VERSION 5.8 ;
BUSBITCHARS "[]" ;
DIVIDERCHAR "/" ;
UNITS
    DATABASE MICRONS 1000 ;
END UNITS

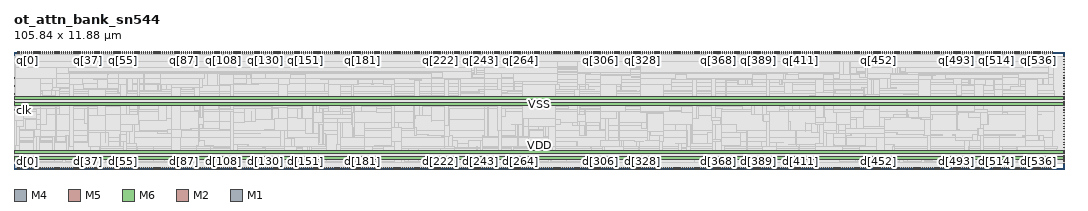
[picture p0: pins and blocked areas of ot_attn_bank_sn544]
MACRO ot_attn_bank_sn544
  FOREIGN ot_attn_bank_sn544 0 0 ;
  CLASS BLOCK ;
  SIZE 105.84 BY 11.88 ;
  PIN clk
    DIRECTION INPUT ;
    USE SIGNAL ;
    PORT
      LAYER M4 ;
        RECT  0 5.928 0.192 5.952 ;
    END
  END clk
  PIN d[0]
    DIRECTION INPUT ;
    USE SIGNAL ;
    PORT
      LAYER M5 ;
        RECT  0.384 0 0.408 0.192 ;
    END
  END d[0]
  PIN d[100]
    DIRECTION INPUT ;
    USE SIGNAL ;
    PORT
      LAYER M5 ;
        RECT  19.584 0 19.608 0.192 ;
    END
  END d[100]
  PIN d[101]
    DIRECTION INPUT ;
    USE SIGNAL ;
    PORT
      LAYER M5 ;
        RECT  19.776 0 19.8 0.192 ;
    END
  END d[101]
  PIN d[102]
    DIRECTION INPUT ;
    USE SIGNAL ;
    PORT
      LAYER M5 ;
        RECT  19.968 0 19.992 0.192 ;
    END
  END d[102]
  PIN d[103]
    DIRECTION INPUT ;
    USE SIGNAL ;
    PORT
      LAYER M5 ;
        RECT  20.16 0 20.184 0.192 ;
    END
  END d[103]
  PIN d[104]
    DIRECTION INPUT ;
    USE SIGNAL ;
    PORT
      LAYER M5 ;
        RECT  20.352 0 20.376 0.192 ;
    END
  END d[104]
  PIN d[105]
    DIRECTION INPUT ;
    USE SIGNAL ;
    PORT
      LAYER M5 ;
        RECT  20.544 0 20.568 0.192 ;
    END
  END d[105]
  PIN d[106]
    DIRECTION INPUT ;
    USE SIGNAL ;
    PORT
      LAYER M5 ;
        RECT  20.736 0 20.76 0.192 ;
    END
  END d[106]
  PIN d[107]
    DIRECTION INPUT ;
    USE SIGNAL ;
    PORT
      LAYER M5 ;
        RECT  20.928 0 20.952 0.192 ;
    END
  END d[107]
  PIN d[108]
    DIRECTION INPUT ;
    USE SIGNAL ;
    PORT
      LAYER M5 ;
        RECT  21.12 0 21.144 0.192 ;
    END
  END d[108]
  PIN d[109]
    DIRECTION INPUT ;
    USE SIGNAL ;
    PORT
      LAYER M5 ;
        RECT  21.312 0 21.336 0.192 ;
    END
  END d[109]
  PIN d[10]
    DIRECTION INPUT ;
    USE SIGNAL ;
    PORT
      LAYER M5 ;
        RECT  2.304 0 2.328 0.192 ;
    END
  END d[10]
  PIN d[110]
    DIRECTION INPUT ;
    USE SIGNAL ;
    PORT
      LAYER M5 ;
        RECT  21.504 0 21.528 0.192 ;
    END
  END d[110]
  PIN d[111]
    DIRECTION INPUT ;
    USE SIGNAL ;
    PORT
      LAYER M5 ;
        RECT  21.696 0 21.72 0.192 ;
    END
  END d[111]
  PIN d[112]
    DIRECTION INPUT ;
    USE SIGNAL ;
    PORT
      LAYER M5 ;
        RECT  21.888 0 21.912 0.192 ;
    END
  END d[112]
  PIN d[113]
    DIRECTION INPUT ;
    USE SIGNAL ;
    PORT
      LAYER M5 ;
        RECT  22.08 0 22.104 0.192 ;
    END
  END d[113]
  PIN d[114]
    DIRECTION INPUT ;
    USE SIGNAL ;
    PORT
      LAYER M5 ;
        RECT  22.272 0 22.296 0.192 ;
    END
  END d[114]
  PIN d[115]
    DIRECTION INPUT ;
    USE SIGNAL ;
    PORT
      LAYER M5 ;
        RECT  22.464 0 22.488 0.192 ;
    END
  END d[115]
  PIN d[116]
    DIRECTION INPUT ;
    USE SIGNAL ;
    PORT
      LAYER M5 ;
        RECT  22.656 0 22.68 0.192 ;
    END
  END d[116]
  PIN d[117]
    DIRECTION INPUT ;
    USE SIGNAL ;
    PORT
      LAYER M5 ;
        RECT  22.848 0 22.872 0.192 ;
    END
  END d[117]
  PIN d[118]
    DIRECTION INPUT ;
    USE SIGNAL ;
    PORT
      LAYER M5 ;
        RECT  23.04 0 23.064 0.192 ;
    END
  END d[118]
  PIN d[119]
    DIRECTION INPUT ;
    USE SIGNAL ;
    PORT
      LAYER M5 ;
        RECT  23.232 0 23.256 0.192 ;
    END
  END d[119]
  PIN d[11]
    DIRECTION INPUT ;
    USE SIGNAL ;
    PORT
      LAYER M5 ;
        RECT  2.496 0 2.52 0.192 ;
    END
  END d[11]
  PIN d[120]
    DIRECTION INPUT ;
    USE SIGNAL ;
    PORT
      LAYER M5 ;
        RECT  23.424 0 23.448 0.192 ;
    END
  END d[120]
  PIN d[121]
    DIRECTION INPUT ;
    USE SIGNAL ;
    PORT
      LAYER M5 ;
        RECT  23.616 0 23.64 0.192 ;
    END
  END d[121]
  PIN d[122]
    DIRECTION INPUT ;
    USE SIGNAL ;
    PORT
      LAYER M5 ;
        RECT  23.808 0 23.832 0.192 ;
    END
  END d[122]
  PIN d[123]
    DIRECTION INPUT ;
    USE SIGNAL ;
    PORT
      LAYER M5 ;
        RECT  24 0 24.024 0.192 ;
    END
  END d[123]
  PIN d[124]
    DIRECTION INPUT ;
    USE SIGNAL ;
    PORT
      LAYER M5 ;
        RECT  24.192 0 24.216 0.192 ;
    END
  END d[124]
  PIN d[125]
    DIRECTION INPUT ;
    USE SIGNAL ;
    PORT
      LAYER M5 ;
        RECT  24.384 0 24.408 0.192 ;
    END
  END d[125]
  PIN d[126]
    DIRECTION INPUT ;
    USE SIGNAL ;
    PORT
      LAYER M5 ;
        RECT  24.576 0 24.6 0.192 ;
    END
  END d[126]
  PIN d[127]
    DIRECTION INPUT ;
    USE SIGNAL ;
    PORT
      LAYER M5 ;
        RECT  24.768 0 24.792 0.192 ;
    END
  END d[127]
  PIN d[128]
    DIRECTION INPUT ;
    USE SIGNAL ;
    PORT
      LAYER M5 ;
        RECT  24.96 0 24.984 0.192 ;
    END
  END d[128]
  PIN d[129]
    DIRECTION INPUT ;
    USE SIGNAL ;
    PORT
      LAYER M5 ;
        RECT  25.152 0 25.176 0.192 ;
    END
  END d[129]
  PIN d[12]
    DIRECTION INPUT ;
    USE SIGNAL ;
    PORT
      LAYER M5 ;
        RECT  2.688 0 2.712 0.192 ;
    END
  END d[12]
  PIN d[130]
    DIRECTION INPUT ;
    USE SIGNAL ;
    PORT
      LAYER M5 ;
        RECT  25.344 0 25.368 0.192 ;
    END
  END d[130]
  PIN d[131]
    DIRECTION INPUT ;
    USE SIGNAL ;
    PORT
      LAYER M5 ;
        RECT  25.536 0 25.56 0.192 ;
    END
  END d[131]
  PIN d[132]
    DIRECTION INPUT ;
    USE SIGNAL ;
    PORT
      LAYER M5 ;
        RECT  25.728 0 25.752 0.192 ;
    END
  END d[132]
  PIN d[133]
    DIRECTION INPUT ;
    USE SIGNAL ;
    PORT
      LAYER M5 ;
        RECT  25.92 0 25.944 0.192 ;
    END
  END d[133]
  PIN d[134]
    DIRECTION INPUT ;
    USE SIGNAL ;
    PORT
      LAYER M5 ;
        RECT  26.112 0 26.136 0.192 ;
    END
  END d[134]
  PIN d[135]
    DIRECTION INPUT ;
    USE SIGNAL ;
    PORT
      LAYER M5 ;
        RECT  26.304 0 26.328 0.192 ;
    END
  END d[135]
  PIN d[136]
    DIRECTION INPUT ;
    USE SIGNAL ;
    PORT
      LAYER M5 ;
        RECT  26.496 0 26.52 0.192 ;
    END
  END d[136]
  PIN d[137]
    DIRECTION INPUT ;
    USE SIGNAL ;
    PORT
      LAYER M5 ;
        RECT  26.688 0 26.712 0.192 ;
    END
  END d[137]
  PIN d[138]
    DIRECTION INPUT ;
    USE SIGNAL ;
    PORT
      LAYER M5 ;
        RECT  26.88 0 26.904 0.192 ;
    END
  END d[138]
  PIN d[139]
    DIRECTION INPUT ;
    USE SIGNAL ;
    PORT
      LAYER M5 ;
        RECT  27.072 0 27.096 0.192 ;
    END
  END d[139]
  PIN d[13]
    DIRECTION INPUT ;
    USE SIGNAL ;
    PORT
      LAYER M5 ;
        RECT  2.88 0 2.904 0.192 ;
    END
  END d[13]
  PIN d[140]
    DIRECTION INPUT ;
    USE SIGNAL ;
    PORT
      LAYER M5 ;
        RECT  27.264 0 27.288 0.192 ;
    END
  END d[140]
  PIN d[141]
    DIRECTION INPUT ;
    USE SIGNAL ;
    PORT
      LAYER M5 ;
        RECT  27.456 0 27.48 0.192 ;
    END
  END d[141]
  PIN d[142]
    DIRECTION INPUT ;
    USE SIGNAL ;
    PORT
      LAYER M5 ;
        RECT  27.648 0 27.672 0.192 ;
    END
  END d[142]
  PIN d[143]
    DIRECTION INPUT ;
    USE SIGNAL ;
    PORT
      LAYER M5 ;
        RECT  27.84 0 27.864 0.192 ;
    END
  END d[143]
  PIN d[144]
    DIRECTION INPUT ;
    USE SIGNAL ;
    PORT
      LAYER M5 ;
        RECT  28.032 0 28.056 0.192 ;
    END
  END d[144]
  PIN d[145]
    DIRECTION INPUT ;
    USE SIGNAL ;
    PORT
      LAYER M5 ;
        RECT  28.224 0 28.248 0.192 ;
    END
  END d[145]
  PIN d[146]
    DIRECTION INPUT ;
    USE SIGNAL ;
    PORT
      LAYER M5 ;
        RECT  28.416 0 28.44 0.192 ;
    END
  END d[146]
  PIN d[147]
    DIRECTION INPUT ;
    USE SIGNAL ;
    PORT
      LAYER M5 ;
        RECT  28.608 0 28.632 0.192 ;
    END
  END d[147]
  PIN d[148]
    DIRECTION INPUT ;
    USE SIGNAL ;
    PORT
      LAYER M5 ;
        RECT  28.8 0 28.824 0.192 ;
    END
  END d[148]
  PIN d[149]
    DIRECTION INPUT ;
    USE SIGNAL ;
    PORT
      LAYER M5 ;
        RECT  28.992 0 29.016 0.192 ;
    END
  END d[149]
  PIN d[14]
    DIRECTION INPUT ;
    USE SIGNAL ;
    PORT
      LAYER M5 ;
        RECT  3.072 0 3.096 0.192 ;
    END
  END d[14]
  PIN d[150]
    DIRECTION INPUT ;
    USE SIGNAL ;
    PORT
      LAYER M5 ;
        RECT  29.184 0 29.208 0.192 ;
    END
  END d[150]
  PIN d[151]
    DIRECTION INPUT ;
    USE SIGNAL ;
    PORT
      LAYER M5 ;
        RECT  29.376 0 29.4 0.192 ;
    END
  END d[151]
  PIN d[152]
    DIRECTION INPUT ;
    USE SIGNAL ;
    PORT
      LAYER M5 ;
        RECT  29.568 0 29.592 0.192 ;
    END
  END d[152]
  PIN d[153]
    DIRECTION INPUT ;
    USE SIGNAL ;
    PORT
      LAYER M5 ;
        RECT  29.76 0 29.784 0.192 ;
    END
  END d[153]
  PIN d[154]
    DIRECTION INPUT ;
    USE SIGNAL ;
    PORT
      LAYER M5 ;
        RECT  29.952 0 29.976 0.192 ;
    END
  END d[154]
  PIN d[155]
    DIRECTION INPUT ;
    USE SIGNAL ;
    PORT
      LAYER M5 ;
        RECT  30.144 0 30.168 0.192 ;
    END
  END d[155]
  PIN d[156]
    DIRECTION INPUT ;
    USE SIGNAL ;
    PORT
      LAYER M5 ;
        RECT  30.336 0 30.36 0.192 ;
    END
  END d[156]
  PIN d[157]
    DIRECTION INPUT ;
    USE SIGNAL ;
    PORT
      LAYER M5 ;
        RECT  30.528 0 30.552 0.192 ;
    END
  END d[157]
  PIN d[158]
    DIRECTION INPUT ;
    USE SIGNAL ;
    PORT
      LAYER M5 ;
        RECT  30.72 0 30.744 0.192 ;
    END
  END d[158]
  PIN d[159]
    DIRECTION INPUT ;
    USE SIGNAL ;
    PORT
      LAYER M5 ;
        RECT  30.912 0 30.936 0.192 ;
    END
  END d[159]
  PIN d[15]
    DIRECTION INPUT ;
    USE SIGNAL ;
    PORT
      LAYER M5 ;
        RECT  3.264 0 3.288 0.192 ;
    END
  END d[15]
  PIN d[160]
    DIRECTION INPUT ;
    USE SIGNAL ;
    PORT
      LAYER M5 ;
        RECT  31.104 0 31.128 0.192 ;
    END
  END d[160]
  PIN d[161]
    DIRECTION INPUT ;
    USE SIGNAL ;
    PORT
      LAYER M5 ;
        RECT  31.296 0 31.32 0.192 ;
    END
  END d[161]
  PIN d[162]
    DIRECTION INPUT ;
    USE SIGNAL ;
    PORT
      LAYER M5 ;
        RECT  31.488 0 31.512 0.192 ;
    END
  END d[162]
  PIN d[163]
    DIRECTION INPUT ;
    USE SIGNAL ;
    PORT
      LAYER M5 ;
        RECT  31.68 0 31.704 0.192 ;
    END
  END d[163]
  PIN d[164]
    DIRECTION INPUT ;
    USE SIGNAL ;
    PORT
      LAYER M5 ;
        RECT  31.872 0 31.896 0.192 ;
    END
  END d[164]
  PIN d[165]
    DIRECTION INPUT ;
    USE SIGNAL ;
    PORT
      LAYER M5 ;
        RECT  32.064 0 32.088 0.192 ;
    END
  END d[165]
  PIN d[166]
    DIRECTION INPUT ;
    USE SIGNAL ;
    PORT
      LAYER M5 ;
        RECT  32.256 0 32.28 0.192 ;
    END
  END d[166]
  PIN d[167]
    DIRECTION INPUT ;
    USE SIGNAL ;
    PORT
      LAYER M5 ;
        RECT  32.448 0 32.472 0.192 ;
    END
  END d[167]
  PIN d[168]
    DIRECTION INPUT ;
    USE SIGNAL ;
    PORT
      LAYER M5 ;
        RECT  32.64 0 32.664 0.192 ;
    END
  END d[168]
  PIN d[169]
    DIRECTION INPUT ;
    USE SIGNAL ;
    PORT
      LAYER M5 ;
        RECT  32.832 0 32.856 0.192 ;
    END
  END d[169]
  PIN d[16]
    DIRECTION INPUT ;
    USE SIGNAL ;
    PORT
      LAYER M5 ;
        RECT  3.456 0 3.48 0.192 ;
    END
  END d[16]
  PIN d[170]
    DIRECTION INPUT ;
    USE SIGNAL ;
    PORT
      LAYER M5 ;
        RECT  33.024 0 33.048 0.192 ;
    END
  END d[170]
  PIN d[171]
    DIRECTION INPUT ;
    USE SIGNAL ;
    PORT
      LAYER M5 ;
        RECT  33.216 0 33.24 0.192 ;
    END
  END d[171]
  PIN d[172]
    DIRECTION INPUT ;
    USE SIGNAL ;
    PORT
      LAYER M5 ;
        RECT  33.408 0 33.432 0.192 ;
    END
  END d[172]
  PIN d[173]
    DIRECTION INPUT ;
    USE SIGNAL ;
    PORT
      LAYER M5 ;
        RECT  33.6 0 33.624 0.192 ;
    END
  END d[173]
  PIN d[174]
    DIRECTION INPUT ;
    USE SIGNAL ;
    PORT
      LAYER M5 ;
        RECT  33.792 0 33.816 0.192 ;
    END
  END d[174]
  PIN d[175]
    DIRECTION INPUT ;
    USE SIGNAL ;
    PORT
      LAYER M5 ;
        RECT  33.984 0 34.008 0.192 ;
    END
  END d[175]
  PIN d[176]
    DIRECTION INPUT ;
    USE SIGNAL ;
    PORT
      LAYER M5 ;
        RECT  34.176 0 34.2 0.192 ;
    END
  END d[176]
  PIN d[177]
    DIRECTION INPUT ;
    USE SIGNAL ;
    PORT
      LAYER M5 ;
        RECT  34.368 0 34.392 0.192 ;
    END
  END d[177]
  PIN d[178]
    DIRECTION INPUT ;
    USE SIGNAL ;
    PORT
      LAYER M5 ;
        RECT  34.56 0 34.584 0.192 ;
    END
  END d[178]
  PIN d[179]
    DIRECTION INPUT ;
    USE SIGNAL ;
    PORT
      LAYER M5 ;
        RECT  34.752 0 34.776 0.192 ;
    END
  END d[179]
  PIN d[17]
    DIRECTION INPUT ;
    USE SIGNAL ;
    PORT
      LAYER M5 ;
        RECT  3.648 0 3.672 0.192 ;
    END
  END d[17]
  PIN d[180]
    DIRECTION INPUT ;
    USE SIGNAL ;
    PORT
      LAYER M5 ;
        RECT  34.944 0 34.968 0.192 ;
    END
  END d[180]
  PIN d[181]
    DIRECTION INPUT ;
    USE SIGNAL ;
    PORT
      LAYER M5 ;
        RECT  35.136 0 35.16 0.192 ;
    END
  END d[181]
  PIN d[182]
    DIRECTION INPUT ;
    USE SIGNAL ;
    PORT
      LAYER M5 ;
        RECT  35.328 0 35.352 0.192 ;
    END
  END d[182]
  PIN d[183]
    DIRECTION INPUT ;
    USE SIGNAL ;
    PORT
      LAYER M5 ;
        RECT  35.52 0 35.544 0.192 ;
    END
  END d[183]
  PIN d[184]
    DIRECTION INPUT ;
    USE SIGNAL ;
    PORT
      LAYER M5 ;
        RECT  35.712 0 35.736 0.192 ;
    END
  END d[184]
  PIN d[185]
    DIRECTION INPUT ;
    USE SIGNAL ;
    PORT
      LAYER M5 ;
        RECT  35.904 0 35.928 0.192 ;
    END
  END d[185]
  PIN d[186]
    DIRECTION INPUT ;
    USE SIGNAL ;
    PORT
      LAYER M5 ;
        RECT  36.096 0 36.12 0.192 ;
    END
  END d[186]
  PIN d[187]
    DIRECTION INPUT ;
    USE SIGNAL ;
    PORT
      LAYER M5 ;
        RECT  36.288 0 36.312 0.192 ;
    END
  END d[187]
  PIN d[188]
    DIRECTION INPUT ;
    USE SIGNAL ;
    PORT
      LAYER M5 ;
        RECT  36.48 0 36.504 0.192 ;
    END
  END d[188]
  PIN d[189]
    DIRECTION INPUT ;
    USE SIGNAL ;
    PORT
      LAYER M5 ;
        RECT  36.672 0 36.696 0.192 ;
    END
  END d[189]
  PIN d[18]
    DIRECTION INPUT ;
    USE SIGNAL ;
    PORT
      LAYER M5 ;
        RECT  3.84 0 3.864 0.192 ;
    END
  END d[18]
  PIN d[190]
    DIRECTION INPUT ;
    USE SIGNAL ;
    PORT
      LAYER M5 ;
        RECT  36.864 0 36.888 0.192 ;
    END
  END d[190]
  PIN d[191]
    DIRECTION INPUT ;
    USE SIGNAL ;
    PORT
      LAYER M5 ;
        RECT  37.056 0 37.08 0.192 ;
    END
  END d[191]
  PIN d[192]
    DIRECTION INPUT ;
    USE SIGNAL ;
    PORT
      LAYER M5 ;
        RECT  37.248 0 37.272 0.192 ;
    END
  END d[192]
  PIN d[193]
    DIRECTION INPUT ;
    USE SIGNAL ;
    PORT
      LAYER M5 ;
        RECT  37.44 0 37.464 0.192 ;
    END
  END d[193]
  PIN d[194]
    DIRECTION INPUT ;
    USE SIGNAL ;
    PORT
      LAYER M5 ;
        RECT  37.632 0 37.656 0.192 ;
    END
  END d[194]
  PIN d[195]
    DIRECTION INPUT ;
    USE SIGNAL ;
    PORT
      LAYER M5 ;
        RECT  37.824 0 37.848 0.192 ;
    END
  END d[195]
  PIN d[196]
    DIRECTION INPUT ;
    USE SIGNAL ;
    PORT
      LAYER M5 ;
        RECT  38.016 0 38.04 0.192 ;
    END
  END d[196]
  PIN d[197]
    DIRECTION INPUT ;
    USE SIGNAL ;
    PORT
      LAYER M5 ;
        RECT  38.208 0 38.232 0.192 ;
    END
  END d[197]
  PIN d[198]
    DIRECTION INPUT ;
    USE SIGNAL ;
    PORT
      LAYER M5 ;
        RECT  38.4 0 38.424 0.192 ;
    END
  END d[198]
  PIN d[199]
    DIRECTION INPUT ;
    USE SIGNAL ;
    PORT
      LAYER M5 ;
        RECT  38.592 0 38.616 0.192 ;
    END
  END d[199]
  PIN d[19]
    DIRECTION INPUT ;
    USE SIGNAL ;
    PORT
      LAYER M5 ;
        RECT  4.032 0 4.056 0.192 ;
    END
  END d[19]
  PIN d[1]
    DIRECTION INPUT ;
    USE SIGNAL ;
    PORT
      LAYER M5 ;
        RECT  0.576 0 0.6 0.192 ;
    END
  END d[1]
  PIN d[200]
    DIRECTION INPUT ;
    USE SIGNAL ;
    PORT
      LAYER M5 ;
        RECT  38.784 0 38.808 0.192 ;
    END
  END d[200]
  PIN d[201]
    DIRECTION INPUT ;
    USE SIGNAL ;
    PORT
      LAYER M5 ;
        RECT  38.976 0 39 0.192 ;
    END
  END d[201]
  PIN d[202]
    DIRECTION INPUT ;
    USE SIGNAL ;
    PORT
      LAYER M5 ;
        RECT  39.168 0 39.192 0.192 ;
    END
  END d[202]
  PIN d[203]
    DIRECTION INPUT ;
    USE SIGNAL ;
    PORT
      LAYER M5 ;
        RECT  39.36 0 39.384 0.192 ;
    END
  END d[203]
  PIN d[204]
    DIRECTION INPUT ;
    USE SIGNAL ;
    PORT
      LAYER M5 ;
        RECT  39.552 0 39.576 0.192 ;
    END
  END d[204]
  PIN d[205]
    DIRECTION INPUT ;
    USE SIGNAL ;
    PORT
      LAYER M5 ;
        RECT  39.744 0 39.768 0.192 ;
    END
  END d[205]
  PIN d[206]
    DIRECTION INPUT ;
    USE SIGNAL ;
    PORT
      LAYER M5 ;
        RECT  39.936 0 39.96 0.192 ;
    END
  END d[206]
  PIN d[207]
    DIRECTION INPUT ;
    USE SIGNAL ;
    PORT
      LAYER M5 ;
        RECT  40.128 0 40.152 0.192 ;
    END
  END d[207]
  PIN d[208]
    DIRECTION INPUT ;
    USE SIGNAL ;
    PORT
      LAYER M5 ;
        RECT  40.32 0 40.344 0.192 ;
    END
  END d[208]
  PIN d[209]
    DIRECTION INPUT ;
    USE SIGNAL ;
    PORT
      LAYER M5 ;
        RECT  40.512 0 40.536 0.192 ;
    END
  END d[209]
  PIN d[20]
    DIRECTION INPUT ;
    USE SIGNAL ;
    PORT
      LAYER M5 ;
        RECT  4.224 0 4.248 0.192 ;
    END
  END d[20]
  PIN d[210]
    DIRECTION INPUT ;
    USE SIGNAL ;
    PORT
      LAYER M5 ;
        RECT  40.704 0 40.728 0.192 ;
    END
  END d[210]
  PIN d[211]
    DIRECTION INPUT ;
    USE SIGNAL ;
    PORT
      LAYER M5 ;
        RECT  40.896 0 40.92 0.192 ;
    END
  END d[211]
  PIN d[212]
    DIRECTION INPUT ;
    USE SIGNAL ;
    PORT
      LAYER M5 ;
        RECT  41.088 0 41.112 0.192 ;
    END
  END d[212]
  PIN d[213]
    DIRECTION INPUT ;
    USE SIGNAL ;
    PORT
      LAYER M5 ;
        RECT  41.28 0 41.304 0.192 ;
    END
  END d[213]
  PIN d[214]
    DIRECTION INPUT ;
    USE SIGNAL ;
    PORT
      LAYER M5 ;
        RECT  41.472 0 41.496 0.192 ;
    END
  END d[214]
  PIN d[215]
    DIRECTION INPUT ;
    USE SIGNAL ;
    PORT
      LAYER M5 ;
        RECT  41.664 0 41.688 0.192 ;
    END
  END d[215]
  PIN d[216]
    DIRECTION INPUT ;
    USE SIGNAL ;
    PORT
      LAYER M5 ;
        RECT  41.856 0 41.88 0.192 ;
    END
  END d[216]
  PIN d[217]
    DIRECTION INPUT ;
    USE SIGNAL ;
    PORT
      LAYER M5 ;
        RECT  42.048 0 42.072 0.192 ;
    END
  END d[217]
  PIN d[218]
    DIRECTION INPUT ;
    USE SIGNAL ;
    PORT
      LAYER M5 ;
        RECT  42.24 0 42.264 0.192 ;
    END
  END d[218]
  PIN d[219]
    DIRECTION INPUT ;
    USE SIGNAL ;
    PORT
      LAYER M5 ;
        RECT  42.432 0 42.456 0.192 ;
    END
  END d[219]
  PIN d[21]
    DIRECTION INPUT ;
    USE SIGNAL ;
    PORT
      LAYER M5 ;
        RECT  4.416 0 4.44 0.192 ;
    END
  END d[21]
  PIN d[220]
    DIRECTION INPUT ;
    USE SIGNAL ;
    PORT
      LAYER M5 ;
        RECT  42.624 0 42.648 0.192 ;
    END
  END d[220]
  PIN d[221]
    DIRECTION INPUT ;
    USE SIGNAL ;
    PORT
      LAYER M5 ;
        RECT  42.816 0 42.84 0.192 ;
    END
  END d[221]
  PIN d[222]
    DIRECTION INPUT ;
    USE SIGNAL ;
    PORT
      LAYER M5 ;
        RECT  43.008 0 43.032 0.192 ;
    END
  END d[222]
  PIN d[223]
    DIRECTION INPUT ;
    USE SIGNAL ;
    PORT
      LAYER M5 ;
        RECT  43.2 0 43.224 0.192 ;
    END
  END d[223]
  PIN d[224]
    DIRECTION INPUT ;
    USE SIGNAL ;
    PORT
      LAYER M5 ;
        RECT  43.392 0 43.416 0.192 ;
    END
  END d[224]
  PIN d[225]
    DIRECTION INPUT ;
    USE SIGNAL ;
    PORT
      LAYER M5 ;
        RECT  43.584 0 43.608 0.192 ;
    END
  END d[225]
  PIN d[226]
    DIRECTION INPUT ;
    USE SIGNAL ;
    PORT
      LAYER M5 ;
        RECT  43.776 0 43.8 0.192 ;
    END
  END d[226]
  PIN d[227]
    DIRECTION INPUT ;
    USE SIGNAL ;
    PORT
      LAYER M5 ;
        RECT  43.968 0 43.992 0.192 ;
    END
  END d[227]
  PIN d[228]
    DIRECTION INPUT ;
    USE SIGNAL ;
    PORT
      LAYER M5 ;
        RECT  44.16 0 44.184 0.192 ;
    END
  END d[228]
  PIN d[229]
    DIRECTION INPUT ;
    USE SIGNAL ;
    PORT
      LAYER M5 ;
        RECT  44.352 0 44.376 0.192 ;
    END
  END d[229]
  PIN d[22]
    DIRECTION INPUT ;
    USE SIGNAL ;
    PORT
      LAYER M5 ;
        RECT  4.608 0 4.632 0.192 ;
    END
  END d[22]
  PIN d[230]
    DIRECTION INPUT ;
    USE SIGNAL ;
    PORT
      LAYER M5 ;
        RECT  44.544 0 44.568 0.192 ;
    END
  END d[230]
  PIN d[231]
    DIRECTION INPUT ;
    USE SIGNAL ;
    PORT
      LAYER M5 ;
        RECT  44.736 0 44.76 0.192 ;
    END
  END d[231]
  PIN d[232]
    DIRECTION INPUT ;
    USE SIGNAL ;
    PORT
      LAYER M5 ;
        RECT  44.928 0 44.952 0.192 ;
    END
  END d[232]
  PIN d[233]
    DIRECTION INPUT ;
    USE SIGNAL ;
    PORT
      LAYER M5 ;
        RECT  45.12 0 45.144 0.192 ;
    END
  END d[233]
  PIN d[234]
    DIRECTION INPUT ;
    USE SIGNAL ;
    PORT
      LAYER M5 ;
        RECT  45.312 0 45.336 0.192 ;
    END
  END d[234]
  PIN d[235]
    DIRECTION INPUT ;
    USE SIGNAL ;
    PORT
      LAYER M5 ;
        RECT  45.504 0 45.528 0.192 ;
    END
  END d[235]
  PIN d[236]
    DIRECTION INPUT ;
    USE SIGNAL ;
    PORT
      LAYER M5 ;
        RECT  45.696 0 45.72 0.192 ;
    END
  END d[236]
  PIN d[237]
    DIRECTION INPUT ;
    USE SIGNAL ;
    PORT
      LAYER M5 ;
        RECT  45.888 0 45.912 0.192 ;
    END
  END d[237]
  PIN d[238]
    DIRECTION INPUT ;
    USE SIGNAL ;
    PORT
      LAYER M5 ;
        RECT  46.08 0 46.104 0.192 ;
    END
  END d[238]
  PIN d[239]
    DIRECTION INPUT ;
    USE SIGNAL ;
    PORT
      LAYER M5 ;
        RECT  46.272 0 46.296 0.192 ;
    END
  END d[239]
  PIN d[23]
    DIRECTION INPUT ;
    USE SIGNAL ;
    PORT
      LAYER M5 ;
        RECT  4.8 0 4.824 0.192 ;
    END
  END d[23]
  PIN d[240]
    DIRECTION INPUT ;
    USE SIGNAL ;
    PORT
      LAYER M5 ;
        RECT  46.464 0 46.488 0.192 ;
    END
  END d[240]
  PIN d[241]
    DIRECTION INPUT ;
    USE SIGNAL ;
    PORT
      LAYER M5 ;
        RECT  46.656 0 46.68 0.192 ;
    END
  END d[241]
  PIN d[242]
    DIRECTION INPUT ;
    USE SIGNAL ;
    PORT
      LAYER M5 ;
        RECT  46.848 0 46.872 0.192 ;
    END
  END d[242]
  PIN d[243]
    DIRECTION INPUT ;
    USE SIGNAL ;
    PORT
      LAYER M5 ;
        RECT  47.04 0 47.064 0.192 ;
    END
  END d[243]
  PIN d[244]
    DIRECTION INPUT ;
    USE SIGNAL ;
    PORT
      LAYER M5 ;
        RECT  47.232 0 47.256 0.192 ;
    END
  END d[244]
  PIN d[245]
    DIRECTION INPUT ;
    USE SIGNAL ;
    PORT
      LAYER M5 ;
        RECT  47.424 0 47.448 0.192 ;
    END
  END d[245]
  PIN d[246]
    DIRECTION INPUT ;
    USE SIGNAL ;
    PORT
      LAYER M5 ;
        RECT  47.616 0 47.64 0.192 ;
    END
  END d[246]
  PIN d[247]
    DIRECTION INPUT ;
    USE SIGNAL ;
    PORT
      LAYER M5 ;
        RECT  47.808 0 47.832 0.192 ;
    END
  END d[247]
  PIN d[248]
    DIRECTION INPUT ;
    USE SIGNAL ;
    PORT
      LAYER M5 ;
        RECT  48 0 48.024 0.192 ;
    END
  END d[248]
  PIN d[249]
    DIRECTION INPUT ;
    USE SIGNAL ;
    PORT
      LAYER M5 ;
        RECT  48.192 0 48.216 0.192 ;
    END
  END d[249]
  PIN d[24]
    DIRECTION INPUT ;
    USE SIGNAL ;
    PORT
      LAYER M5 ;
        RECT  4.992 0 5.016 0.192 ;
    END
  END d[24]
  PIN d[250]
    DIRECTION INPUT ;
    USE SIGNAL ;
    PORT
      LAYER M5 ;
        RECT  48.384 0 48.408 0.192 ;
    END
  END d[250]
  PIN d[251]
    DIRECTION INPUT ;
    USE SIGNAL ;
    PORT
      LAYER M5 ;
        RECT  48.576 0 48.6 0.192 ;
    END
  END d[251]
  PIN d[252]
    DIRECTION INPUT ;
    USE SIGNAL ;
    PORT
      LAYER M5 ;
        RECT  48.768 0 48.792 0.192 ;
    END
  END d[252]
  PIN d[253]
    DIRECTION INPUT ;
    USE SIGNAL ;
    PORT
      LAYER M5 ;
        RECT  48.96 0 48.984 0.192 ;
    END
  END d[253]
  PIN d[254]
    DIRECTION INPUT ;
    USE SIGNAL ;
    PORT
      LAYER M5 ;
        RECT  49.152 0 49.176 0.192 ;
    END
  END d[254]
  PIN d[255]
    DIRECTION INPUT ;
    USE SIGNAL ;
    PORT
      LAYER M5 ;
        RECT  49.344 0 49.368 0.192 ;
    END
  END d[255]
  PIN d[256]
    DIRECTION INPUT ;
    USE SIGNAL ;
    PORT
      LAYER M5 ;
        RECT  49.536 0 49.56 0.192 ;
    END
  END d[256]
  PIN d[257]
    DIRECTION INPUT ;
    USE SIGNAL ;
    PORT
      LAYER M5 ;
        RECT  49.728 0 49.752 0.192 ;
    END
  END d[257]
  PIN d[258]
    DIRECTION INPUT ;
    USE SIGNAL ;
    PORT
      LAYER M5 ;
        RECT  49.92 0 49.944 0.192 ;
    END
  END d[258]
  PIN d[259]
    DIRECTION INPUT ;
    USE SIGNAL ;
    PORT
      LAYER M5 ;
        RECT  50.112 0 50.136 0.192 ;
    END
  END d[259]
  PIN d[25]
    DIRECTION INPUT ;
    USE SIGNAL ;
    PORT
      LAYER M5 ;
        RECT  5.184 0 5.208 0.192 ;
    END
  END d[25]
  PIN d[260]
    DIRECTION INPUT ;
    USE SIGNAL ;
    PORT
      LAYER M5 ;
        RECT  50.304 0 50.328 0.192 ;
    END
  END d[260]
  PIN d[261]
    DIRECTION INPUT ;
    USE SIGNAL ;
    PORT
      LAYER M5 ;
        RECT  50.496 0 50.52 0.192 ;
    END
  END d[261]
  PIN d[262]
    DIRECTION INPUT ;
    USE SIGNAL ;
    PORT
      LAYER M5 ;
        RECT  50.688 0 50.712 0.192 ;
    END
  END d[262]
  PIN d[263]
    DIRECTION INPUT ;
    USE SIGNAL ;
    PORT
      LAYER M5 ;
        RECT  50.88 0 50.904 0.192 ;
    END
  END d[263]
  PIN d[264]
    DIRECTION INPUT ;
    USE SIGNAL ;
    PORT
      LAYER M5 ;
        RECT  51.072 0 51.096 0.192 ;
    END
  END d[264]
  PIN d[265]
    DIRECTION INPUT ;
    USE SIGNAL ;
    PORT
      LAYER M5 ;
        RECT  51.264 0 51.288 0.192 ;
    END
  END d[265]
  PIN d[266]
    DIRECTION INPUT ;
    USE SIGNAL ;
    PORT
      LAYER M5 ;
        RECT  51.456 0 51.48 0.192 ;
    END
  END d[266]
  PIN d[267]
    DIRECTION INPUT ;
    USE SIGNAL ;
    PORT
      LAYER M5 ;
        RECT  51.648 0 51.672 0.192 ;
    END
  END d[267]
  PIN d[268]
    DIRECTION INPUT ;
    USE SIGNAL ;
    PORT
      LAYER M5 ;
        RECT  51.84 0 51.864 0.192 ;
    END
  END d[268]
  PIN d[269]
    DIRECTION INPUT ;
    USE SIGNAL ;
    PORT
      LAYER M5 ;
        RECT  52.032 0 52.056 0.192 ;
    END
  END d[269]
  PIN d[26]
    DIRECTION INPUT ;
    USE SIGNAL ;
    PORT
      LAYER M5 ;
        RECT  5.376 0 5.4 0.192 ;
    END
  END d[26]
  PIN d[270]
    DIRECTION INPUT ;
    USE SIGNAL ;
    PORT
      LAYER M5 ;
        RECT  52.224 0 52.248 0.192 ;
    END
  END d[270]
  PIN d[271]
    DIRECTION INPUT ;
    USE SIGNAL ;
    PORT
      LAYER M5 ;
        RECT  52.416 0 52.44 0.192 ;
    END
  END d[271]
  PIN d[272]
    DIRECTION INPUT ;
    USE SIGNAL ;
    PORT
      LAYER M5 ;
        RECT  52.608 0 52.632 0.192 ;
    END
  END d[272]
  PIN d[273]
    DIRECTION INPUT ;
    USE SIGNAL ;
    PORT
      LAYER M5 ;
        RECT  52.8 0 52.824 0.192 ;
    END
  END d[273]
  PIN d[274]
    DIRECTION INPUT ;
    USE SIGNAL ;
    PORT
      LAYER M5 ;
        RECT  52.992 0 53.016 0.192 ;
    END
  END d[274]
  PIN d[275]
    DIRECTION INPUT ;
    USE SIGNAL ;
    PORT
      LAYER M5 ;
        RECT  53.184 0 53.208 0.192 ;
    END
  END d[275]
  PIN d[276]
    DIRECTION INPUT ;
    USE SIGNAL ;
    PORT
      LAYER M5 ;
        RECT  53.376 0 53.4 0.192 ;
    END
  END d[276]
  PIN d[277]
    DIRECTION INPUT ;
    USE SIGNAL ;
    PORT
      LAYER M5 ;
        RECT  53.568 0 53.592 0.192 ;
    END
  END d[277]
  PIN d[278]
    DIRECTION INPUT ;
    USE SIGNAL ;
    PORT
      LAYER M5 ;
        RECT  53.76 0 53.784 0.192 ;
    END
  END d[278]
  PIN d[279]
    DIRECTION INPUT ;
    USE SIGNAL ;
    PORT
      LAYER M5 ;
        RECT  53.952 0 53.976 0.192 ;
    END
  END d[279]
  PIN d[27]
    DIRECTION INPUT ;
    USE SIGNAL ;
    PORT
      LAYER M5 ;
        RECT  5.568 0 5.592 0.192 ;
    END
  END d[27]
  PIN d[280]
    DIRECTION INPUT ;
    USE SIGNAL ;
    PORT
      LAYER M5 ;
        RECT  54.144 0 54.168 0.192 ;
    END
  END d[280]
  PIN d[281]
    DIRECTION INPUT ;
    USE SIGNAL ;
    PORT
      LAYER M5 ;
        RECT  54.336 0 54.36 0.192 ;
    END
  END d[281]
  PIN d[282]
    DIRECTION INPUT ;
    USE SIGNAL ;
    PORT
      LAYER M5 ;
        RECT  54.528 0 54.552 0.192 ;
    END
  END d[282]
  PIN d[283]
    DIRECTION INPUT ;
    USE SIGNAL ;
    PORT
      LAYER M5 ;
        RECT  54.72 0 54.744 0.192 ;
    END
  END d[283]
  PIN d[284]
    DIRECTION INPUT ;
    USE SIGNAL ;
    PORT
      LAYER M5 ;
        RECT  54.912 0 54.936 0.192 ;
    END
  END d[284]
  PIN d[285]
    DIRECTION INPUT ;
    USE SIGNAL ;
    PORT
      LAYER M5 ;
        RECT  55.104 0 55.128 0.192 ;
    END
  END d[285]
  PIN d[286]
    DIRECTION INPUT ;
    USE SIGNAL ;
    PORT
      LAYER M5 ;
        RECT  55.296 0 55.32 0.192 ;
    END
  END d[286]
  PIN d[287]
    DIRECTION INPUT ;
    USE SIGNAL ;
    PORT
      LAYER M5 ;
        RECT  55.488 0 55.512 0.192 ;
    END
  END d[287]
  PIN d[288]
    DIRECTION INPUT ;
    USE SIGNAL ;
    PORT
      LAYER M5 ;
        RECT  55.68 0 55.704 0.192 ;
    END
  END d[288]
  PIN d[289]
    DIRECTION INPUT ;
    USE SIGNAL ;
    PORT
      LAYER M5 ;
        RECT  55.872 0 55.896 0.192 ;
    END
  END d[289]
  PIN d[28]
    DIRECTION INPUT ;
    USE SIGNAL ;
    PORT
      LAYER M5 ;
        RECT  5.76 0 5.784 0.192 ;
    END
  END d[28]
  PIN d[290]
    DIRECTION INPUT ;
    USE SIGNAL ;
    PORT
      LAYER M5 ;
        RECT  56.064 0 56.088 0.192 ;
    END
  END d[290]
  PIN d[291]
    DIRECTION INPUT ;
    USE SIGNAL ;
    PORT
      LAYER M5 ;
        RECT  56.256 0 56.28 0.192 ;
    END
  END d[291]
  PIN d[292]
    DIRECTION INPUT ;
    USE SIGNAL ;
    PORT
      LAYER M5 ;
        RECT  56.448 0 56.472 0.192 ;
    END
  END d[292]
  PIN d[293]
    DIRECTION INPUT ;
    USE SIGNAL ;
    PORT
      LAYER M5 ;
        RECT  56.64 0 56.664 0.192 ;
    END
  END d[293]
  PIN d[294]
    DIRECTION INPUT ;
    USE SIGNAL ;
    PORT
      LAYER M5 ;
        RECT  56.832 0 56.856 0.192 ;
    END
  END d[294]
  PIN d[295]
    DIRECTION INPUT ;
    USE SIGNAL ;
    PORT
      LAYER M5 ;
        RECT  57.024 0 57.048 0.192 ;
    END
  END d[295]
  PIN d[296]
    DIRECTION INPUT ;
    USE SIGNAL ;
    PORT
      LAYER M5 ;
        RECT  57.216 0 57.24 0.192 ;
    END
  END d[296]
  PIN d[297]
    DIRECTION INPUT ;
    USE SIGNAL ;
    PORT
      LAYER M5 ;
        RECT  57.408 0 57.432 0.192 ;
    END
  END d[297]
  PIN d[298]
    DIRECTION INPUT ;
    USE SIGNAL ;
    PORT
      LAYER M5 ;
        RECT  57.6 0 57.624 0.192 ;
    END
  END d[298]
  PIN d[299]
    DIRECTION INPUT ;
    USE SIGNAL ;
    PORT
      LAYER M5 ;
        RECT  57.792 0 57.816 0.192 ;
    END
  END d[299]
  PIN d[29]
    DIRECTION INPUT ;
    USE SIGNAL ;
    PORT
      LAYER M5 ;
        RECT  5.952 0 5.976 0.192 ;
    END
  END d[29]
  PIN d[2]
    DIRECTION INPUT ;
    USE SIGNAL ;
    PORT
      LAYER M5 ;
        RECT  0.768 0 0.792 0.192 ;
    END
  END d[2]
  PIN d[300]
    DIRECTION INPUT ;
    USE SIGNAL ;
    PORT
      LAYER M5 ;
        RECT  57.984 0 58.008 0.192 ;
    END
  END d[300]
  PIN d[301]
    DIRECTION INPUT ;
    USE SIGNAL ;
    PORT
      LAYER M5 ;
        RECT  58.176 0 58.2 0.192 ;
    END
  END d[301]
  PIN d[302]
    DIRECTION INPUT ;
    USE SIGNAL ;
    PORT
      LAYER M5 ;
        RECT  58.368 0 58.392 0.192 ;
    END
  END d[302]
  PIN d[303]
    DIRECTION INPUT ;
    USE SIGNAL ;
    PORT
      LAYER M5 ;
        RECT  58.56 0 58.584 0.192 ;
    END
  END d[303]
  PIN d[304]
    DIRECTION INPUT ;
    USE SIGNAL ;
    PORT
      LAYER M5 ;
        RECT  58.752 0 58.776 0.192 ;
    END
  END d[304]
  PIN d[305]
    DIRECTION INPUT ;
    USE SIGNAL ;
    PORT
      LAYER M5 ;
        RECT  58.944 0 58.968 0.192 ;
    END
  END d[305]
  PIN d[306]
    DIRECTION INPUT ;
    USE SIGNAL ;
    PORT
      LAYER M5 ;
        RECT  59.136 0 59.16 0.192 ;
    END
  END d[306]
  PIN d[307]
    DIRECTION INPUT ;
    USE SIGNAL ;
    PORT
      LAYER M5 ;
        RECT  59.328 0 59.352 0.192 ;
    END
  END d[307]
  PIN d[308]
    DIRECTION INPUT ;
    USE SIGNAL ;
    PORT
      LAYER M5 ;
        RECT  59.52 0 59.544 0.192 ;
    END
  END d[308]
  PIN d[309]
    DIRECTION INPUT ;
    USE SIGNAL ;
    PORT
      LAYER M5 ;
        RECT  59.712 0 59.736 0.192 ;
    END
  END d[309]
  PIN d[30]
    DIRECTION INPUT ;
    USE SIGNAL ;
    PORT
      LAYER M5 ;
        RECT  6.144 0 6.168 0.192 ;
    END
  END d[30]
  PIN d[310]
    DIRECTION INPUT ;
    USE SIGNAL ;
    PORT
      LAYER M5 ;
        RECT  59.904 0 59.928 0.192 ;
    END
  END d[310]
  PIN d[311]
    DIRECTION INPUT ;
    USE SIGNAL ;
    PORT
      LAYER M5 ;
        RECT  60.096 0 60.12 0.192 ;
    END
  END d[311]
  PIN d[312]
    DIRECTION INPUT ;
    USE SIGNAL ;
    PORT
      LAYER M5 ;
        RECT  60.288 0 60.312 0.192 ;
    END
  END d[312]
  PIN d[313]
    DIRECTION INPUT ;
    USE SIGNAL ;
    PORT
      LAYER M5 ;
        RECT  60.48 0 60.504 0.192 ;
    END
  END d[313]
  PIN d[314]
    DIRECTION INPUT ;
    USE SIGNAL ;
    PORT
      LAYER M5 ;
        RECT  60.672 0 60.696 0.192 ;
    END
  END d[314]
  PIN d[315]
    DIRECTION INPUT ;
    USE SIGNAL ;
    PORT
      LAYER M5 ;
        RECT  60.864 0 60.888 0.192 ;
    END
  END d[315]
  PIN d[316]
    DIRECTION INPUT ;
    USE SIGNAL ;
    PORT
      LAYER M5 ;
        RECT  61.056 0 61.08 0.192 ;
    END
  END d[316]
  PIN d[317]
    DIRECTION INPUT ;
    USE SIGNAL ;
    PORT
      LAYER M5 ;
        RECT  61.248 0 61.272 0.192 ;
    END
  END d[317]
  PIN d[318]
    DIRECTION INPUT ;
    USE SIGNAL ;
    PORT
      LAYER M5 ;
        RECT  61.44 0 61.464 0.192 ;
    END
  END d[318]
  PIN d[319]
    DIRECTION INPUT ;
    USE SIGNAL ;
    PORT
      LAYER M5 ;
        RECT  61.632 0 61.656 0.192 ;
    END
  END d[319]
  PIN d[31]
    DIRECTION INPUT ;
    USE SIGNAL ;
    PORT
      LAYER M5 ;
        RECT  6.336 0 6.36 0.192 ;
    END
  END d[31]
  PIN d[320]
    DIRECTION INPUT ;
    USE SIGNAL ;
    PORT
      LAYER M5 ;
        RECT  61.824 0 61.848 0.192 ;
    END
  END d[320]
  PIN d[321]
    DIRECTION INPUT ;
    USE SIGNAL ;
    PORT
      LAYER M5 ;
        RECT  62.016 0 62.04 0.192 ;
    END
  END d[321]
  PIN d[322]
    DIRECTION INPUT ;
    USE SIGNAL ;
    PORT
      LAYER M5 ;
        RECT  62.208 0 62.232 0.192 ;
    END
  END d[322]
  PIN d[323]
    DIRECTION INPUT ;
    USE SIGNAL ;
    PORT
      LAYER M5 ;
        RECT  62.4 0 62.424 0.192 ;
    END
  END d[323]
  PIN d[324]
    DIRECTION INPUT ;
    USE SIGNAL ;
    PORT
      LAYER M5 ;
        RECT  62.592 0 62.616 0.192 ;
    END
  END d[324]
  PIN d[325]
    DIRECTION INPUT ;
    USE SIGNAL ;
    PORT
      LAYER M5 ;
        RECT  62.784 0 62.808 0.192 ;
    END
  END d[325]
  PIN d[326]
    DIRECTION INPUT ;
    USE SIGNAL ;
    PORT
      LAYER M5 ;
        RECT  62.976 0 63 0.192 ;
    END
  END d[326]
  PIN d[327]
    DIRECTION INPUT ;
    USE SIGNAL ;
    PORT
      LAYER M5 ;
        RECT  63.168 0 63.192 0.192 ;
    END
  END d[327]
  PIN d[328]
    DIRECTION INPUT ;
    USE SIGNAL ;
    PORT
      LAYER M5 ;
        RECT  63.36 0 63.384 0.192 ;
    END
  END d[328]
  PIN d[329]
    DIRECTION INPUT ;
    USE SIGNAL ;
    PORT
      LAYER M5 ;
        RECT  63.552 0 63.576 0.192 ;
    END
  END d[329]
  PIN d[32]
    DIRECTION INPUT ;
    USE SIGNAL ;
    PORT
      LAYER M5 ;
        RECT  6.528 0 6.552 0.192 ;
    END
  END d[32]
  PIN d[330]
    DIRECTION INPUT ;
    USE SIGNAL ;
    PORT
      LAYER M5 ;
        RECT  63.744 0 63.768 0.192 ;
    END
  END d[330]
  PIN d[331]
    DIRECTION INPUT ;
    USE SIGNAL ;
    PORT
      LAYER M5 ;
        RECT  63.936 0 63.96 0.192 ;
    END
  END d[331]
  PIN d[332]
    DIRECTION INPUT ;
    USE SIGNAL ;
    PORT
      LAYER M5 ;
        RECT  64.128 0 64.152 0.192 ;
    END
  END d[332]
  PIN d[333]
    DIRECTION INPUT ;
    USE SIGNAL ;
    PORT
      LAYER M5 ;
        RECT  64.32 0 64.344 0.192 ;
    END
  END d[333]
  PIN d[334]
    DIRECTION INPUT ;
    USE SIGNAL ;
    PORT
      LAYER M5 ;
        RECT  64.512 0 64.536 0.192 ;
    END
  END d[334]
  PIN d[335]
    DIRECTION INPUT ;
    USE SIGNAL ;
    PORT
      LAYER M5 ;
        RECT  64.704 0 64.728 0.192 ;
    END
  END d[335]
  PIN d[336]
    DIRECTION INPUT ;
    USE SIGNAL ;
    PORT
      LAYER M5 ;
        RECT  64.896 0 64.92 0.192 ;
    END
  END d[336]
  PIN d[337]
    DIRECTION INPUT ;
    USE SIGNAL ;
    PORT
      LAYER M5 ;
        RECT  65.088 0 65.112 0.192 ;
    END
  END d[337]
  PIN d[338]
    DIRECTION INPUT ;
    USE SIGNAL ;
    PORT
      LAYER M5 ;
        RECT  65.28 0 65.304 0.192 ;
    END
  END d[338]
  PIN d[339]
    DIRECTION INPUT ;
    USE SIGNAL ;
    PORT
      LAYER M5 ;
        RECT  65.472 0 65.496 0.192 ;
    END
  END d[339]
  PIN d[33]
    DIRECTION INPUT ;
    USE SIGNAL ;
    PORT
      LAYER M5 ;
        RECT  6.72 0 6.744 0.192 ;
    END
  END d[33]
  PIN d[340]
    DIRECTION INPUT ;
    USE SIGNAL ;
    PORT
      LAYER M5 ;
        RECT  65.664 0 65.688 0.192 ;
    END
  END d[340]
  PIN d[341]
    DIRECTION INPUT ;
    USE SIGNAL ;
    PORT
      LAYER M5 ;
        RECT  65.856 0 65.88 0.192 ;
    END
  END d[341]
  PIN d[342]
    DIRECTION INPUT ;
    USE SIGNAL ;
    PORT
      LAYER M5 ;
        RECT  66.048 0 66.072 0.192 ;
    END
  END d[342]
  PIN d[343]
    DIRECTION INPUT ;
    USE SIGNAL ;
    PORT
      LAYER M5 ;
        RECT  66.24 0 66.264 0.192 ;
    END
  END d[343]
  PIN d[344]
    DIRECTION INPUT ;
    USE SIGNAL ;
    PORT
      LAYER M5 ;
        RECT  66.432 0 66.456 0.192 ;
    END
  END d[344]
  PIN d[345]
    DIRECTION INPUT ;
    USE SIGNAL ;
    PORT
      LAYER M5 ;
        RECT  66.624 0 66.648 0.192 ;
    END
  END d[345]
  PIN d[346]
    DIRECTION INPUT ;
    USE SIGNAL ;
    PORT
      LAYER M5 ;
        RECT  66.816 0 66.84 0.192 ;
    END
  END d[346]
  PIN d[347]
    DIRECTION INPUT ;
    USE SIGNAL ;
    PORT
      LAYER M5 ;
        RECT  67.008 0 67.032 0.192 ;
    END
  END d[347]
  PIN d[348]
    DIRECTION INPUT ;
    USE SIGNAL ;
    PORT
      LAYER M5 ;
        RECT  67.2 0 67.224 0.192 ;
    END
  END d[348]
  PIN d[349]
    DIRECTION INPUT ;
    USE SIGNAL ;
    PORT
      LAYER M5 ;
        RECT  67.392 0 67.416 0.192 ;
    END
  END d[349]
  PIN d[34]
    DIRECTION INPUT ;
    USE SIGNAL ;
    PORT
      LAYER M5 ;
        RECT  6.912 0 6.936 0.192 ;
    END
  END d[34]
  PIN d[350]
    DIRECTION INPUT ;
    USE SIGNAL ;
    PORT
      LAYER M5 ;
        RECT  67.584 0 67.608 0.192 ;
    END
  END d[350]
  PIN d[351]
    DIRECTION INPUT ;
    USE SIGNAL ;
    PORT
      LAYER M5 ;
        RECT  67.776 0 67.8 0.192 ;
    END
  END d[351]
  PIN d[352]
    DIRECTION INPUT ;
    USE SIGNAL ;
    PORT
      LAYER M5 ;
        RECT  67.968 0 67.992 0.192 ;
    END
  END d[352]
  PIN d[353]
    DIRECTION INPUT ;
    USE SIGNAL ;
    PORT
      LAYER M5 ;
        RECT  68.16 0 68.184 0.192 ;
    END
  END d[353]
  PIN d[354]
    DIRECTION INPUT ;
    USE SIGNAL ;
    PORT
      LAYER M5 ;
        RECT  68.352 0 68.376 0.192 ;
    END
  END d[354]
  PIN d[355]
    DIRECTION INPUT ;
    USE SIGNAL ;
    PORT
      LAYER M5 ;
        RECT  68.544 0 68.568 0.192 ;
    END
  END d[355]
  PIN d[356]
    DIRECTION INPUT ;
    USE SIGNAL ;
    PORT
      LAYER M5 ;
        RECT  68.736 0 68.76 0.192 ;
    END
  END d[356]
  PIN d[357]
    DIRECTION INPUT ;
    USE SIGNAL ;
    PORT
      LAYER M5 ;
        RECT  68.928 0 68.952 0.192 ;
    END
  END d[357]
  PIN d[358]
    DIRECTION INPUT ;
    USE SIGNAL ;
    PORT
      LAYER M5 ;
        RECT  69.12 0 69.144 0.192 ;
    END
  END d[358]
  PIN d[359]
    DIRECTION INPUT ;
    USE SIGNAL ;
    PORT
      LAYER M5 ;
        RECT  69.312 0 69.336 0.192 ;
    END
  END d[359]
  PIN d[35]
    DIRECTION INPUT ;
    USE SIGNAL ;
    PORT
      LAYER M5 ;
        RECT  7.104 0 7.128 0.192 ;
    END
  END d[35]
  PIN d[360]
    DIRECTION INPUT ;
    USE SIGNAL ;
    PORT
      LAYER M5 ;
        RECT  69.504 0 69.528 0.192 ;
    END
  END d[360]
  PIN d[361]
    DIRECTION INPUT ;
    USE SIGNAL ;
    PORT
      LAYER M5 ;
        RECT  69.696 0 69.72 0.192 ;
    END
  END d[361]
  PIN d[362]
    DIRECTION INPUT ;
    USE SIGNAL ;
    PORT
      LAYER M5 ;
        RECT  69.888 0 69.912 0.192 ;
    END
  END d[362]
  PIN d[363]
    DIRECTION INPUT ;
    USE SIGNAL ;
    PORT
      LAYER M5 ;
        RECT  70.08 0 70.104 0.192 ;
    END
  END d[363]
  PIN d[364]
    DIRECTION INPUT ;
    USE SIGNAL ;
    PORT
      LAYER M5 ;
        RECT  70.272 0 70.296 0.192 ;
    END
  END d[364]
  PIN d[365]
    DIRECTION INPUT ;
    USE SIGNAL ;
    PORT
      LAYER M5 ;
        RECT  70.464 0 70.488 0.192 ;
    END
  END d[365]
  PIN d[366]
    DIRECTION INPUT ;
    USE SIGNAL ;
    PORT
      LAYER M5 ;
        RECT  70.656 0 70.68 0.192 ;
    END
  END d[366]
  PIN d[367]
    DIRECTION INPUT ;
    USE SIGNAL ;
    PORT
      LAYER M5 ;
        RECT  70.848 0 70.872 0.192 ;
    END
  END d[367]
  PIN d[368]
    DIRECTION INPUT ;
    USE SIGNAL ;
    PORT
      LAYER M5 ;
        RECT  71.04 0 71.064 0.192 ;
    END
  END d[368]
  PIN d[369]
    DIRECTION INPUT ;
    USE SIGNAL ;
    PORT
      LAYER M5 ;
        RECT  71.232 0 71.256 0.192 ;
    END
  END d[369]
  PIN d[36]
    DIRECTION INPUT ;
    USE SIGNAL ;
    PORT
      LAYER M5 ;
        RECT  7.296 0 7.32 0.192 ;
    END
  END d[36]
  PIN d[370]
    DIRECTION INPUT ;
    USE SIGNAL ;
    PORT
      LAYER M5 ;
        RECT  71.424 0 71.448 0.192 ;
    END
  END d[370]
  PIN d[371]
    DIRECTION INPUT ;
    USE SIGNAL ;
    PORT
      LAYER M5 ;
        RECT  71.616 0 71.64 0.192 ;
    END
  END d[371]
  PIN d[372]
    DIRECTION INPUT ;
    USE SIGNAL ;
    PORT
      LAYER M5 ;
        RECT  71.808 0 71.832 0.192 ;
    END
  END d[372]
  PIN d[373]
    DIRECTION INPUT ;
    USE SIGNAL ;
    PORT
      LAYER M5 ;
        RECT  72 0 72.024 0.192 ;
    END
  END d[373]
  PIN d[374]
    DIRECTION INPUT ;
    USE SIGNAL ;
    PORT
      LAYER M5 ;
        RECT  72.192 0 72.216 0.192 ;
    END
  END d[374]
  PIN d[375]
    DIRECTION INPUT ;
    USE SIGNAL ;
    PORT
      LAYER M5 ;
        RECT  72.384 0 72.408 0.192 ;
    END
  END d[375]
  PIN d[376]
    DIRECTION INPUT ;
    USE SIGNAL ;
    PORT
      LAYER M5 ;
        RECT  72.576 0 72.6 0.192 ;
    END
  END d[376]
  PIN d[377]
    DIRECTION INPUT ;
    USE SIGNAL ;
    PORT
      LAYER M5 ;
        RECT  72.768 0 72.792 0.192 ;
    END
  END d[377]
  PIN d[378]
    DIRECTION INPUT ;
    USE SIGNAL ;
    PORT
      LAYER M5 ;
        RECT  72.96 0 72.984 0.192 ;
    END
  END d[378]
  PIN d[379]
    DIRECTION INPUT ;
    USE SIGNAL ;
    PORT
      LAYER M5 ;
        RECT  73.152 0 73.176 0.192 ;
    END
  END d[379]
  PIN d[37]
    DIRECTION INPUT ;
    USE SIGNAL ;
    PORT
      LAYER M5 ;
        RECT  7.488 0 7.512 0.192 ;
    END
  END d[37]
  PIN d[380]
    DIRECTION INPUT ;
    USE SIGNAL ;
    PORT
      LAYER M5 ;
        RECT  73.344 0 73.368 0.192 ;
    END
  END d[380]
  PIN d[381]
    DIRECTION INPUT ;
    USE SIGNAL ;
    PORT
      LAYER M5 ;
        RECT  73.536 0 73.56 0.192 ;
    END
  END d[381]
  PIN d[382]
    DIRECTION INPUT ;
    USE SIGNAL ;
    PORT
      LAYER M5 ;
        RECT  73.728 0 73.752 0.192 ;
    END
  END d[382]
  PIN d[383]
    DIRECTION INPUT ;
    USE SIGNAL ;
    PORT
      LAYER M5 ;
        RECT  73.92 0 73.944 0.192 ;
    END
  END d[383]
  PIN d[384]
    DIRECTION INPUT ;
    USE SIGNAL ;
    PORT
      LAYER M5 ;
        RECT  74.112 0 74.136 0.192 ;
    END
  END d[384]
  PIN d[385]
    DIRECTION INPUT ;
    USE SIGNAL ;
    PORT
      LAYER M5 ;
        RECT  74.304 0 74.328 0.192 ;
    END
  END d[385]
  PIN d[386]
    DIRECTION INPUT ;
    USE SIGNAL ;
    PORT
      LAYER M5 ;
        RECT  74.496 0 74.52 0.192 ;
    END
  END d[386]
  PIN d[387]
    DIRECTION INPUT ;
    USE SIGNAL ;
    PORT
      LAYER M5 ;
        RECT  74.688 0 74.712 0.192 ;
    END
  END d[387]
  PIN d[388]
    DIRECTION INPUT ;
    USE SIGNAL ;
    PORT
      LAYER M5 ;
        RECT  74.88 0 74.904 0.192 ;
    END
  END d[388]
  PIN d[389]
    DIRECTION INPUT ;
    USE SIGNAL ;
    PORT
      LAYER M5 ;
        RECT  75.072 0 75.096 0.192 ;
    END
  END d[389]
  PIN d[38]
    DIRECTION INPUT ;
    USE SIGNAL ;
    PORT
      LAYER M5 ;
        RECT  7.68 0 7.704 0.192 ;
    END
  END d[38]
  PIN d[390]
    DIRECTION INPUT ;
    USE SIGNAL ;
    PORT
      LAYER M5 ;
        RECT  75.264 0 75.288 0.192 ;
    END
  END d[390]
  PIN d[391]
    DIRECTION INPUT ;
    USE SIGNAL ;
    PORT
      LAYER M5 ;
        RECT  75.456 0 75.48 0.192 ;
    END
  END d[391]
  PIN d[392]
    DIRECTION INPUT ;
    USE SIGNAL ;
    PORT
      LAYER M5 ;
        RECT  75.648 0 75.672 0.192 ;
    END
  END d[392]
  PIN d[393]
    DIRECTION INPUT ;
    USE SIGNAL ;
    PORT
      LAYER M5 ;
        RECT  75.84 0 75.864 0.192 ;
    END
  END d[393]
  PIN d[394]
    DIRECTION INPUT ;
    USE SIGNAL ;
    PORT
      LAYER M5 ;
        RECT  76.032 0 76.056 0.192 ;
    END
  END d[394]
  PIN d[395]
    DIRECTION INPUT ;
    USE SIGNAL ;
    PORT
      LAYER M5 ;
        RECT  76.224 0 76.248 0.192 ;
    END
  END d[395]
  PIN d[396]
    DIRECTION INPUT ;
    USE SIGNAL ;
    PORT
      LAYER M5 ;
        RECT  76.416 0 76.44 0.192 ;
    END
  END d[396]
  PIN d[397]
    DIRECTION INPUT ;
    USE SIGNAL ;
    PORT
      LAYER M5 ;
        RECT  76.608 0 76.632 0.192 ;
    END
  END d[397]
  PIN d[398]
    DIRECTION INPUT ;
    USE SIGNAL ;
    PORT
      LAYER M5 ;
        RECT  76.8 0 76.824 0.192 ;
    END
  END d[398]
  PIN d[399]
    DIRECTION INPUT ;
    USE SIGNAL ;
    PORT
      LAYER M5 ;
        RECT  76.992 0 77.016 0.192 ;
    END
  END d[399]
  PIN d[39]
    DIRECTION INPUT ;
    USE SIGNAL ;
    PORT
      LAYER M5 ;
        RECT  7.872 0 7.896 0.192 ;
    END
  END d[39]
  PIN d[3]
    DIRECTION INPUT ;
    USE SIGNAL ;
    PORT
      LAYER M5 ;
        RECT  0.96 0 0.984 0.192 ;
    END
  END d[3]
  PIN d[400]
    DIRECTION INPUT ;
    USE SIGNAL ;
    PORT
      LAYER M5 ;
        RECT  77.184 0 77.208 0.192 ;
    END
  END d[400]
  PIN d[401]
    DIRECTION INPUT ;
    USE SIGNAL ;
    PORT
      LAYER M5 ;
        RECT  77.376 0 77.4 0.192 ;
    END
  END d[401]
  PIN d[402]
    DIRECTION INPUT ;
    USE SIGNAL ;
    PORT
      LAYER M5 ;
        RECT  77.568 0 77.592 0.192 ;
    END
  END d[402]
  PIN d[403]
    DIRECTION INPUT ;
    USE SIGNAL ;
    PORT
      LAYER M5 ;
        RECT  77.76 0 77.784 0.192 ;
    END
  END d[403]
  PIN d[404]
    DIRECTION INPUT ;
    USE SIGNAL ;
    PORT
      LAYER M5 ;
        RECT  77.952 0 77.976 0.192 ;
    END
  END d[404]
  PIN d[405]
    DIRECTION INPUT ;
    USE SIGNAL ;
    PORT
      LAYER M5 ;
        RECT  78.144 0 78.168 0.192 ;
    END
  END d[405]
  PIN d[406]
    DIRECTION INPUT ;
    USE SIGNAL ;
    PORT
      LAYER M5 ;
        RECT  78.336 0 78.36 0.192 ;
    END
  END d[406]
  PIN d[407]
    DIRECTION INPUT ;
    USE SIGNAL ;
    PORT
      LAYER M5 ;
        RECT  78.528 0 78.552 0.192 ;
    END
  END d[407]
  PIN d[408]
    DIRECTION INPUT ;
    USE SIGNAL ;
    PORT
      LAYER M5 ;
        RECT  78.72 0 78.744 0.192 ;
    END
  END d[408]
  PIN d[409]
    DIRECTION INPUT ;
    USE SIGNAL ;
    PORT
      LAYER M5 ;
        RECT  78.912 0 78.936 0.192 ;
    END
  END d[409]
  PIN d[40]
    DIRECTION INPUT ;
    USE SIGNAL ;
    PORT
      LAYER M5 ;
        RECT  8.064 0 8.088 0.192 ;
    END
  END d[40]
  PIN d[410]
    DIRECTION INPUT ;
    USE SIGNAL ;
    PORT
      LAYER M5 ;
        RECT  79.104 0 79.128 0.192 ;
    END
  END d[410]
  PIN d[411]
    DIRECTION INPUT ;
    USE SIGNAL ;
    PORT
      LAYER M5 ;
        RECT  79.296 0 79.32 0.192 ;
    END
  END d[411]
  PIN d[412]
    DIRECTION INPUT ;
    USE SIGNAL ;
    PORT
      LAYER M5 ;
        RECT  79.488 0 79.512 0.192 ;
    END
  END d[412]
  PIN d[413]
    DIRECTION INPUT ;
    USE SIGNAL ;
    PORT
      LAYER M5 ;
        RECT  79.68 0 79.704 0.192 ;
    END
  END d[413]
  PIN d[414]
    DIRECTION INPUT ;
    USE SIGNAL ;
    PORT
      LAYER M5 ;
        RECT  79.872 0 79.896 0.192 ;
    END
  END d[414]
  PIN d[415]
    DIRECTION INPUT ;
    USE SIGNAL ;
    PORT
      LAYER M5 ;
        RECT  80.064 0 80.088 0.192 ;
    END
  END d[415]
  PIN d[416]
    DIRECTION INPUT ;
    USE SIGNAL ;
    PORT
      LAYER M5 ;
        RECT  80.256 0 80.28 0.192 ;
    END
  END d[416]
  PIN d[417]
    DIRECTION INPUT ;
    USE SIGNAL ;
    PORT
      LAYER M5 ;
        RECT  80.448 0 80.472 0.192 ;
    END
  END d[417]
  PIN d[418]
    DIRECTION INPUT ;
    USE SIGNAL ;
    PORT
      LAYER M5 ;
        RECT  80.64 0 80.664 0.192 ;
    END
  END d[418]
  PIN d[419]
    DIRECTION INPUT ;
    USE SIGNAL ;
    PORT
      LAYER M5 ;
        RECT  80.832 0 80.856 0.192 ;
    END
  END d[419]
  PIN d[41]
    DIRECTION INPUT ;
    USE SIGNAL ;
    PORT
      LAYER M5 ;
        RECT  8.256 0 8.28 0.192 ;
    END
  END d[41]
  PIN d[420]
    DIRECTION INPUT ;
    USE SIGNAL ;
    PORT
      LAYER M5 ;
        RECT  81.024 0 81.048 0.192 ;
    END
  END d[420]
  PIN d[421]
    DIRECTION INPUT ;
    USE SIGNAL ;
    PORT
      LAYER M5 ;
        RECT  81.216 0 81.24 0.192 ;
    END
  END d[421]
  PIN d[422]
    DIRECTION INPUT ;
    USE SIGNAL ;
    PORT
      LAYER M5 ;
        RECT  81.408 0 81.432 0.192 ;
    END
  END d[422]
  PIN d[423]
    DIRECTION INPUT ;
    USE SIGNAL ;
    PORT
      LAYER M5 ;
        RECT  81.6 0 81.624 0.192 ;
    END
  END d[423]
  PIN d[424]
    DIRECTION INPUT ;
    USE SIGNAL ;
    PORT
      LAYER M5 ;
        RECT  81.792 0 81.816 0.192 ;
    END
  END d[424]
  PIN d[425]
    DIRECTION INPUT ;
    USE SIGNAL ;
    PORT
      LAYER M5 ;
        RECT  81.984 0 82.008 0.192 ;
    END
  END d[425]
  PIN d[426]
    DIRECTION INPUT ;
    USE SIGNAL ;
    PORT
      LAYER M5 ;
        RECT  82.176 0 82.2 0.192 ;
    END
  END d[426]
  PIN d[427]
    DIRECTION INPUT ;
    USE SIGNAL ;
    PORT
      LAYER M5 ;
        RECT  82.368 0 82.392 0.192 ;
    END
  END d[427]
  PIN d[428]
    DIRECTION INPUT ;
    USE SIGNAL ;
    PORT
      LAYER M5 ;
        RECT  82.56 0 82.584 0.192 ;
    END
  END d[428]
  PIN d[429]
    DIRECTION INPUT ;
    USE SIGNAL ;
    PORT
      LAYER M5 ;
        RECT  82.752 0 82.776 0.192 ;
    END
  END d[429]
  PIN d[42]
    DIRECTION INPUT ;
    USE SIGNAL ;
    PORT
      LAYER M5 ;
        RECT  8.448 0 8.472 0.192 ;
    END
  END d[42]
  PIN d[430]
    DIRECTION INPUT ;
    USE SIGNAL ;
    PORT
      LAYER M5 ;
        RECT  82.944 0 82.968 0.192 ;
    END
  END d[430]
  PIN d[431]
    DIRECTION INPUT ;
    USE SIGNAL ;
    PORT
      LAYER M5 ;
        RECT  83.136 0 83.16 0.192 ;
    END
  END d[431]
  PIN d[432]
    DIRECTION INPUT ;
    USE SIGNAL ;
    PORT
      LAYER M5 ;
        RECT  83.328 0 83.352 0.192 ;
    END
  END d[432]
  PIN d[433]
    DIRECTION INPUT ;
    USE SIGNAL ;
    PORT
      LAYER M5 ;
        RECT  83.52 0 83.544 0.192 ;
    END
  END d[433]
  PIN d[434]
    DIRECTION INPUT ;
    USE SIGNAL ;
    PORT
      LAYER M5 ;
        RECT  83.712 0 83.736 0.192 ;
    END
  END d[434]
  PIN d[435]
    DIRECTION INPUT ;
    USE SIGNAL ;
    PORT
      LAYER M5 ;
        RECT  83.904 0 83.928 0.192 ;
    END
  END d[435]
  PIN d[436]
    DIRECTION INPUT ;
    USE SIGNAL ;
    PORT
      LAYER M5 ;
        RECT  84.096 0 84.12 0.192 ;
    END
  END d[436]
  PIN d[437]
    DIRECTION INPUT ;
    USE SIGNAL ;
    PORT
      LAYER M5 ;
        RECT  84.288 0 84.312 0.192 ;
    END
  END d[437]
  PIN d[438]
    DIRECTION INPUT ;
    USE SIGNAL ;
    PORT
      LAYER M5 ;
        RECT  84.48 0 84.504 0.192 ;
    END
  END d[438]
  PIN d[439]
    DIRECTION INPUT ;
    USE SIGNAL ;
    PORT
      LAYER M5 ;
        RECT  84.672 0 84.696 0.192 ;
    END
  END d[439]
  PIN d[43]
    DIRECTION INPUT ;
    USE SIGNAL ;
    PORT
      LAYER M5 ;
        RECT  8.64 0 8.664 0.192 ;
    END
  END d[43]
  PIN d[440]
    DIRECTION INPUT ;
    USE SIGNAL ;
    PORT
      LAYER M5 ;
        RECT  84.864 0 84.888 0.192 ;
    END
  END d[440]
  PIN d[441]
    DIRECTION INPUT ;
    USE SIGNAL ;
    PORT
      LAYER M5 ;
        RECT  85.056 0 85.08 0.192 ;
    END
  END d[441]
  PIN d[442]
    DIRECTION INPUT ;
    USE SIGNAL ;
    PORT
      LAYER M5 ;
        RECT  85.248 0 85.272 0.192 ;
    END
  END d[442]
  PIN d[443]
    DIRECTION INPUT ;
    USE SIGNAL ;
    PORT
      LAYER M5 ;
        RECT  85.44 0 85.464 0.192 ;
    END
  END d[443]
  PIN d[444]
    DIRECTION INPUT ;
    USE SIGNAL ;
    PORT
      LAYER M5 ;
        RECT  85.632 0 85.656 0.192 ;
    END
  END d[444]
  PIN d[445]
    DIRECTION INPUT ;
    USE SIGNAL ;
    PORT
      LAYER M5 ;
        RECT  85.824 0 85.848 0.192 ;
    END
  END d[445]
  PIN d[446]
    DIRECTION INPUT ;
    USE SIGNAL ;
    PORT
      LAYER M5 ;
        RECT  86.016 0 86.04 0.192 ;
    END
  END d[446]
  PIN d[447]
    DIRECTION INPUT ;
    USE SIGNAL ;
    PORT
      LAYER M5 ;
        RECT  86.208 0 86.232 0.192 ;
    END
  END d[447]
  PIN d[448]
    DIRECTION INPUT ;
    USE SIGNAL ;
    PORT
      LAYER M5 ;
        RECT  86.4 0 86.424 0.192 ;
    END
  END d[448]
  PIN d[449]
    DIRECTION INPUT ;
    USE SIGNAL ;
    PORT
      LAYER M5 ;
        RECT  86.592 0 86.616 0.192 ;
    END
  END d[449]
  PIN d[44]
    DIRECTION INPUT ;
    USE SIGNAL ;
    PORT
      LAYER M5 ;
        RECT  8.832 0 8.856 0.192 ;
    END
  END d[44]
  PIN d[450]
    DIRECTION INPUT ;
    USE SIGNAL ;
    PORT
      LAYER M5 ;
        RECT  86.784 0 86.808 0.192 ;
    END
  END d[450]
  PIN d[451]
    DIRECTION INPUT ;
    USE SIGNAL ;
    PORT
      LAYER M5 ;
        RECT  86.976 0 87 0.192 ;
    END
  END d[451]
  PIN d[452]
    DIRECTION INPUT ;
    USE SIGNAL ;
    PORT
      LAYER M5 ;
        RECT  87.168 0 87.192 0.192 ;
    END
  END d[452]
  PIN d[453]
    DIRECTION INPUT ;
    USE SIGNAL ;
    PORT
      LAYER M5 ;
        RECT  87.36 0 87.384 0.192 ;
    END
  END d[453]
  PIN d[454]
    DIRECTION INPUT ;
    USE SIGNAL ;
    PORT
      LAYER M5 ;
        RECT  87.552 0 87.576 0.192 ;
    END
  END d[454]
  PIN d[455]
    DIRECTION INPUT ;
    USE SIGNAL ;
    PORT
      LAYER M5 ;
        RECT  87.744 0 87.768 0.192 ;
    END
  END d[455]
  PIN d[456]
    DIRECTION INPUT ;
    USE SIGNAL ;
    PORT
      LAYER M5 ;
        RECT  87.936 0 87.96 0.192 ;
    END
  END d[456]
  PIN d[457]
    DIRECTION INPUT ;
    USE SIGNAL ;
    PORT
      LAYER M5 ;
        RECT  88.128 0 88.152 0.192 ;
    END
  END d[457]
  PIN d[458]
    DIRECTION INPUT ;
    USE SIGNAL ;
    PORT
      LAYER M5 ;
        RECT  88.32 0 88.344 0.192 ;
    END
  END d[458]
  PIN d[459]
    DIRECTION INPUT ;
    USE SIGNAL ;
    PORT
      LAYER M5 ;
        RECT  88.512 0 88.536 0.192 ;
    END
  END d[459]
  PIN d[45]
    DIRECTION INPUT ;
    USE SIGNAL ;
    PORT
      LAYER M5 ;
        RECT  9.024 0 9.048 0.192 ;
    END
  END d[45]
  PIN d[460]
    DIRECTION INPUT ;
    USE SIGNAL ;
    PORT
      LAYER M5 ;
        RECT  88.704 0 88.728 0.192 ;
    END
  END d[460]
  PIN d[461]
    DIRECTION INPUT ;
    USE SIGNAL ;
    PORT
      LAYER M5 ;
        RECT  88.896 0 88.92 0.192 ;
    END
  END d[461]
  PIN d[462]
    DIRECTION INPUT ;
    USE SIGNAL ;
    PORT
      LAYER M5 ;
        RECT  89.088 0 89.112 0.192 ;
    END
  END d[462]
  PIN d[463]
    DIRECTION INPUT ;
    USE SIGNAL ;
    PORT
      LAYER M5 ;
        RECT  89.28 0 89.304 0.192 ;
    END
  END d[463]
  PIN d[464]
    DIRECTION INPUT ;
    USE SIGNAL ;
    PORT
      LAYER M5 ;
        RECT  89.472 0 89.496 0.192 ;
    END
  END d[464]
  PIN d[465]
    DIRECTION INPUT ;
    USE SIGNAL ;
    PORT
      LAYER M5 ;
        RECT  89.664 0 89.688 0.192 ;
    END
  END d[465]
  PIN d[466]
    DIRECTION INPUT ;
    USE SIGNAL ;
    PORT
      LAYER M5 ;
        RECT  89.856 0 89.88 0.192 ;
    END
  END d[466]
  PIN d[467]
    DIRECTION INPUT ;
    USE SIGNAL ;
    PORT
      LAYER M5 ;
        RECT  90.048 0 90.072 0.192 ;
    END
  END d[467]
  PIN d[468]
    DIRECTION INPUT ;
    USE SIGNAL ;
    PORT
      LAYER M5 ;
        RECT  90.24 0 90.264 0.192 ;
    END
  END d[468]
  PIN d[469]
    DIRECTION INPUT ;
    USE SIGNAL ;
    PORT
      LAYER M5 ;
        RECT  90.432 0 90.456 0.192 ;
    END
  END d[469]
  PIN d[46]
    DIRECTION INPUT ;
    USE SIGNAL ;
    PORT
      LAYER M5 ;
        RECT  9.216 0 9.24 0.192 ;
    END
  END d[46]
  PIN d[470]
    DIRECTION INPUT ;
    USE SIGNAL ;
    PORT
      LAYER M5 ;
        RECT  90.624 0 90.648 0.192 ;
    END
  END d[470]
  PIN d[471]
    DIRECTION INPUT ;
    USE SIGNAL ;
    PORT
      LAYER M5 ;
        RECT  90.816 0 90.84 0.192 ;
    END
  END d[471]
  PIN d[472]
    DIRECTION INPUT ;
    USE SIGNAL ;
    PORT
      LAYER M5 ;
        RECT  91.008 0 91.032 0.192 ;
    END
  END d[472]
  PIN d[473]
    DIRECTION INPUT ;
    USE SIGNAL ;
    PORT
      LAYER M5 ;
        RECT  91.2 0 91.224 0.192 ;
    END
  END d[473]
  PIN d[474]
    DIRECTION INPUT ;
    USE SIGNAL ;
    PORT
      LAYER M5 ;
        RECT  91.392 0 91.416 0.192 ;
    END
  END d[474]
  PIN d[475]
    DIRECTION INPUT ;
    USE SIGNAL ;
    PORT
      LAYER M5 ;
        RECT  91.584 0 91.608 0.192 ;
    END
  END d[475]
  PIN d[476]
    DIRECTION INPUT ;
    USE SIGNAL ;
    PORT
      LAYER M5 ;
        RECT  91.776 0 91.8 0.192 ;
    END
  END d[476]
  PIN d[477]
    DIRECTION INPUT ;
    USE SIGNAL ;
    PORT
      LAYER M5 ;
        RECT  91.968 0 91.992 0.192 ;
    END
  END d[477]
  PIN d[478]
    DIRECTION INPUT ;
    USE SIGNAL ;
    PORT
      LAYER M5 ;
        RECT  92.16 0 92.184 0.192 ;
    END
  END d[478]
  PIN d[479]
    DIRECTION INPUT ;
    USE SIGNAL ;
    PORT
      LAYER M5 ;
        RECT  92.352 0 92.376 0.192 ;
    END
  END d[479]
  PIN d[47]
    DIRECTION INPUT ;
    USE SIGNAL ;
    PORT
      LAYER M5 ;
        RECT  9.408 0 9.432 0.192 ;
    END
  END d[47]
  PIN d[480]
    DIRECTION INPUT ;
    USE SIGNAL ;
    PORT
      LAYER M5 ;
        RECT  92.544 0 92.568 0.192 ;
    END
  END d[480]
  PIN d[481]
    DIRECTION INPUT ;
    USE SIGNAL ;
    PORT
      LAYER M5 ;
        RECT  92.736 0 92.76 0.192 ;
    END
  END d[481]
  PIN d[482]
    DIRECTION INPUT ;
    USE SIGNAL ;
    PORT
      LAYER M5 ;
        RECT  92.928 0 92.952 0.192 ;
    END
  END d[482]
  PIN d[483]
    DIRECTION INPUT ;
    USE SIGNAL ;
    PORT
      LAYER M5 ;
        RECT  93.12 0 93.144 0.192 ;
    END
  END d[483]
  PIN d[484]
    DIRECTION INPUT ;
    USE SIGNAL ;
    PORT
      LAYER M5 ;
        RECT  93.312 0 93.336 0.192 ;
    END
  END d[484]
  PIN d[485]
    DIRECTION INPUT ;
    USE SIGNAL ;
    PORT
      LAYER M5 ;
        RECT  93.504 0 93.528 0.192 ;
    END
  END d[485]
  PIN d[486]
    DIRECTION INPUT ;
    USE SIGNAL ;
    PORT
      LAYER M5 ;
        RECT  93.696 0 93.72 0.192 ;
    END
  END d[486]
  PIN d[487]
    DIRECTION INPUT ;
    USE SIGNAL ;
    PORT
      LAYER M5 ;
        RECT  93.888 0 93.912 0.192 ;
    END
  END d[487]
  PIN d[488]
    DIRECTION INPUT ;
    USE SIGNAL ;
    PORT
      LAYER M5 ;
        RECT  94.08 0 94.104 0.192 ;
    END
  END d[488]
  PIN d[489]
    DIRECTION INPUT ;
    USE SIGNAL ;
    PORT
      LAYER M5 ;
        RECT  94.272 0 94.296 0.192 ;
    END
  END d[489]
  PIN d[48]
    DIRECTION INPUT ;
    USE SIGNAL ;
    PORT
      LAYER M5 ;
        RECT  9.6 0 9.624 0.192 ;
    END
  END d[48]
  PIN d[490]
    DIRECTION INPUT ;
    USE SIGNAL ;
    PORT
      LAYER M5 ;
        RECT  94.464 0 94.488 0.192 ;
    END
  END d[490]
  PIN d[491]
    DIRECTION INPUT ;
    USE SIGNAL ;
    PORT
      LAYER M5 ;
        RECT  94.656 0 94.68 0.192 ;
    END
  END d[491]
  PIN d[492]
    DIRECTION INPUT ;
    USE SIGNAL ;
    PORT
      LAYER M5 ;
        RECT  94.848 0 94.872 0.192 ;
    END
  END d[492]
  PIN d[493]
    DIRECTION INPUT ;
    USE SIGNAL ;
    PORT
      LAYER M5 ;
        RECT  95.04 0 95.064 0.192 ;
    END
  END d[493]
  PIN d[494]
    DIRECTION INPUT ;
    USE SIGNAL ;
    PORT
      LAYER M5 ;
        RECT  95.232 0 95.256 0.192 ;
    END
  END d[494]
  PIN d[495]
    DIRECTION INPUT ;
    USE SIGNAL ;
    PORT
      LAYER M5 ;
        RECT  95.424 0 95.448 0.192 ;
    END
  END d[495]
  PIN d[496]
    DIRECTION INPUT ;
    USE SIGNAL ;
    PORT
      LAYER M5 ;
        RECT  95.616 0 95.64 0.192 ;
    END
  END d[496]
  PIN d[497]
    DIRECTION INPUT ;
    USE SIGNAL ;
    PORT
      LAYER M5 ;
        RECT  95.808 0 95.832 0.192 ;
    END
  END d[497]
  PIN d[498]
    DIRECTION INPUT ;
    USE SIGNAL ;
    PORT
      LAYER M5 ;
        RECT  96 0 96.024 0.192 ;
    END
  END d[498]
  PIN d[499]
    DIRECTION INPUT ;
    USE SIGNAL ;
    PORT
      LAYER M5 ;
        RECT  96.192 0 96.216 0.192 ;
    END
  END d[499]
  PIN d[49]
    DIRECTION INPUT ;
    USE SIGNAL ;
    PORT
      LAYER M5 ;
        RECT  9.792 0 9.816 0.192 ;
    END
  END d[49]
  PIN d[4]
    DIRECTION INPUT ;
    USE SIGNAL ;
    PORT
      LAYER M5 ;
        RECT  1.152 0 1.176 0.192 ;
    END
  END d[4]
  PIN d[500]
    DIRECTION INPUT ;
    USE SIGNAL ;
    PORT
      LAYER M5 ;
        RECT  96.384 0 96.408 0.192 ;
    END
  END d[500]
  PIN d[501]
    DIRECTION INPUT ;
    USE SIGNAL ;
    PORT
      LAYER M5 ;
        RECT  96.576 0 96.6 0.192 ;
    END
  END d[501]
  PIN d[502]
    DIRECTION INPUT ;
    USE SIGNAL ;
    PORT
      LAYER M5 ;
        RECT  96.768 0 96.792 0.192 ;
    END
  END d[502]
  PIN d[503]
    DIRECTION INPUT ;
    USE SIGNAL ;
    PORT
      LAYER M5 ;
        RECT  96.96 0 96.984 0.192 ;
    END
  END d[503]
  PIN d[504]
    DIRECTION INPUT ;
    USE SIGNAL ;
    PORT
      LAYER M5 ;
        RECT  97.152 0 97.176 0.192 ;
    END
  END d[504]
  PIN d[505]
    DIRECTION INPUT ;
    USE SIGNAL ;
    PORT
      LAYER M5 ;
        RECT  97.344 0 97.368 0.192 ;
    END
  END d[505]
  PIN d[506]
    DIRECTION INPUT ;
    USE SIGNAL ;
    PORT
      LAYER M5 ;
        RECT  97.536 0 97.56 0.192 ;
    END
  END d[506]
  PIN d[507]
    DIRECTION INPUT ;
    USE SIGNAL ;
    PORT
      LAYER M5 ;
        RECT  97.728 0 97.752 0.192 ;
    END
  END d[507]
  PIN d[508]
    DIRECTION INPUT ;
    USE SIGNAL ;
    PORT
      LAYER M5 ;
        RECT  97.92 0 97.944 0.192 ;
    END
  END d[508]
  PIN d[509]
    DIRECTION INPUT ;
    USE SIGNAL ;
    PORT
      LAYER M5 ;
        RECT  98.112 0 98.136 0.192 ;
    END
  END d[509]
  PIN d[50]
    DIRECTION INPUT ;
    USE SIGNAL ;
    PORT
      LAYER M5 ;
        RECT  9.984 0 10.008 0.192 ;
    END
  END d[50]
  PIN d[510]
    DIRECTION INPUT ;
    USE SIGNAL ;
    PORT
      LAYER M5 ;
        RECT  98.304 0 98.328 0.192 ;
    END
  END d[510]
  PIN d[511]
    DIRECTION INPUT ;
    USE SIGNAL ;
    PORT
      LAYER M5 ;
        RECT  98.496 0 98.52 0.192 ;
    END
  END d[511]
  PIN d[512]
    DIRECTION INPUT ;
    USE SIGNAL ;
    PORT
      LAYER M5 ;
        RECT  98.688 0 98.712 0.192 ;
    END
  END d[512]
  PIN d[513]
    DIRECTION INPUT ;
    USE SIGNAL ;
    PORT
      LAYER M5 ;
        RECT  98.88 0 98.904 0.192 ;
    END
  END d[513]
  PIN d[514]
    DIRECTION INPUT ;
    USE SIGNAL ;
    PORT
      LAYER M5 ;
        RECT  99.072 0 99.096 0.192 ;
    END
  END d[514]
  PIN d[515]
    DIRECTION INPUT ;
    USE SIGNAL ;
    PORT
      LAYER M5 ;
        RECT  99.264 0 99.288 0.192 ;
    END
  END d[515]
  PIN d[516]
    DIRECTION INPUT ;
    USE SIGNAL ;
    PORT
      LAYER M5 ;
        RECT  99.456 0 99.48 0.192 ;
    END
  END d[516]
  PIN d[517]
    DIRECTION INPUT ;
    USE SIGNAL ;
    PORT
      LAYER M5 ;
        RECT  99.648 0 99.672 0.192 ;
    END
  END d[517]
  PIN d[518]
    DIRECTION INPUT ;
    USE SIGNAL ;
    PORT
      LAYER M5 ;
        RECT  99.84 0 99.864 0.192 ;
    END
  END d[518]
  PIN d[519]
    DIRECTION INPUT ;
    USE SIGNAL ;
    PORT
      LAYER M5 ;
        RECT  100.032 0 100.056 0.192 ;
    END
  END d[519]
  PIN d[51]
    DIRECTION INPUT ;
    USE SIGNAL ;
    PORT
      LAYER M5 ;
        RECT  10.176 0 10.2 0.192 ;
    END
  END d[51]
  PIN d[520]
    DIRECTION INPUT ;
    USE SIGNAL ;
    PORT
      LAYER M5 ;
        RECT  100.224 0 100.248 0.192 ;
    END
  END d[520]
  PIN d[521]
    DIRECTION INPUT ;
    USE SIGNAL ;
    PORT
      LAYER M5 ;
        RECT  100.416 0 100.44 0.192 ;
    END
  END d[521]
  PIN d[522]
    DIRECTION INPUT ;
    USE SIGNAL ;
    PORT
      LAYER M5 ;
        RECT  100.608 0 100.632 0.192 ;
    END
  END d[522]
  PIN d[523]
    DIRECTION INPUT ;
    USE SIGNAL ;
    PORT
      LAYER M5 ;
        RECT  100.8 0 100.824 0.192 ;
    END
  END d[523]
  PIN d[524]
    DIRECTION INPUT ;
    USE SIGNAL ;
    PORT
      LAYER M5 ;
        RECT  100.992 0 101.016 0.192 ;
    END
  END d[524]
  PIN d[525]
    DIRECTION INPUT ;
    USE SIGNAL ;
    PORT
      LAYER M5 ;
        RECT  101.184 0 101.208 0.192 ;
    END
  END d[525]
  PIN d[526]
    DIRECTION INPUT ;
    USE SIGNAL ;
    PORT
      LAYER M5 ;
        RECT  101.376 0 101.4 0.192 ;
    END
  END d[526]
  PIN d[527]
    DIRECTION INPUT ;
    USE SIGNAL ;
    PORT
      LAYER M5 ;
        RECT  101.568 0 101.592 0.192 ;
    END
  END d[527]
  PIN d[528]
    DIRECTION INPUT ;
    USE SIGNAL ;
    PORT
      LAYER M5 ;
        RECT  101.76 0 101.784 0.192 ;
    END
  END d[528]
  PIN d[529]
    DIRECTION INPUT ;
    USE SIGNAL ;
    PORT
      LAYER M5 ;
        RECT  101.952 0 101.976 0.192 ;
    END
  END d[529]
  PIN d[52]
    DIRECTION INPUT ;
    USE SIGNAL ;
    PORT
      LAYER M5 ;
        RECT  10.368 0 10.392 0.192 ;
    END
  END d[52]
  PIN d[530]
    DIRECTION INPUT ;
    USE SIGNAL ;
    PORT
      LAYER M5 ;
        RECT  102.144 0 102.168 0.192 ;
    END
  END d[530]
  PIN d[531]
    DIRECTION INPUT ;
    USE SIGNAL ;
    PORT
      LAYER M5 ;
        RECT  102.336 0 102.36 0.192 ;
    END
  END d[531]
  PIN d[532]
    DIRECTION INPUT ;
    USE SIGNAL ;
    PORT
      LAYER M5 ;
        RECT  102.528 0 102.552 0.192 ;
    END
  END d[532]
  PIN d[533]
    DIRECTION INPUT ;
    USE SIGNAL ;
    PORT
      LAYER M5 ;
        RECT  102.72 0 102.744 0.192 ;
    END
  END d[533]
  PIN d[534]
    DIRECTION INPUT ;
    USE SIGNAL ;
    PORT
      LAYER M5 ;
        RECT  102.912 0 102.936 0.192 ;
    END
  END d[534]
  PIN d[535]
    DIRECTION INPUT ;
    USE SIGNAL ;
    PORT
      LAYER M5 ;
        RECT  103.104 0 103.128 0.192 ;
    END
  END d[535]
  PIN d[536]
    DIRECTION INPUT ;
    USE SIGNAL ;
    PORT
      LAYER M5 ;
        RECT  103.296 0 103.32 0.192 ;
    END
  END d[536]
  PIN d[537]
    DIRECTION INPUT ;
    USE SIGNAL ;
    PORT
      LAYER M5 ;
        RECT  103.488 0 103.512 0.192 ;
    END
  END d[537]
  PIN d[538]
    DIRECTION INPUT ;
    USE SIGNAL ;
    PORT
      LAYER M5 ;
        RECT  103.68 0 103.704 0.192 ;
    END
  END d[538]
  PIN d[539]
    DIRECTION INPUT ;
    USE SIGNAL ;
    PORT
      LAYER M5 ;
        RECT  103.872 0 103.896 0.192 ;
    END
  END d[539]
  PIN d[53]
    DIRECTION INPUT ;
    USE SIGNAL ;
    PORT
      LAYER M5 ;
        RECT  10.56 0 10.584 0.192 ;
    END
  END d[53]
  PIN d[540]
    DIRECTION INPUT ;
    USE SIGNAL ;
    PORT
      LAYER M5 ;
        RECT  104.064 0 104.088 0.192 ;
    END
  END d[540]
  PIN d[541]
    DIRECTION INPUT ;
    USE SIGNAL ;
    PORT
      LAYER M5 ;
        RECT  104.256 0 104.28 0.192 ;
    END
  END d[541]
  PIN d[542]
    DIRECTION INPUT ;
    USE SIGNAL ;
    PORT
      LAYER M5 ;
        RECT  104.448 0 104.472 0.192 ;
    END
  END d[542]
  PIN d[543]
    DIRECTION INPUT ;
    USE SIGNAL ;
    PORT
      LAYER M5 ;
        RECT  104.64 0 104.664 0.192 ;
    END
  END d[543]
  PIN d[54]
    DIRECTION INPUT ;
    USE SIGNAL ;
    PORT
      LAYER M5 ;
        RECT  10.752 0 10.776 0.192 ;
    END
  END d[54]
  PIN d[55]
    DIRECTION INPUT ;
    USE SIGNAL ;
    PORT
      LAYER M5 ;
        RECT  10.944 0 10.968 0.192 ;
    END
  END d[55]
  PIN d[56]
    DIRECTION INPUT ;
    USE SIGNAL ;
    PORT
      LAYER M5 ;
        RECT  11.136 0 11.16 0.192 ;
    END
  END d[56]
  PIN d[57]
    DIRECTION INPUT ;
    USE SIGNAL ;
    PORT
      LAYER M5 ;
        RECT  11.328 0 11.352 0.192 ;
    END
  END d[57]
  PIN d[58]
    DIRECTION INPUT ;
    USE SIGNAL ;
    PORT
      LAYER M5 ;
        RECT  11.52 0 11.544 0.192 ;
    END
  END d[58]
  PIN d[59]
    DIRECTION INPUT ;
    USE SIGNAL ;
    PORT
      LAYER M5 ;
        RECT  11.712 0 11.736 0.192 ;
    END
  END d[59]
  PIN d[5]
    DIRECTION INPUT ;
    USE SIGNAL ;
    PORT
      LAYER M5 ;
        RECT  1.344 0 1.368 0.192 ;
    END
  END d[5]
  PIN d[60]
    DIRECTION INPUT ;
    USE SIGNAL ;
    PORT
      LAYER M5 ;
        RECT  11.904 0 11.928 0.192 ;
    END
  END d[60]
  PIN d[61]
    DIRECTION INPUT ;
    USE SIGNAL ;
    PORT
      LAYER M5 ;
        RECT  12.096 0 12.12 0.192 ;
    END
  END d[61]
  PIN d[62]
    DIRECTION INPUT ;
    USE SIGNAL ;
    PORT
      LAYER M5 ;
        RECT  12.288 0 12.312 0.192 ;
    END
  END d[62]
  PIN d[63]
    DIRECTION INPUT ;
    USE SIGNAL ;
    PORT
      LAYER M5 ;
        RECT  12.48 0 12.504 0.192 ;
    END
  END d[63]
  PIN d[64]
    DIRECTION INPUT ;
    USE SIGNAL ;
    PORT
      LAYER M5 ;
        RECT  12.672 0 12.696 0.192 ;
    END
  END d[64]
  PIN d[65]
    DIRECTION INPUT ;
    USE SIGNAL ;
    PORT
      LAYER M5 ;
        RECT  12.864 0 12.888 0.192 ;
    END
  END d[65]
  PIN d[66]
    DIRECTION INPUT ;
    USE SIGNAL ;
    PORT
      LAYER M5 ;
        RECT  13.056 0 13.08 0.192 ;
    END
  END d[66]
  PIN d[67]
    DIRECTION INPUT ;
    USE SIGNAL ;
    PORT
      LAYER M5 ;
        RECT  13.248 0 13.272 0.192 ;
    END
  END d[67]
  PIN d[68]
    DIRECTION INPUT ;
    USE SIGNAL ;
    PORT
      LAYER M5 ;
        RECT  13.44 0 13.464 0.192 ;
    END
  END d[68]
  PIN d[69]
    DIRECTION INPUT ;
    USE SIGNAL ;
    PORT
      LAYER M5 ;
        RECT  13.632 0 13.656 0.192 ;
    END
  END d[69]
  PIN d[6]
    DIRECTION INPUT ;
    USE SIGNAL ;
    PORT
      LAYER M5 ;
        RECT  1.536 0 1.56 0.192 ;
    END
  END d[6]
  PIN d[70]
    DIRECTION INPUT ;
    USE SIGNAL ;
    PORT
      LAYER M5 ;
        RECT  13.824 0 13.848 0.192 ;
    END
  END d[70]
  PIN d[71]
    DIRECTION INPUT ;
    USE SIGNAL ;
    PORT
      LAYER M5 ;
        RECT  14.016 0 14.04 0.192 ;
    END
  END d[71]
  PIN d[72]
    DIRECTION INPUT ;
    USE SIGNAL ;
    PORT
      LAYER M5 ;
        RECT  14.208 0 14.232 0.192 ;
    END
  END d[72]
  PIN d[73]
    DIRECTION INPUT ;
    USE SIGNAL ;
    PORT
      LAYER M5 ;
        RECT  14.4 0 14.424 0.192 ;
    END
  END d[73]
  PIN d[74]
    DIRECTION INPUT ;
    USE SIGNAL ;
    PORT
      LAYER M5 ;
        RECT  14.592 0 14.616 0.192 ;
    END
  END d[74]
  PIN d[75]
    DIRECTION INPUT ;
    USE SIGNAL ;
    PORT
      LAYER M5 ;
        RECT  14.784 0 14.808 0.192 ;
    END
  END d[75]
  PIN d[76]
    DIRECTION INPUT ;
    USE SIGNAL ;
    PORT
      LAYER M5 ;
        RECT  14.976 0 15 0.192 ;
    END
  END d[76]
  PIN d[77]
    DIRECTION INPUT ;
    USE SIGNAL ;
    PORT
      LAYER M5 ;
        RECT  15.168 0 15.192 0.192 ;
    END
  END d[77]
  PIN d[78]
    DIRECTION INPUT ;
    USE SIGNAL ;
    PORT
      LAYER M5 ;
        RECT  15.36 0 15.384 0.192 ;
    END
  END d[78]
  PIN d[79]
    DIRECTION INPUT ;
    USE SIGNAL ;
    PORT
      LAYER M5 ;
        RECT  15.552 0 15.576 0.192 ;
    END
  END d[79]
  PIN d[7]
    DIRECTION INPUT ;
    USE SIGNAL ;
    PORT
      LAYER M5 ;
        RECT  1.728 0 1.752 0.192 ;
    END
  END d[7]
  PIN d[80]
    DIRECTION INPUT ;
    USE SIGNAL ;
    PORT
      LAYER M5 ;
        RECT  15.744 0 15.768 0.192 ;
    END
  END d[80]
  PIN d[81]
    DIRECTION INPUT ;
    USE SIGNAL ;
    PORT
      LAYER M5 ;
        RECT  15.936 0 15.96 0.192 ;
    END
  END d[81]
  PIN d[82]
    DIRECTION INPUT ;
    USE SIGNAL ;
    PORT
      LAYER M5 ;
        RECT  16.128 0 16.152 0.192 ;
    END
  END d[82]
  PIN d[83]
    DIRECTION INPUT ;
    USE SIGNAL ;
    PORT
      LAYER M5 ;
        RECT  16.32 0 16.344 0.192 ;
    END
  END d[83]
  PIN d[84]
    DIRECTION INPUT ;
    USE SIGNAL ;
    PORT
      LAYER M5 ;
        RECT  16.512 0 16.536 0.192 ;
    END
  END d[84]
  PIN d[85]
    DIRECTION INPUT ;
    USE SIGNAL ;
    PORT
      LAYER M5 ;
        RECT  16.704 0 16.728 0.192 ;
    END
  END d[85]
  PIN d[86]
    DIRECTION INPUT ;
    USE SIGNAL ;
    PORT
      LAYER M5 ;
        RECT  16.896 0 16.92 0.192 ;
    END
  END d[86]
  PIN d[87]
    DIRECTION INPUT ;
    USE SIGNAL ;
    PORT
      LAYER M5 ;
        RECT  17.088 0 17.112 0.192 ;
    END
  END d[87]
  PIN d[88]
    DIRECTION INPUT ;
    USE SIGNAL ;
    PORT
      LAYER M5 ;
        RECT  17.28 0 17.304 0.192 ;
    END
  END d[88]
  PIN d[89]
    DIRECTION INPUT ;
    USE SIGNAL ;
    PORT
      LAYER M5 ;
        RECT  17.472 0 17.496 0.192 ;
    END
  END d[89]
  PIN d[8]
    DIRECTION INPUT ;
    USE SIGNAL ;
    PORT
      LAYER M5 ;
        RECT  1.92 0 1.944 0.192 ;
    END
  END d[8]
  PIN d[90]
    DIRECTION INPUT ;
    USE SIGNAL ;
    PORT
      LAYER M5 ;
        RECT  17.664 0 17.688 0.192 ;
    END
  END d[90]
  PIN d[91]
    DIRECTION INPUT ;
    USE SIGNAL ;
    PORT
      LAYER M5 ;
        RECT  17.856 0 17.88 0.192 ;
    END
  END d[91]
  PIN d[92]
    DIRECTION INPUT ;
    USE SIGNAL ;
    PORT
      LAYER M5 ;
        RECT  18.048 0 18.072 0.192 ;
    END
  END d[92]
  PIN d[93]
    DIRECTION INPUT ;
    USE SIGNAL ;
    PORT
      LAYER M5 ;
        RECT  18.24 0 18.264 0.192 ;
    END
  END d[93]
  PIN d[94]
    DIRECTION INPUT ;
    USE SIGNAL ;
    PORT
      LAYER M5 ;
        RECT  18.432 0 18.456 0.192 ;
    END
  END d[94]
  PIN d[95]
    DIRECTION INPUT ;
    USE SIGNAL ;
    PORT
      LAYER M5 ;
        RECT  18.624 0 18.648 0.192 ;
    END
  END d[95]
  PIN d[96]
    DIRECTION INPUT ;
    USE SIGNAL ;
    PORT
      LAYER M5 ;
        RECT  18.816 0 18.84 0.192 ;
    END
  END d[96]
  PIN d[97]
    DIRECTION INPUT ;
    USE SIGNAL ;
    PORT
      LAYER M5 ;
        RECT  19.008 0 19.032 0.192 ;
    END
  END d[97]
  PIN d[98]
    DIRECTION INPUT ;
    USE SIGNAL ;
    PORT
      LAYER M5 ;
        RECT  19.2 0 19.224 0.192 ;
    END
  END d[98]
  PIN d[99]
    DIRECTION INPUT ;
    USE SIGNAL ;
    PORT
      LAYER M5 ;
        RECT  19.392 0 19.416 0.192 ;
    END
  END d[99]
  PIN d[9]
    DIRECTION INPUT ;
    USE SIGNAL ;
    PORT
      LAYER M5 ;
        RECT  2.112 0 2.136 0.192 ;
    END
  END d[9]
  PIN q[0]
    DIRECTION OUTPUT ;
    USE SIGNAL ;
    PORT
      LAYER M5 ;
        RECT  0.384 11.688 0.408 11.88 ;
    END
  END q[0]
  PIN q[100]
    DIRECTION OUTPUT ;
    USE SIGNAL ;
    PORT
      LAYER M5 ;
        RECT  19.584 11.688 19.608 11.88 ;
    END
  END q[100]
  PIN q[101]
    DIRECTION OUTPUT ;
    USE SIGNAL ;
    PORT
      LAYER M5 ;
        RECT  19.776 11.688 19.8 11.88 ;
    END
  END q[101]
  PIN q[102]
    DIRECTION OUTPUT ;
    USE SIGNAL ;
    PORT
      LAYER M5 ;
        RECT  19.968 11.688 19.992 11.88 ;
    END
  END q[102]
  PIN q[103]
    DIRECTION OUTPUT ;
    USE SIGNAL ;
    PORT
      LAYER M5 ;
        RECT  20.16 11.688 20.184 11.88 ;
    END
  END q[103]
  PIN q[104]
    DIRECTION OUTPUT ;
    USE SIGNAL ;
    PORT
      LAYER M5 ;
        RECT  20.352 11.688 20.376 11.88 ;
    END
  END q[104]
  PIN q[105]
    DIRECTION OUTPUT ;
    USE SIGNAL ;
    PORT
      LAYER M5 ;
        RECT  20.544 11.688 20.568 11.88 ;
    END
  END q[105]
  PIN q[106]
    DIRECTION OUTPUT ;
    USE SIGNAL ;
    PORT
      LAYER M5 ;
        RECT  20.736 11.688 20.76 11.88 ;
    END
  END q[106]
  PIN q[107]
    DIRECTION OUTPUT ;
    USE SIGNAL ;
    PORT
      LAYER M5 ;
        RECT  20.928 11.688 20.952 11.88 ;
    END
  END q[107]
  PIN q[108]
    DIRECTION OUTPUT ;
    USE SIGNAL ;
    PORT
      LAYER M5 ;
        RECT  21.12 11.688 21.144 11.88 ;
    END
  END q[108]
  PIN q[109]
    DIRECTION OUTPUT ;
    USE SIGNAL ;
    PORT
      LAYER M5 ;
        RECT  21.312 11.688 21.336 11.88 ;
    END
  END q[109]
  PIN q[10]
    DIRECTION OUTPUT ;
    USE SIGNAL ;
    PORT
      LAYER M5 ;
        RECT  2.304 11.688 2.328 11.88 ;
    END
  END q[10]
  PIN q[110]
    DIRECTION OUTPUT ;
    USE SIGNAL ;
    PORT
      LAYER M5 ;
        RECT  21.504 11.688 21.528 11.88 ;
    END
  END q[110]
  PIN q[111]
    DIRECTION OUTPUT ;
    USE SIGNAL ;
    PORT
      LAYER M5 ;
        RECT  21.696 11.688 21.72 11.88 ;
    END
  END q[111]
  PIN q[112]
    DIRECTION OUTPUT ;
    USE SIGNAL ;
    PORT
      LAYER M5 ;
        RECT  21.888 11.688 21.912 11.88 ;
    END
  END q[112]
  PIN q[113]
    DIRECTION OUTPUT ;
    USE SIGNAL ;
    PORT
      LAYER M5 ;
        RECT  22.08 11.688 22.104 11.88 ;
    END
  END q[113]
  PIN q[114]
    DIRECTION OUTPUT ;
    USE SIGNAL ;
    PORT
      LAYER M5 ;
        RECT  22.272 11.688 22.296 11.88 ;
    END
  END q[114]
  PIN q[115]
    DIRECTION OUTPUT ;
    USE SIGNAL ;
    PORT
      LAYER M5 ;
        RECT  22.464 11.688 22.488 11.88 ;
    END
  END q[115]
  PIN q[116]
    DIRECTION OUTPUT ;
    USE SIGNAL ;
    PORT
      LAYER M5 ;
        RECT  22.656 11.688 22.68 11.88 ;
    END
  END q[116]
  PIN q[117]
    DIRECTION OUTPUT ;
    USE SIGNAL ;
    PORT
      LAYER M5 ;
        RECT  22.848 11.688 22.872 11.88 ;
    END
  END q[117]
  PIN q[118]
    DIRECTION OUTPUT ;
    USE SIGNAL ;
    PORT
      LAYER M5 ;
        RECT  23.04 11.688 23.064 11.88 ;
    END
  END q[118]
  PIN q[119]
    DIRECTION OUTPUT ;
    USE SIGNAL ;
    PORT
      LAYER M5 ;
        RECT  23.232 11.688 23.256 11.88 ;
    END
  END q[119]
  PIN q[11]
    DIRECTION OUTPUT ;
    USE SIGNAL ;
    PORT
      LAYER M5 ;
        RECT  2.496 11.688 2.52 11.88 ;
    END
  END q[11]
  PIN q[120]
    DIRECTION OUTPUT ;
    USE SIGNAL ;
    PORT
      LAYER M5 ;
        RECT  23.424 11.688 23.448 11.88 ;
    END
  END q[120]
  PIN q[121]
    DIRECTION OUTPUT ;
    USE SIGNAL ;
    PORT
      LAYER M5 ;
        RECT  23.616 11.688 23.64 11.88 ;
    END
  END q[121]
  PIN q[122]
    DIRECTION OUTPUT ;
    USE SIGNAL ;
    PORT
      LAYER M5 ;
        RECT  23.808 11.688 23.832 11.88 ;
    END
  END q[122]
  PIN q[123]
    DIRECTION OUTPUT ;
    USE SIGNAL ;
    PORT
      LAYER M5 ;
        RECT  24 11.688 24.024 11.88 ;
    END
  END q[123]
  PIN q[124]
    DIRECTION OUTPUT ;
    USE SIGNAL ;
    PORT
      LAYER M5 ;
        RECT  24.192 11.688 24.216 11.88 ;
    END
  END q[124]
  PIN q[125]
    DIRECTION OUTPUT ;
    USE SIGNAL ;
    PORT
      LAYER M5 ;
        RECT  24.384 11.688 24.408 11.88 ;
    END
  END q[125]
  PIN q[126]
    DIRECTION OUTPUT ;
    USE SIGNAL ;
    PORT
      LAYER M5 ;
        RECT  24.576 11.688 24.6 11.88 ;
    END
  END q[126]
  PIN q[127]
    DIRECTION OUTPUT ;
    USE SIGNAL ;
    PORT
      LAYER M5 ;
        RECT  24.768 11.688 24.792 11.88 ;
    END
  END q[127]
  PIN q[128]
    DIRECTION OUTPUT ;
    USE SIGNAL ;
    PORT
      LAYER M5 ;
        RECT  24.96 11.688 24.984 11.88 ;
    END
  END q[128]
  PIN q[129]
    DIRECTION OUTPUT ;
    USE SIGNAL ;
    PORT
      LAYER M5 ;
        RECT  25.152 11.688 25.176 11.88 ;
    END
  END q[129]
  PIN q[12]
    DIRECTION OUTPUT ;
    USE SIGNAL ;
    PORT
      LAYER M5 ;
        RECT  2.688 11.688 2.712 11.88 ;
    END
  END q[12]
  PIN q[130]
    DIRECTION OUTPUT ;
    USE SIGNAL ;
    PORT
      LAYER M5 ;
        RECT  25.344 11.688 25.368 11.88 ;
    END
  END q[130]
  PIN q[131]
    DIRECTION OUTPUT ;
    USE SIGNAL ;
    PORT
      LAYER M5 ;
        RECT  25.536 11.688 25.56 11.88 ;
    END
  END q[131]
  PIN q[132]
    DIRECTION OUTPUT ;
    USE SIGNAL ;
    PORT
      LAYER M5 ;
        RECT  25.728 11.688 25.752 11.88 ;
    END
  END q[132]
  PIN q[133]
    DIRECTION OUTPUT ;
    USE SIGNAL ;
    PORT
      LAYER M5 ;
        RECT  25.92 11.688 25.944 11.88 ;
    END
  END q[133]
  PIN q[134]
    DIRECTION OUTPUT ;
    USE SIGNAL ;
    PORT
      LAYER M5 ;
        RECT  26.112 11.688 26.136 11.88 ;
    END
  END q[134]
  PIN q[135]
    DIRECTION OUTPUT ;
    USE SIGNAL ;
    PORT
      LAYER M5 ;
        RECT  26.304 11.688 26.328 11.88 ;
    END
  END q[135]
  PIN q[136]
    DIRECTION OUTPUT ;
    USE SIGNAL ;
    PORT
      LAYER M5 ;
        RECT  26.496 11.688 26.52 11.88 ;
    END
  END q[136]
  PIN q[137]
    DIRECTION OUTPUT ;
    USE SIGNAL ;
    PORT
      LAYER M5 ;
        RECT  26.688 11.688 26.712 11.88 ;
    END
  END q[137]
  PIN q[138]
    DIRECTION OUTPUT ;
    USE SIGNAL ;
    PORT
      LAYER M5 ;
        RECT  26.88 11.688 26.904 11.88 ;
    END
  END q[138]
  PIN q[139]
    DIRECTION OUTPUT ;
    USE SIGNAL ;
    PORT
      LAYER M5 ;
        RECT  27.072 11.688 27.096 11.88 ;
    END
  END q[139]
  PIN q[13]
    DIRECTION OUTPUT ;
    USE SIGNAL ;
    PORT
      LAYER M5 ;
        RECT  2.88 11.688 2.904 11.88 ;
    END
  END q[13]
  PIN q[140]
    DIRECTION OUTPUT ;
    USE SIGNAL ;
    PORT
      LAYER M5 ;
        RECT  27.264 11.688 27.288 11.88 ;
    END
  END q[140]
  PIN q[141]
    DIRECTION OUTPUT ;
    USE SIGNAL ;
    PORT
      LAYER M5 ;
        RECT  27.456 11.688 27.48 11.88 ;
    END
  END q[141]
  PIN q[142]
    DIRECTION OUTPUT ;
    USE SIGNAL ;
    PORT
      LAYER M5 ;
        RECT  27.648 11.688 27.672 11.88 ;
    END
  END q[142]
  PIN q[143]
    DIRECTION OUTPUT ;
    USE SIGNAL ;
    PORT
      LAYER M5 ;
        RECT  27.84 11.688 27.864 11.88 ;
    END
  END q[143]
  PIN q[144]
    DIRECTION OUTPUT ;
    USE SIGNAL ;
    PORT
      LAYER M5 ;
        RECT  28.032 11.688 28.056 11.88 ;
    END
  END q[144]
  PIN q[145]
    DIRECTION OUTPUT ;
    USE SIGNAL ;
    PORT
      LAYER M5 ;
        RECT  28.224 11.688 28.248 11.88 ;
    END
  END q[145]
  PIN q[146]
    DIRECTION OUTPUT ;
    USE SIGNAL ;
    PORT
      LAYER M5 ;
        RECT  28.416 11.688 28.44 11.88 ;
    END
  END q[146]
  PIN q[147]
    DIRECTION OUTPUT ;
    USE SIGNAL ;
    PORT
      LAYER M5 ;
        RECT  28.608 11.688 28.632 11.88 ;
    END
  END q[147]
  PIN q[148]
    DIRECTION OUTPUT ;
    USE SIGNAL ;
    PORT
      LAYER M5 ;
        RECT  28.8 11.688 28.824 11.88 ;
    END
  END q[148]
  PIN q[149]
    DIRECTION OUTPUT ;
    USE SIGNAL ;
    PORT
      LAYER M5 ;
        RECT  28.992 11.688 29.016 11.88 ;
    END
  END q[149]
  PIN q[14]
    DIRECTION OUTPUT ;
    USE SIGNAL ;
    PORT
      LAYER M5 ;
        RECT  3.072 11.688 3.096 11.88 ;
    END
  END q[14]
  PIN q[150]
    DIRECTION OUTPUT ;
    USE SIGNAL ;
    PORT
      LAYER M5 ;
        RECT  29.184 11.688 29.208 11.88 ;
    END
  END q[150]
  PIN q[151]
    DIRECTION OUTPUT ;
    USE SIGNAL ;
    PORT
      LAYER M5 ;
        RECT  29.376 11.688 29.4 11.88 ;
    END
  END q[151]
  PIN q[152]
    DIRECTION OUTPUT ;
    USE SIGNAL ;
    PORT
      LAYER M5 ;
        RECT  29.568 11.688 29.592 11.88 ;
    END
  END q[152]
  PIN q[153]
    DIRECTION OUTPUT ;
    USE SIGNAL ;
    PORT
      LAYER M5 ;
        RECT  29.76 11.688 29.784 11.88 ;
    END
  END q[153]
  PIN q[154]
    DIRECTION OUTPUT ;
    USE SIGNAL ;
    PORT
      LAYER M5 ;
        RECT  29.952 11.688 29.976 11.88 ;
    END
  END q[154]
  PIN q[155]
    DIRECTION OUTPUT ;
    USE SIGNAL ;
    PORT
      LAYER M5 ;
        RECT  30.144 11.688 30.168 11.88 ;
    END
  END q[155]
  PIN q[156]
    DIRECTION OUTPUT ;
    USE SIGNAL ;
    PORT
      LAYER M5 ;
        RECT  30.336 11.688 30.36 11.88 ;
    END
  END q[156]
  PIN q[157]
    DIRECTION OUTPUT ;
    USE SIGNAL ;
    PORT
      LAYER M5 ;
        RECT  30.528 11.688 30.552 11.88 ;
    END
  END q[157]
  PIN q[158]
    DIRECTION OUTPUT ;
    USE SIGNAL ;
    PORT
      LAYER M5 ;
        RECT  30.72 11.688 30.744 11.88 ;
    END
  END q[158]
  PIN q[159]
    DIRECTION OUTPUT ;
    USE SIGNAL ;
    PORT
      LAYER M5 ;
        RECT  30.912 11.688 30.936 11.88 ;
    END
  END q[159]
  PIN q[15]
    DIRECTION OUTPUT ;
    USE SIGNAL ;
    PORT
      LAYER M5 ;
        RECT  3.264 11.688 3.288 11.88 ;
    END
  END q[15]
  PIN q[160]
    DIRECTION OUTPUT ;
    USE SIGNAL ;
    PORT
      LAYER M5 ;
        RECT  31.104 11.688 31.128 11.88 ;
    END
  END q[160]
  PIN q[161]
    DIRECTION OUTPUT ;
    USE SIGNAL ;
    PORT
      LAYER M5 ;
        RECT  31.296 11.688 31.32 11.88 ;
    END
  END q[161]
  PIN q[162]
    DIRECTION OUTPUT ;
    USE SIGNAL ;
    PORT
      LAYER M5 ;
        RECT  31.488 11.688 31.512 11.88 ;
    END
  END q[162]
  PIN q[163]
    DIRECTION OUTPUT ;
    USE SIGNAL ;
    PORT
      LAYER M5 ;
        RECT  31.68 11.688 31.704 11.88 ;
    END
  END q[163]
  PIN q[164]
    DIRECTION OUTPUT ;
    USE SIGNAL ;
    PORT
      LAYER M5 ;
        RECT  31.872 11.688 31.896 11.88 ;
    END
  END q[164]
  PIN q[165]
    DIRECTION OUTPUT ;
    USE SIGNAL ;
    PORT
      LAYER M5 ;
        RECT  32.064 11.688 32.088 11.88 ;
    END
  END q[165]
  PIN q[166]
    DIRECTION OUTPUT ;
    USE SIGNAL ;
    PORT
      LAYER M5 ;
        RECT  32.256 11.688 32.28 11.88 ;
    END
  END q[166]
  PIN q[167]
    DIRECTION OUTPUT ;
    USE SIGNAL ;
    PORT
      LAYER M5 ;
        RECT  32.448 11.688 32.472 11.88 ;
    END
  END q[167]
  PIN q[168]
    DIRECTION OUTPUT ;
    USE SIGNAL ;
    PORT
      LAYER M5 ;
        RECT  32.64 11.688 32.664 11.88 ;
    END
  END q[168]
  PIN q[169]
    DIRECTION OUTPUT ;
    USE SIGNAL ;
    PORT
      LAYER M5 ;
        RECT  32.832 11.688 32.856 11.88 ;
    END
  END q[169]
  PIN q[16]
    DIRECTION OUTPUT ;
    USE SIGNAL ;
    PORT
      LAYER M5 ;
        RECT  3.456 11.688 3.48 11.88 ;
    END
  END q[16]
  PIN q[170]
    DIRECTION OUTPUT ;
    USE SIGNAL ;
    PORT
      LAYER M5 ;
        RECT  33.024 11.688 33.048 11.88 ;
    END
  END q[170]
  PIN q[171]
    DIRECTION OUTPUT ;
    USE SIGNAL ;
    PORT
      LAYER M5 ;
        RECT  33.216 11.688 33.24 11.88 ;
    END
  END q[171]
  PIN q[172]
    DIRECTION OUTPUT ;
    USE SIGNAL ;
    PORT
      LAYER M5 ;
        RECT  33.408 11.688 33.432 11.88 ;
    END
  END q[172]
  PIN q[173]
    DIRECTION OUTPUT ;
    USE SIGNAL ;
    PORT
      LAYER M5 ;
        RECT  33.6 11.688 33.624 11.88 ;
    END
  END q[173]
  PIN q[174]
    DIRECTION OUTPUT ;
    USE SIGNAL ;
    PORT
      LAYER M5 ;
        RECT  33.792 11.688 33.816 11.88 ;
    END
  END q[174]
  PIN q[175]
    DIRECTION OUTPUT ;
    USE SIGNAL ;
    PORT
      LAYER M5 ;
        RECT  33.984 11.688 34.008 11.88 ;
    END
  END q[175]
  PIN q[176]
    DIRECTION OUTPUT ;
    USE SIGNAL ;
    PORT
      LAYER M5 ;
        RECT  34.176 11.688 34.2 11.88 ;
    END
  END q[176]
  PIN q[177]
    DIRECTION OUTPUT ;
    USE SIGNAL ;
    PORT
      LAYER M5 ;
        RECT  34.368 11.688 34.392 11.88 ;
    END
  END q[177]
  PIN q[178]
    DIRECTION OUTPUT ;
    USE SIGNAL ;
    PORT
      LAYER M5 ;
        RECT  34.56 11.688 34.584 11.88 ;
    END
  END q[178]
  PIN q[179]
    DIRECTION OUTPUT ;
    USE SIGNAL ;
    PORT
      LAYER M5 ;
        RECT  34.752 11.688 34.776 11.88 ;
    END
  END q[179]
  PIN q[17]
    DIRECTION OUTPUT ;
    USE SIGNAL ;
    PORT
      LAYER M5 ;
        RECT  3.648 11.688 3.672 11.88 ;
    END
  END q[17]
  PIN q[180]
    DIRECTION OUTPUT ;
    USE SIGNAL ;
    PORT
      LAYER M5 ;
        RECT  34.944 11.688 34.968 11.88 ;
    END
  END q[180]
  PIN q[181]
    DIRECTION OUTPUT ;
    USE SIGNAL ;
    PORT
      LAYER M5 ;
        RECT  35.136 11.688 35.16 11.88 ;
    END
  END q[181]
  PIN q[182]
    DIRECTION OUTPUT ;
    USE SIGNAL ;
    PORT
      LAYER M5 ;
        RECT  35.328 11.688 35.352 11.88 ;
    END
  END q[182]
  PIN q[183]
    DIRECTION OUTPUT ;
    USE SIGNAL ;
    PORT
      LAYER M5 ;
        RECT  35.52 11.688 35.544 11.88 ;
    END
  END q[183]
  PIN q[184]
    DIRECTION OUTPUT ;
    USE SIGNAL ;
    PORT
      LAYER M5 ;
        RECT  35.712 11.688 35.736 11.88 ;
    END
  END q[184]
  PIN q[185]
    DIRECTION OUTPUT ;
    USE SIGNAL ;
    PORT
      LAYER M5 ;
        RECT  35.904 11.688 35.928 11.88 ;
    END
  END q[185]
  PIN q[186]
    DIRECTION OUTPUT ;
    USE SIGNAL ;
    PORT
      LAYER M5 ;
        RECT  36.096 11.688 36.12 11.88 ;
    END
  END q[186]
  PIN q[187]
    DIRECTION OUTPUT ;
    USE SIGNAL ;
    PORT
      LAYER M5 ;
        RECT  36.288 11.688 36.312 11.88 ;
    END
  END q[187]
  PIN q[188]
    DIRECTION OUTPUT ;
    USE SIGNAL ;
    PORT
      LAYER M5 ;
        RECT  36.48 11.688 36.504 11.88 ;
    END
  END q[188]
  PIN q[189]
    DIRECTION OUTPUT ;
    USE SIGNAL ;
    PORT
      LAYER M5 ;
        RECT  36.672 11.688 36.696 11.88 ;
    END
  END q[189]
  PIN q[18]
    DIRECTION OUTPUT ;
    USE SIGNAL ;
    PORT
      LAYER M5 ;
        RECT  3.84 11.688 3.864 11.88 ;
    END
  END q[18]
  PIN q[190]
    DIRECTION OUTPUT ;
    USE SIGNAL ;
    PORT
      LAYER M5 ;
        RECT  36.864 11.688 36.888 11.88 ;
    END
  END q[190]
  PIN q[191]
    DIRECTION OUTPUT ;
    USE SIGNAL ;
    PORT
      LAYER M5 ;
        RECT  37.056 11.688 37.08 11.88 ;
    END
  END q[191]
  PIN q[192]
    DIRECTION OUTPUT ;
    USE SIGNAL ;
    PORT
      LAYER M5 ;
        RECT  37.248 11.688 37.272 11.88 ;
    END
  END q[192]
  PIN q[193]
    DIRECTION OUTPUT ;
    USE SIGNAL ;
    PORT
      LAYER M5 ;
        RECT  37.44 11.688 37.464 11.88 ;
    END
  END q[193]
  PIN q[194]
    DIRECTION OUTPUT ;
    USE SIGNAL ;
    PORT
      LAYER M5 ;
        RECT  37.632 11.688 37.656 11.88 ;
    END
  END q[194]
  PIN q[195]
    DIRECTION OUTPUT ;
    USE SIGNAL ;
    PORT
      LAYER M5 ;
        RECT  37.824 11.688 37.848 11.88 ;
    END
  END q[195]
  PIN q[196]
    DIRECTION OUTPUT ;
    USE SIGNAL ;
    PORT
      LAYER M5 ;
        RECT  38.016 11.688 38.04 11.88 ;
    END
  END q[196]
  PIN q[197]
    DIRECTION OUTPUT ;
    USE SIGNAL ;
    PORT
      LAYER M5 ;
        RECT  38.208 11.688 38.232 11.88 ;
    END
  END q[197]
  PIN q[198]
    DIRECTION OUTPUT ;
    USE SIGNAL ;
    PORT
      LAYER M5 ;
        RECT  38.4 11.688 38.424 11.88 ;
    END
  END q[198]
  PIN q[199]
    DIRECTION OUTPUT ;
    USE SIGNAL ;
    PORT
      LAYER M5 ;
        RECT  38.592 11.688 38.616 11.88 ;
    END
  END q[199]
  PIN q[19]
    DIRECTION OUTPUT ;
    USE SIGNAL ;
    PORT
      LAYER M5 ;
        RECT  4.032 11.688 4.056 11.88 ;
    END
  END q[19]
  PIN q[1]
    DIRECTION OUTPUT ;
    USE SIGNAL ;
    PORT
      LAYER M5 ;
        RECT  0.576 11.688 0.6 11.88 ;
    END
  END q[1]
  PIN q[200]
    DIRECTION OUTPUT ;
    USE SIGNAL ;
    PORT
      LAYER M5 ;
        RECT  38.784 11.688 38.808 11.88 ;
    END
  END q[200]
  PIN q[201]
    DIRECTION OUTPUT ;
    USE SIGNAL ;
    PORT
      LAYER M5 ;
        RECT  38.976 11.688 39 11.88 ;
    END
  END q[201]
  PIN q[202]
    DIRECTION OUTPUT ;
    USE SIGNAL ;
    PORT
      LAYER M5 ;
        RECT  39.168 11.688 39.192 11.88 ;
    END
  END q[202]
  PIN q[203]
    DIRECTION OUTPUT ;
    USE SIGNAL ;
    PORT
      LAYER M5 ;
        RECT  39.36 11.688 39.384 11.88 ;
    END
  END q[203]
  PIN q[204]
    DIRECTION OUTPUT ;
    USE SIGNAL ;
    PORT
      LAYER M5 ;
        RECT  39.552 11.688 39.576 11.88 ;
    END
  END q[204]
  PIN q[205]
    DIRECTION OUTPUT ;
    USE SIGNAL ;
    PORT
      LAYER M5 ;
        RECT  39.744 11.688 39.768 11.88 ;
    END
  END q[205]
  PIN q[206]
    DIRECTION OUTPUT ;
    USE SIGNAL ;
    PORT
      LAYER M5 ;
        RECT  39.936 11.688 39.96 11.88 ;
    END
  END q[206]
  PIN q[207]
    DIRECTION OUTPUT ;
    USE SIGNAL ;
    PORT
      LAYER M5 ;
        RECT  40.128 11.688 40.152 11.88 ;
    END
  END q[207]
  PIN q[208]
    DIRECTION OUTPUT ;
    USE SIGNAL ;
    PORT
      LAYER M5 ;
        RECT  40.32 11.688 40.344 11.88 ;
    END
  END q[208]
  PIN q[209]
    DIRECTION OUTPUT ;
    USE SIGNAL ;
    PORT
      LAYER M5 ;
        RECT  40.512 11.688 40.536 11.88 ;
    END
  END q[209]
  PIN q[20]
    DIRECTION OUTPUT ;
    USE SIGNAL ;
    PORT
      LAYER M5 ;
        RECT  4.224 11.688 4.248 11.88 ;
    END
  END q[20]
  PIN q[210]
    DIRECTION OUTPUT ;
    USE SIGNAL ;
    PORT
      LAYER M5 ;
        RECT  40.704 11.688 40.728 11.88 ;
    END
  END q[210]
  PIN q[211]
    DIRECTION OUTPUT ;
    USE SIGNAL ;
    PORT
      LAYER M5 ;
        RECT  40.896 11.688 40.92 11.88 ;
    END
  END q[211]
  PIN q[212]
    DIRECTION OUTPUT ;
    USE SIGNAL ;
    PORT
      LAYER M5 ;
        RECT  41.088 11.688 41.112 11.88 ;
    END
  END q[212]
  PIN q[213]
    DIRECTION OUTPUT ;
    USE SIGNAL ;
    PORT
      LAYER M5 ;
        RECT  41.28 11.688 41.304 11.88 ;
    END
  END q[213]
  PIN q[214]
    DIRECTION OUTPUT ;
    USE SIGNAL ;
    PORT
      LAYER M5 ;
        RECT  41.472 11.688 41.496 11.88 ;
    END
  END q[214]
  PIN q[215]
    DIRECTION OUTPUT ;
    USE SIGNAL ;
    PORT
      LAYER M5 ;
        RECT  41.664 11.688 41.688 11.88 ;
    END
  END q[215]
  PIN q[216]
    DIRECTION OUTPUT ;
    USE SIGNAL ;
    PORT
      LAYER M5 ;
        RECT  41.856 11.688 41.88 11.88 ;
    END
  END q[216]
  PIN q[217]
    DIRECTION OUTPUT ;
    USE SIGNAL ;
    PORT
      LAYER M5 ;
        RECT  42.048 11.688 42.072 11.88 ;
    END
  END q[217]
  PIN q[218]
    DIRECTION OUTPUT ;
    USE SIGNAL ;
    PORT
      LAYER M5 ;
        RECT  42.24 11.688 42.264 11.88 ;
    END
  END q[218]
  PIN q[219]
    DIRECTION OUTPUT ;
    USE SIGNAL ;
    PORT
      LAYER M5 ;
        RECT  42.432 11.688 42.456 11.88 ;
    END
  END q[219]
  PIN q[21]
    DIRECTION OUTPUT ;
    USE SIGNAL ;
    PORT
      LAYER M5 ;
        RECT  4.416 11.688 4.44 11.88 ;
    END
  END q[21]
  PIN q[220]
    DIRECTION OUTPUT ;
    USE SIGNAL ;
    PORT
      LAYER M5 ;
        RECT  42.624 11.688 42.648 11.88 ;
    END
  END q[220]
  PIN q[221]
    DIRECTION OUTPUT ;
    USE SIGNAL ;
    PORT
      LAYER M5 ;
        RECT  42.816 11.688 42.84 11.88 ;
    END
  END q[221]
  PIN q[222]
    DIRECTION OUTPUT ;
    USE SIGNAL ;
    PORT
      LAYER M5 ;
        RECT  43.008 11.688 43.032 11.88 ;
    END
  END q[222]
  PIN q[223]
    DIRECTION OUTPUT ;
    USE SIGNAL ;
    PORT
      LAYER M5 ;
        RECT  43.2 11.688 43.224 11.88 ;
    END
  END q[223]
  PIN q[224]
    DIRECTION OUTPUT ;
    USE SIGNAL ;
    PORT
      LAYER M5 ;
        RECT  43.392 11.688 43.416 11.88 ;
    END
  END q[224]
  PIN q[225]
    DIRECTION OUTPUT ;
    USE SIGNAL ;
    PORT
      LAYER M5 ;
        RECT  43.584 11.688 43.608 11.88 ;
    END
  END q[225]
  PIN q[226]
    DIRECTION OUTPUT ;
    USE SIGNAL ;
    PORT
      LAYER M5 ;
        RECT  43.776 11.688 43.8 11.88 ;
    END
  END q[226]
  PIN q[227]
    DIRECTION OUTPUT ;
    USE SIGNAL ;
    PORT
      LAYER M5 ;
        RECT  43.968 11.688 43.992 11.88 ;
    END
  END q[227]
  PIN q[228]
    DIRECTION OUTPUT ;
    USE SIGNAL ;
    PORT
      LAYER M5 ;
        RECT  44.16 11.688 44.184 11.88 ;
    END
  END q[228]
  PIN q[229]
    DIRECTION OUTPUT ;
    USE SIGNAL ;
    PORT
      LAYER M5 ;
        RECT  44.352 11.688 44.376 11.88 ;
    END
  END q[229]
  PIN q[22]
    DIRECTION OUTPUT ;
    USE SIGNAL ;
    PORT
      LAYER M5 ;
        RECT  4.608 11.688 4.632 11.88 ;
    END
  END q[22]
  PIN q[230]
    DIRECTION OUTPUT ;
    USE SIGNAL ;
    PORT
      LAYER M5 ;
        RECT  44.544 11.688 44.568 11.88 ;
    END
  END q[230]
  PIN q[231]
    DIRECTION OUTPUT ;
    USE SIGNAL ;
    PORT
      LAYER M5 ;
        RECT  44.736 11.688 44.76 11.88 ;
    END
  END q[231]
  PIN q[232]
    DIRECTION OUTPUT ;
    USE SIGNAL ;
    PORT
      LAYER M5 ;
        RECT  44.928 11.688 44.952 11.88 ;
    END
  END q[232]
  PIN q[233]
    DIRECTION OUTPUT ;
    USE SIGNAL ;
    PORT
      LAYER M5 ;
        RECT  45.12 11.688 45.144 11.88 ;
    END
  END q[233]
  PIN q[234]
    DIRECTION OUTPUT ;
    USE SIGNAL ;
    PORT
      LAYER M5 ;
        RECT  45.312 11.688 45.336 11.88 ;
    END
  END q[234]
  PIN q[235]
    DIRECTION OUTPUT ;
    USE SIGNAL ;
    PORT
      LAYER M5 ;
        RECT  45.504 11.688 45.528 11.88 ;
    END
  END q[235]
  PIN q[236]
    DIRECTION OUTPUT ;
    USE SIGNAL ;
    PORT
      LAYER M5 ;
        RECT  45.696 11.688 45.72 11.88 ;
    END
  END q[236]
  PIN q[237]
    DIRECTION OUTPUT ;
    USE SIGNAL ;
    PORT
      LAYER M5 ;
        RECT  45.888 11.688 45.912 11.88 ;
    END
  END q[237]
  PIN q[238]
    DIRECTION OUTPUT ;
    USE SIGNAL ;
    PORT
      LAYER M5 ;
        RECT  46.08 11.688 46.104 11.88 ;
    END
  END q[238]
  PIN q[239]
    DIRECTION OUTPUT ;
    USE SIGNAL ;
    PORT
      LAYER M5 ;
        RECT  46.272 11.688 46.296 11.88 ;
    END
  END q[239]
  PIN q[23]
    DIRECTION OUTPUT ;
    USE SIGNAL ;
    PORT
      LAYER M5 ;
        RECT  4.8 11.688 4.824 11.88 ;
    END
  END q[23]
  PIN q[240]
    DIRECTION OUTPUT ;
    USE SIGNAL ;
    PORT
      LAYER M5 ;
        RECT  46.464 11.688 46.488 11.88 ;
    END
  END q[240]
  PIN q[241]
    DIRECTION OUTPUT ;
    USE SIGNAL ;
    PORT
      LAYER M5 ;
        RECT  46.656 11.688 46.68 11.88 ;
    END
  END q[241]
  PIN q[242]
    DIRECTION OUTPUT ;
    USE SIGNAL ;
    PORT
      LAYER M5 ;
        RECT  46.848 11.688 46.872 11.88 ;
    END
  END q[242]
  PIN q[243]
    DIRECTION OUTPUT ;
    USE SIGNAL ;
    PORT
      LAYER M5 ;
        RECT  47.04 11.688 47.064 11.88 ;
    END
  END q[243]
  PIN q[244]
    DIRECTION OUTPUT ;
    USE SIGNAL ;
    PORT
      LAYER M5 ;
        RECT  47.232 11.688 47.256 11.88 ;
    END
  END q[244]
  PIN q[245]
    DIRECTION OUTPUT ;
    USE SIGNAL ;
    PORT
      LAYER M5 ;
        RECT  47.424 11.688 47.448 11.88 ;
    END
  END q[245]
  PIN q[246]
    DIRECTION OUTPUT ;
    USE SIGNAL ;
    PORT
      LAYER M5 ;
        RECT  47.616 11.688 47.64 11.88 ;
    END
  END q[246]
  PIN q[247]
    DIRECTION OUTPUT ;
    USE SIGNAL ;
    PORT
      LAYER M5 ;
        RECT  47.808 11.688 47.832 11.88 ;
    END
  END q[247]
  PIN q[248]
    DIRECTION OUTPUT ;
    USE SIGNAL ;
    PORT
      LAYER M5 ;
        RECT  48 11.688 48.024 11.88 ;
    END
  END q[248]
  PIN q[249]
    DIRECTION OUTPUT ;
    USE SIGNAL ;
    PORT
      LAYER M5 ;
        RECT  48.192 11.688 48.216 11.88 ;
    END
  END q[249]
  PIN q[24]
    DIRECTION OUTPUT ;
    USE SIGNAL ;
    PORT
      LAYER M5 ;
        RECT  4.992 11.688 5.016 11.88 ;
    END
  END q[24]
  PIN q[250]
    DIRECTION OUTPUT ;
    USE SIGNAL ;
    PORT
      LAYER M5 ;
        RECT  48.384 11.688 48.408 11.88 ;
    END
  END q[250]
  PIN q[251]
    DIRECTION OUTPUT ;
    USE SIGNAL ;
    PORT
      LAYER M5 ;
        RECT  48.576 11.688 48.6 11.88 ;
    END
  END q[251]
  PIN q[252]
    DIRECTION OUTPUT ;
    USE SIGNAL ;
    PORT
      LAYER M5 ;
        RECT  48.768 11.688 48.792 11.88 ;
    END
  END q[252]
  PIN q[253]
    DIRECTION OUTPUT ;
    USE SIGNAL ;
    PORT
      LAYER M5 ;
        RECT  48.96 11.688 48.984 11.88 ;
    END
  END q[253]
  PIN q[254]
    DIRECTION OUTPUT ;
    USE SIGNAL ;
    PORT
      LAYER M5 ;
        RECT  49.152 11.688 49.176 11.88 ;
    END
  END q[254]
  PIN q[255]
    DIRECTION OUTPUT ;
    USE SIGNAL ;
    PORT
      LAYER M5 ;
        RECT  49.344 11.688 49.368 11.88 ;
    END
  END q[255]
  PIN q[256]
    DIRECTION OUTPUT ;
    USE SIGNAL ;
    PORT
      LAYER M5 ;
        RECT  49.536 11.688 49.56 11.88 ;
    END
  END q[256]
  PIN q[257]
    DIRECTION OUTPUT ;
    USE SIGNAL ;
    PORT
      LAYER M5 ;
        RECT  49.728 11.688 49.752 11.88 ;
    END
  END q[257]
  PIN q[258]
    DIRECTION OUTPUT ;
    USE SIGNAL ;
    PORT
      LAYER M5 ;
        RECT  49.92 11.688 49.944 11.88 ;
    END
  END q[258]
  PIN q[259]
    DIRECTION OUTPUT ;
    USE SIGNAL ;
    PORT
      LAYER M5 ;
        RECT  50.112 11.688 50.136 11.88 ;
    END
  END q[259]
  PIN q[25]
    DIRECTION OUTPUT ;
    USE SIGNAL ;
    PORT
      LAYER M5 ;
        RECT  5.184 11.688 5.208 11.88 ;
    END
  END q[25]
  PIN q[260]
    DIRECTION OUTPUT ;
    USE SIGNAL ;
    PORT
      LAYER M5 ;
        RECT  50.304 11.688 50.328 11.88 ;
    END
  END q[260]
  PIN q[261]
    DIRECTION OUTPUT ;
    USE SIGNAL ;
    PORT
      LAYER M5 ;
        RECT  50.496 11.688 50.52 11.88 ;
    END
  END q[261]
  PIN q[262]
    DIRECTION OUTPUT ;
    USE SIGNAL ;
    PORT
      LAYER M5 ;
        RECT  50.688 11.688 50.712 11.88 ;
    END
  END q[262]
  PIN q[263]
    DIRECTION OUTPUT ;
    USE SIGNAL ;
    PORT
      LAYER M5 ;
        RECT  50.88 11.688 50.904 11.88 ;
    END
  END q[263]
  PIN q[264]
    DIRECTION OUTPUT ;
    USE SIGNAL ;
    PORT
      LAYER M5 ;
        RECT  51.072 11.688 51.096 11.88 ;
    END
  END q[264]
  PIN q[265]
    DIRECTION OUTPUT ;
    USE SIGNAL ;
    PORT
      LAYER M5 ;
        RECT  51.264 11.688 51.288 11.88 ;
    END
  END q[265]
  PIN q[266]
    DIRECTION OUTPUT ;
    USE SIGNAL ;
    PORT
      LAYER M5 ;
        RECT  51.456 11.688 51.48 11.88 ;
    END
  END q[266]
  PIN q[267]
    DIRECTION OUTPUT ;
    USE SIGNAL ;
    PORT
      LAYER M5 ;
        RECT  51.648 11.688 51.672 11.88 ;
    END
  END q[267]
  PIN q[268]
    DIRECTION OUTPUT ;
    USE SIGNAL ;
    PORT
      LAYER M5 ;
        RECT  51.84 11.688 51.864 11.88 ;
    END
  END q[268]
  PIN q[269]
    DIRECTION OUTPUT ;
    USE SIGNAL ;
    PORT
      LAYER M5 ;
        RECT  52.032 11.688 52.056 11.88 ;
    END
  END q[269]
  PIN q[26]
    DIRECTION OUTPUT ;
    USE SIGNAL ;
    PORT
      LAYER M5 ;
        RECT  5.376 11.688 5.4 11.88 ;
    END
  END q[26]
  PIN q[270]
    DIRECTION OUTPUT ;
    USE SIGNAL ;
    PORT
      LAYER M5 ;
        RECT  52.224 11.688 52.248 11.88 ;
    END
  END q[270]
  PIN q[271]
    DIRECTION OUTPUT ;
    USE SIGNAL ;
    PORT
      LAYER M5 ;
        RECT  52.416 11.688 52.44 11.88 ;
    END
  END q[271]
  PIN q[272]
    DIRECTION OUTPUT ;
    USE SIGNAL ;
    PORT
      LAYER M5 ;
        RECT  52.608 11.688 52.632 11.88 ;
    END
  END q[272]
  PIN q[273]
    DIRECTION OUTPUT ;
    USE SIGNAL ;
    PORT
      LAYER M5 ;
        RECT  52.8 11.688 52.824 11.88 ;
    END
  END q[273]
  PIN q[274]
    DIRECTION OUTPUT ;
    USE SIGNAL ;
    PORT
      LAYER M5 ;
        RECT  52.992 11.688 53.016 11.88 ;
    END
  END q[274]
  PIN q[275]
    DIRECTION OUTPUT ;
    USE SIGNAL ;
    PORT
      LAYER M5 ;
        RECT  53.184 11.688 53.208 11.88 ;
    END
  END q[275]
  PIN q[276]
    DIRECTION OUTPUT ;
    USE SIGNAL ;
    PORT
      LAYER M5 ;
        RECT  53.376 11.688 53.4 11.88 ;
    END
  END q[276]
  PIN q[277]
    DIRECTION OUTPUT ;
    USE SIGNAL ;
    PORT
      LAYER M5 ;
        RECT  53.568 11.688 53.592 11.88 ;
    END
  END q[277]
  PIN q[278]
    DIRECTION OUTPUT ;
    USE SIGNAL ;
    PORT
      LAYER M5 ;
        RECT  53.76 11.688 53.784 11.88 ;
    END
  END q[278]
  PIN q[279]
    DIRECTION OUTPUT ;
    USE SIGNAL ;
    PORT
      LAYER M5 ;
        RECT  53.952 11.688 53.976 11.88 ;
    END
  END q[279]
  PIN q[27]
    DIRECTION OUTPUT ;
    USE SIGNAL ;
    PORT
      LAYER M5 ;
        RECT  5.568 11.688 5.592 11.88 ;
    END
  END q[27]
  PIN q[280]
    DIRECTION OUTPUT ;
    USE SIGNAL ;
    PORT
      LAYER M5 ;
        RECT  54.144 11.688 54.168 11.88 ;
    END
  END q[280]
  PIN q[281]
    DIRECTION OUTPUT ;
    USE SIGNAL ;
    PORT
      LAYER M5 ;
        RECT  54.336 11.688 54.36 11.88 ;
    END
  END q[281]
  PIN q[282]
    DIRECTION OUTPUT ;
    USE SIGNAL ;
    PORT
      LAYER M5 ;
        RECT  54.528 11.688 54.552 11.88 ;
    END
  END q[282]
  PIN q[283]
    DIRECTION OUTPUT ;
    USE SIGNAL ;
    PORT
      LAYER M5 ;
        RECT  54.72 11.688 54.744 11.88 ;
    END
  END q[283]
  PIN q[284]
    DIRECTION OUTPUT ;
    USE SIGNAL ;
    PORT
      LAYER M5 ;
        RECT  54.912 11.688 54.936 11.88 ;
    END
  END q[284]
  PIN q[285]
    DIRECTION OUTPUT ;
    USE SIGNAL ;
    PORT
      LAYER M5 ;
        RECT  55.104 11.688 55.128 11.88 ;
    END
  END q[285]
  PIN q[286]
    DIRECTION OUTPUT ;
    USE SIGNAL ;
    PORT
      LAYER M5 ;
        RECT  55.296 11.688 55.32 11.88 ;
    END
  END q[286]
  PIN q[287]
    DIRECTION OUTPUT ;
    USE SIGNAL ;
    PORT
      LAYER M5 ;
        RECT  55.488 11.688 55.512 11.88 ;
    END
  END q[287]
  PIN q[288]
    DIRECTION OUTPUT ;
    USE SIGNAL ;
    PORT
      LAYER M5 ;
        RECT  55.68 11.688 55.704 11.88 ;
    END
  END q[288]
  PIN q[289]
    DIRECTION OUTPUT ;
    USE SIGNAL ;
    PORT
      LAYER M5 ;
        RECT  55.872 11.688 55.896 11.88 ;
    END
  END q[289]
  PIN q[28]
    DIRECTION OUTPUT ;
    USE SIGNAL ;
    PORT
      LAYER M5 ;
        RECT  5.76 11.688 5.784 11.88 ;
    END
  END q[28]
  PIN q[290]
    DIRECTION OUTPUT ;
    USE SIGNAL ;
    PORT
      LAYER M5 ;
        RECT  56.064 11.688 56.088 11.88 ;
    END
  END q[290]
  PIN q[291]
    DIRECTION OUTPUT ;
    USE SIGNAL ;
    PORT
      LAYER M5 ;
        RECT  56.256 11.688 56.28 11.88 ;
    END
  END q[291]
  PIN q[292]
    DIRECTION OUTPUT ;
    USE SIGNAL ;
    PORT
      LAYER M5 ;
        RECT  56.448 11.688 56.472 11.88 ;
    END
  END q[292]
  PIN q[293]
    DIRECTION OUTPUT ;
    USE SIGNAL ;
    PORT
      LAYER M5 ;
        RECT  56.64 11.688 56.664 11.88 ;
    END
  END q[293]
  PIN q[294]
    DIRECTION OUTPUT ;
    USE SIGNAL ;
    PORT
      LAYER M5 ;
        RECT  56.832 11.688 56.856 11.88 ;
    END
  END q[294]
  PIN q[295]
    DIRECTION OUTPUT ;
    USE SIGNAL ;
    PORT
      LAYER M5 ;
        RECT  57.024 11.688 57.048 11.88 ;
    END
  END q[295]
  PIN q[296]
    DIRECTION OUTPUT ;
    USE SIGNAL ;
    PORT
      LAYER M5 ;
        RECT  57.216 11.688 57.24 11.88 ;
    END
  END q[296]
  PIN q[297]
    DIRECTION OUTPUT ;
    USE SIGNAL ;
    PORT
      LAYER M5 ;
        RECT  57.408 11.688 57.432 11.88 ;
    END
  END q[297]
  PIN q[298]
    DIRECTION OUTPUT ;
    USE SIGNAL ;
    PORT
      LAYER M5 ;
        RECT  57.6 11.688 57.624 11.88 ;
    END
  END q[298]
  PIN q[299]
    DIRECTION OUTPUT ;
    USE SIGNAL ;
    PORT
      LAYER M5 ;
        RECT  57.792 11.688 57.816 11.88 ;
    END
  END q[299]
  PIN q[29]
    DIRECTION OUTPUT ;
    USE SIGNAL ;
    PORT
      LAYER M5 ;
        RECT  5.952 11.688 5.976 11.88 ;
    END
  END q[29]
  PIN q[2]
    DIRECTION OUTPUT ;
    USE SIGNAL ;
    PORT
      LAYER M5 ;
        RECT  0.768 11.688 0.792 11.88 ;
    END
  END q[2]
  PIN q[300]
    DIRECTION OUTPUT ;
    USE SIGNAL ;
    PORT
      LAYER M5 ;
        RECT  57.984 11.688 58.008 11.88 ;
    END
  END q[300]
  PIN q[301]
    DIRECTION OUTPUT ;
    USE SIGNAL ;
    PORT
      LAYER M5 ;
        RECT  58.176 11.688 58.2 11.88 ;
    END
  END q[301]
  PIN q[302]
    DIRECTION OUTPUT ;
    USE SIGNAL ;
    PORT
      LAYER M5 ;
        RECT  58.368 11.688 58.392 11.88 ;
    END
  END q[302]
  PIN q[303]
    DIRECTION OUTPUT ;
    USE SIGNAL ;
    PORT
      LAYER M5 ;
        RECT  58.56 11.688 58.584 11.88 ;
    END
  END q[303]
  PIN q[304]
    DIRECTION OUTPUT ;
    USE SIGNAL ;
    PORT
      LAYER M5 ;
        RECT  58.752 11.688 58.776 11.88 ;
    END
  END q[304]
  PIN q[305]
    DIRECTION OUTPUT ;
    USE SIGNAL ;
    PORT
      LAYER M5 ;
        RECT  58.944 11.688 58.968 11.88 ;
    END
  END q[305]
  PIN q[306]
    DIRECTION OUTPUT ;
    USE SIGNAL ;
    PORT
      LAYER M5 ;
        RECT  59.136 11.688 59.16 11.88 ;
    END
  END q[306]
  PIN q[307]
    DIRECTION OUTPUT ;
    USE SIGNAL ;
    PORT
      LAYER M5 ;
        RECT  59.328 11.688 59.352 11.88 ;
    END
  END q[307]
  PIN q[308]
    DIRECTION OUTPUT ;
    USE SIGNAL ;
    PORT
      LAYER M5 ;
        RECT  59.52 11.688 59.544 11.88 ;
    END
  END q[308]
  PIN q[309]
    DIRECTION OUTPUT ;
    USE SIGNAL ;
    PORT
      LAYER M5 ;
        RECT  59.712 11.688 59.736 11.88 ;
    END
  END q[309]
  PIN q[30]
    DIRECTION OUTPUT ;
    USE SIGNAL ;
    PORT
      LAYER M5 ;
        RECT  6.144 11.688 6.168 11.88 ;
    END
  END q[30]
  PIN q[310]
    DIRECTION OUTPUT ;
    USE SIGNAL ;
    PORT
      LAYER M5 ;
        RECT  59.904 11.688 59.928 11.88 ;
    END
  END q[310]
  PIN q[311]
    DIRECTION OUTPUT ;
    USE SIGNAL ;
    PORT
      LAYER M5 ;
        RECT  60.096 11.688 60.12 11.88 ;
    END
  END q[311]
  PIN q[312]
    DIRECTION OUTPUT ;
    USE SIGNAL ;
    PORT
      LAYER M5 ;
        RECT  60.288 11.688 60.312 11.88 ;
    END
  END q[312]
  PIN q[313]
    DIRECTION OUTPUT ;
    USE SIGNAL ;
    PORT
      LAYER M5 ;
        RECT  60.48 11.688 60.504 11.88 ;
    END
  END q[313]
  PIN q[314]
    DIRECTION OUTPUT ;
    USE SIGNAL ;
    PORT
      LAYER M5 ;
        RECT  60.672 11.688 60.696 11.88 ;
    END
  END q[314]
  PIN q[315]
    DIRECTION OUTPUT ;
    USE SIGNAL ;
    PORT
      LAYER M5 ;
        RECT  60.864 11.688 60.888 11.88 ;
    END
  END q[315]
  PIN q[316]
    DIRECTION OUTPUT ;
    USE SIGNAL ;
    PORT
      LAYER M5 ;
        RECT  61.056 11.688 61.08 11.88 ;
    END
  END q[316]
  PIN q[317]
    DIRECTION OUTPUT ;
    USE SIGNAL ;
    PORT
      LAYER M5 ;
        RECT  61.248 11.688 61.272 11.88 ;
    END
  END q[317]
  PIN q[318]
    DIRECTION OUTPUT ;
    USE SIGNAL ;
    PORT
      LAYER M5 ;
        RECT  61.44 11.688 61.464 11.88 ;
    END
  END q[318]
  PIN q[319]
    DIRECTION OUTPUT ;
    USE SIGNAL ;
    PORT
      LAYER M5 ;
        RECT  61.632 11.688 61.656 11.88 ;
    END
  END q[319]
  PIN q[31]
    DIRECTION OUTPUT ;
    USE SIGNAL ;
    PORT
      LAYER M5 ;
        RECT  6.336 11.688 6.36 11.88 ;
    END
  END q[31]
  PIN q[320]
    DIRECTION OUTPUT ;
    USE SIGNAL ;
    PORT
      LAYER M5 ;
        RECT  61.824 11.688 61.848 11.88 ;
    END
  END q[320]
  PIN q[321]
    DIRECTION OUTPUT ;
    USE SIGNAL ;
    PORT
      LAYER M5 ;
        RECT  62.016 11.688 62.04 11.88 ;
    END
  END q[321]
  PIN q[322]
    DIRECTION OUTPUT ;
    USE SIGNAL ;
    PORT
      LAYER M5 ;
        RECT  62.208 11.688 62.232 11.88 ;
    END
  END q[322]
  PIN q[323]
    DIRECTION OUTPUT ;
    USE SIGNAL ;
    PORT
      LAYER M5 ;
        RECT  62.4 11.688 62.424 11.88 ;
    END
  END q[323]
  PIN q[324]
    DIRECTION OUTPUT ;
    USE SIGNAL ;
    PORT
      LAYER M5 ;
        RECT  62.592 11.688 62.616 11.88 ;
    END
  END q[324]
  PIN q[325]
    DIRECTION OUTPUT ;
    USE SIGNAL ;
    PORT
      LAYER M5 ;
        RECT  62.784 11.688 62.808 11.88 ;
    END
  END q[325]
  PIN q[326]
    DIRECTION OUTPUT ;
    USE SIGNAL ;
    PORT
      LAYER M5 ;
        RECT  62.976 11.688 63 11.88 ;
    END
  END q[326]
  PIN q[327]
    DIRECTION OUTPUT ;
    USE SIGNAL ;
    PORT
      LAYER M5 ;
        RECT  63.168 11.688 63.192 11.88 ;
    END
  END q[327]
  PIN q[328]
    DIRECTION OUTPUT ;
    USE SIGNAL ;
    PORT
      LAYER M5 ;
        RECT  63.36 11.688 63.384 11.88 ;
    END
  END q[328]
  PIN q[329]
    DIRECTION OUTPUT ;
    USE SIGNAL ;
    PORT
      LAYER M5 ;
        RECT  63.552 11.688 63.576 11.88 ;
    END
  END q[329]
  PIN q[32]
    DIRECTION OUTPUT ;
    USE SIGNAL ;
    PORT
      LAYER M5 ;
        RECT  6.528 11.688 6.552 11.88 ;
    END
  END q[32]
  PIN q[330]
    DIRECTION OUTPUT ;
    USE SIGNAL ;
    PORT
      LAYER M5 ;
        RECT  63.744 11.688 63.768 11.88 ;
    END
  END q[330]
  PIN q[331]
    DIRECTION OUTPUT ;
    USE SIGNAL ;
    PORT
      LAYER M5 ;
        RECT  63.936 11.688 63.96 11.88 ;
    END
  END q[331]
  PIN q[332]
    DIRECTION OUTPUT ;
    USE SIGNAL ;
    PORT
      LAYER M5 ;
        RECT  64.128 11.688 64.152 11.88 ;
    END
  END q[332]
  PIN q[333]
    DIRECTION OUTPUT ;
    USE SIGNAL ;
    PORT
      LAYER M5 ;
        RECT  64.32 11.688 64.344 11.88 ;
    END
  END q[333]
  PIN q[334]
    DIRECTION OUTPUT ;
    USE SIGNAL ;
    PORT
      LAYER M5 ;
        RECT  64.512 11.688 64.536 11.88 ;
    END
  END q[334]
  PIN q[335]
    DIRECTION OUTPUT ;
    USE SIGNAL ;
    PORT
      LAYER M5 ;
        RECT  64.704 11.688 64.728 11.88 ;
    END
  END q[335]
  PIN q[336]
    DIRECTION OUTPUT ;
    USE SIGNAL ;
    PORT
      LAYER M5 ;
        RECT  64.896 11.688 64.92 11.88 ;
    END
  END q[336]
  PIN q[337]
    DIRECTION OUTPUT ;
    USE SIGNAL ;
    PORT
      LAYER M5 ;
        RECT  65.088 11.688 65.112 11.88 ;
    END
  END q[337]
  PIN q[338]
    DIRECTION OUTPUT ;
    USE SIGNAL ;
    PORT
      LAYER M5 ;
        RECT  65.28 11.688 65.304 11.88 ;
    END
  END q[338]
  PIN q[339]
    DIRECTION OUTPUT ;
    USE SIGNAL ;
    PORT
      LAYER M5 ;
        RECT  65.472 11.688 65.496 11.88 ;
    END
  END q[339]
  PIN q[33]
    DIRECTION OUTPUT ;
    USE SIGNAL ;
    PORT
      LAYER M5 ;
        RECT  6.72 11.688 6.744 11.88 ;
    END
  END q[33]
  PIN q[340]
    DIRECTION OUTPUT ;
    USE SIGNAL ;
    PORT
      LAYER M5 ;
        RECT  65.664 11.688 65.688 11.88 ;
    END
  END q[340]
  PIN q[341]
    DIRECTION OUTPUT ;
    USE SIGNAL ;
    PORT
      LAYER M5 ;
        RECT  65.856 11.688 65.88 11.88 ;
    END
  END q[341]
  PIN q[342]
    DIRECTION OUTPUT ;
    USE SIGNAL ;
    PORT
      LAYER M5 ;
        RECT  66.048 11.688 66.072 11.88 ;
    END
  END q[342]
  PIN q[343]
    DIRECTION OUTPUT ;
    USE SIGNAL ;
    PORT
      LAYER M5 ;
        RECT  66.24 11.688 66.264 11.88 ;
    END
  END q[343]
  PIN q[344]
    DIRECTION OUTPUT ;
    USE SIGNAL ;
    PORT
      LAYER M5 ;
        RECT  66.432 11.688 66.456 11.88 ;
    END
  END q[344]
  PIN q[345]
    DIRECTION OUTPUT ;
    USE SIGNAL ;
    PORT
      LAYER M5 ;
        RECT  66.624 11.688 66.648 11.88 ;
    END
  END q[345]
  PIN q[346]
    DIRECTION OUTPUT ;
    USE SIGNAL ;
    PORT
      LAYER M5 ;
        RECT  66.816 11.688 66.84 11.88 ;
    END
  END q[346]
  PIN q[347]
    DIRECTION OUTPUT ;
    USE SIGNAL ;
    PORT
      LAYER M5 ;
        RECT  67.008 11.688 67.032 11.88 ;
    END
  END q[347]
  PIN q[348]
    DIRECTION OUTPUT ;
    USE SIGNAL ;
    PORT
      LAYER M5 ;
        RECT  67.2 11.688 67.224 11.88 ;
    END
  END q[348]
  PIN q[349]
    DIRECTION OUTPUT ;
    USE SIGNAL ;
    PORT
      LAYER M5 ;
        RECT  67.392 11.688 67.416 11.88 ;
    END
  END q[349]
  PIN q[34]
    DIRECTION OUTPUT ;
    USE SIGNAL ;
    PORT
      LAYER M5 ;
        RECT  6.912 11.688 6.936 11.88 ;
    END
  END q[34]
  PIN q[350]
    DIRECTION OUTPUT ;
    USE SIGNAL ;
    PORT
      LAYER M5 ;
        RECT  67.584 11.688 67.608 11.88 ;
    END
  END q[350]
  PIN q[351]
    DIRECTION OUTPUT ;
    USE SIGNAL ;
    PORT
      LAYER M5 ;
        RECT  67.776 11.688 67.8 11.88 ;
    END
  END q[351]
  PIN q[352]
    DIRECTION OUTPUT ;
    USE SIGNAL ;
    PORT
      LAYER M5 ;
        RECT  67.968 11.688 67.992 11.88 ;
    END
  END q[352]
  PIN q[353]
    DIRECTION OUTPUT ;
    USE SIGNAL ;
    PORT
      LAYER M5 ;
        RECT  68.16 11.688 68.184 11.88 ;
    END
  END q[353]
  PIN q[354]
    DIRECTION OUTPUT ;
    USE SIGNAL ;
    PORT
      LAYER M5 ;
        RECT  68.352 11.688 68.376 11.88 ;
    END
  END q[354]
  PIN q[355]
    DIRECTION OUTPUT ;
    USE SIGNAL ;
    PORT
      LAYER M5 ;
        RECT  68.544 11.688 68.568 11.88 ;
    END
  END q[355]
  PIN q[356]
    DIRECTION OUTPUT ;
    USE SIGNAL ;
    PORT
      LAYER M5 ;
        RECT  68.736 11.688 68.76 11.88 ;
    END
  END q[356]
  PIN q[357]
    DIRECTION OUTPUT ;
    USE SIGNAL ;
    PORT
      LAYER M5 ;
        RECT  68.928 11.688 68.952 11.88 ;
    END
  END q[357]
  PIN q[358]
    DIRECTION OUTPUT ;
    USE SIGNAL ;
    PORT
      LAYER M5 ;
        RECT  69.12 11.688 69.144 11.88 ;
    END
  END q[358]
  PIN q[359]
    DIRECTION OUTPUT ;
    USE SIGNAL ;
    PORT
      LAYER M5 ;
        RECT  69.312 11.688 69.336 11.88 ;
    END
  END q[359]
  PIN q[35]
    DIRECTION OUTPUT ;
    USE SIGNAL ;
    PORT
      LAYER M5 ;
        RECT  7.104 11.688 7.128 11.88 ;
    END
  END q[35]
  PIN q[360]
    DIRECTION OUTPUT ;
    USE SIGNAL ;
    PORT
      LAYER M5 ;
        RECT  69.504 11.688 69.528 11.88 ;
    END
  END q[360]
  PIN q[361]
    DIRECTION OUTPUT ;
    USE SIGNAL ;
    PORT
      LAYER M5 ;
        RECT  69.696 11.688 69.72 11.88 ;
    END
  END q[361]
  PIN q[362]
    DIRECTION OUTPUT ;
    USE SIGNAL ;
    PORT
      LAYER M5 ;
        RECT  69.888 11.688 69.912 11.88 ;
    END
  END q[362]
  PIN q[363]
    DIRECTION OUTPUT ;
    USE SIGNAL ;
    PORT
      LAYER M5 ;
        RECT  70.08 11.688 70.104 11.88 ;
    END
  END q[363]
  PIN q[364]
    DIRECTION OUTPUT ;
    USE SIGNAL ;
    PORT
      LAYER M5 ;
        RECT  70.272 11.688 70.296 11.88 ;
    END
  END q[364]
  PIN q[365]
    DIRECTION OUTPUT ;
    USE SIGNAL ;
    PORT
      LAYER M5 ;
        RECT  70.464 11.688 70.488 11.88 ;
    END
  END q[365]
  PIN q[366]
    DIRECTION OUTPUT ;
    USE SIGNAL ;
    PORT
      LAYER M5 ;
        RECT  70.656 11.688 70.68 11.88 ;
    END
  END q[366]
  PIN q[367]
    DIRECTION OUTPUT ;
    USE SIGNAL ;
    PORT
      LAYER M5 ;
        RECT  70.848 11.688 70.872 11.88 ;
    END
  END q[367]
  PIN q[368]
    DIRECTION OUTPUT ;
    USE SIGNAL ;
    PORT
      LAYER M5 ;
        RECT  71.04 11.688 71.064 11.88 ;
    END
  END q[368]
  PIN q[369]
    DIRECTION OUTPUT ;
    USE SIGNAL ;
    PORT
      LAYER M5 ;
        RECT  71.232 11.688 71.256 11.88 ;
    END
  END q[369]
  PIN q[36]
    DIRECTION OUTPUT ;
    USE SIGNAL ;
    PORT
      LAYER M5 ;
        RECT  7.296 11.688 7.32 11.88 ;
    END
  END q[36]
  PIN q[370]
    DIRECTION OUTPUT ;
    USE SIGNAL ;
    PORT
      LAYER M5 ;
        RECT  71.424 11.688 71.448 11.88 ;
    END
  END q[370]
  PIN q[371]
    DIRECTION OUTPUT ;
    USE SIGNAL ;
    PORT
      LAYER M5 ;
        RECT  71.616 11.688 71.64 11.88 ;
    END
  END q[371]
  PIN q[372]
    DIRECTION OUTPUT ;
    USE SIGNAL ;
    PORT
      LAYER M5 ;
        RECT  71.808 11.688 71.832 11.88 ;
    END
  END q[372]
  PIN q[373]
    DIRECTION OUTPUT ;
    USE SIGNAL ;
    PORT
      LAYER M5 ;
        RECT  72 11.688 72.024 11.88 ;
    END
  END q[373]
  PIN q[374]
    DIRECTION OUTPUT ;
    USE SIGNAL ;
    PORT
      LAYER M5 ;
        RECT  72.192 11.688 72.216 11.88 ;
    END
  END q[374]
  PIN q[375]
    DIRECTION OUTPUT ;
    USE SIGNAL ;
    PORT
      LAYER M5 ;
        RECT  72.384 11.688 72.408 11.88 ;
    END
  END q[375]
  PIN q[376]
    DIRECTION OUTPUT ;
    USE SIGNAL ;
    PORT
      LAYER M5 ;
        RECT  72.576 11.688 72.6 11.88 ;
    END
  END q[376]
  PIN q[377]
    DIRECTION OUTPUT ;
    USE SIGNAL ;
    PORT
      LAYER M5 ;
        RECT  72.768 11.688 72.792 11.88 ;
    END
  END q[377]
  PIN q[378]
    DIRECTION OUTPUT ;
    USE SIGNAL ;
    PORT
      LAYER M5 ;
        RECT  72.96 11.688 72.984 11.88 ;
    END
  END q[378]
  PIN q[379]
    DIRECTION OUTPUT ;
    USE SIGNAL ;
    PORT
      LAYER M5 ;
        RECT  73.152 11.688 73.176 11.88 ;
    END
  END q[379]
  PIN q[37]
    DIRECTION OUTPUT ;
    USE SIGNAL ;
    PORT
      LAYER M5 ;
        RECT  7.488 11.688 7.512 11.88 ;
    END
  END q[37]
  PIN q[380]
    DIRECTION OUTPUT ;
    USE SIGNAL ;
    PORT
      LAYER M5 ;
        RECT  73.344 11.688 73.368 11.88 ;
    END
  END q[380]
  PIN q[381]
    DIRECTION OUTPUT ;
    USE SIGNAL ;
    PORT
      LAYER M5 ;
        RECT  73.536 11.688 73.56 11.88 ;
    END
  END q[381]
  PIN q[382]
    DIRECTION OUTPUT ;
    USE SIGNAL ;
    PORT
      LAYER M5 ;
        RECT  73.728 11.688 73.752 11.88 ;
    END
  END q[382]
  PIN q[383]
    DIRECTION OUTPUT ;
    USE SIGNAL ;
    PORT
      LAYER M5 ;
        RECT  73.92 11.688 73.944 11.88 ;
    END
  END q[383]
  PIN q[384]
    DIRECTION OUTPUT ;
    USE SIGNAL ;
    PORT
      LAYER M5 ;
        RECT  74.112 11.688 74.136 11.88 ;
    END
  END q[384]
  PIN q[385]
    DIRECTION OUTPUT ;
    USE SIGNAL ;
    PORT
      LAYER M5 ;
        RECT  74.304 11.688 74.328 11.88 ;
    END
  END q[385]
  PIN q[386]
    DIRECTION OUTPUT ;
    USE SIGNAL ;
    PORT
      LAYER M5 ;
        RECT  74.496 11.688 74.52 11.88 ;
    END
  END q[386]
  PIN q[387]
    DIRECTION OUTPUT ;
    USE SIGNAL ;
    PORT
      LAYER M5 ;
        RECT  74.688 11.688 74.712 11.88 ;
    END
  END q[387]
  PIN q[388]
    DIRECTION OUTPUT ;
    USE SIGNAL ;
    PORT
      LAYER M5 ;
        RECT  74.88 11.688 74.904 11.88 ;
    END
  END q[388]
  PIN q[389]
    DIRECTION OUTPUT ;
    USE SIGNAL ;
    PORT
      LAYER M5 ;
        RECT  75.072 11.688 75.096 11.88 ;
    END
  END q[389]
  PIN q[38]
    DIRECTION OUTPUT ;
    USE SIGNAL ;
    PORT
      LAYER M5 ;
        RECT  7.68 11.688 7.704 11.88 ;
    END
  END q[38]
  PIN q[390]
    DIRECTION OUTPUT ;
    USE SIGNAL ;
    PORT
      LAYER M5 ;
        RECT  75.264 11.688 75.288 11.88 ;
    END
  END q[390]
  PIN q[391]
    DIRECTION OUTPUT ;
    USE SIGNAL ;
    PORT
      LAYER M5 ;
        RECT  75.456 11.688 75.48 11.88 ;
    END
  END q[391]
  PIN q[392]
    DIRECTION OUTPUT ;
    USE SIGNAL ;
    PORT
      LAYER M5 ;
        RECT  75.648 11.688 75.672 11.88 ;
    END
  END q[392]
  PIN q[393]
    DIRECTION OUTPUT ;
    USE SIGNAL ;
    PORT
      LAYER M5 ;
        RECT  75.84 11.688 75.864 11.88 ;
    END
  END q[393]
  PIN q[394]
    DIRECTION OUTPUT ;
    USE SIGNAL ;
    PORT
      LAYER M5 ;
        RECT  76.032 11.688 76.056 11.88 ;
    END
  END q[394]
  PIN q[395]
    DIRECTION OUTPUT ;
    USE SIGNAL ;
    PORT
      LAYER M5 ;
        RECT  76.224 11.688 76.248 11.88 ;
    END
  END q[395]
  PIN q[396]
    DIRECTION OUTPUT ;
    USE SIGNAL ;
    PORT
      LAYER M5 ;
        RECT  76.416 11.688 76.44 11.88 ;
    END
  END q[396]
  PIN q[397]
    DIRECTION OUTPUT ;
    USE SIGNAL ;
    PORT
      LAYER M5 ;
        RECT  76.608 11.688 76.632 11.88 ;
    END
  END q[397]
  PIN q[398]
    DIRECTION OUTPUT ;
    USE SIGNAL ;
    PORT
      LAYER M5 ;
        RECT  76.8 11.688 76.824 11.88 ;
    END
  END q[398]
  PIN q[399]
    DIRECTION OUTPUT ;
    USE SIGNAL ;
    PORT
      LAYER M5 ;
        RECT  76.992 11.688 77.016 11.88 ;
    END
  END q[399]
  PIN q[39]
    DIRECTION OUTPUT ;
    USE SIGNAL ;
    PORT
      LAYER M5 ;
        RECT  7.872 11.688 7.896 11.88 ;
    END
  END q[39]
  PIN q[3]
    DIRECTION OUTPUT ;
    USE SIGNAL ;
    PORT
      LAYER M5 ;
        RECT  0.96 11.688 0.984 11.88 ;
    END
  END q[3]
  PIN q[400]
    DIRECTION OUTPUT ;
    USE SIGNAL ;
    PORT
      LAYER M5 ;
        RECT  77.184 11.688 77.208 11.88 ;
    END
  END q[400]
  PIN q[401]
    DIRECTION OUTPUT ;
    USE SIGNAL ;
    PORT
      LAYER M5 ;
        RECT  77.376 11.688 77.4 11.88 ;
    END
  END q[401]
  PIN q[402]
    DIRECTION OUTPUT ;
    USE SIGNAL ;
    PORT
      LAYER M5 ;
        RECT  77.568 11.688 77.592 11.88 ;
    END
  END q[402]
  PIN q[403]
    DIRECTION OUTPUT ;
    USE SIGNAL ;
    PORT
      LAYER M5 ;
        RECT  77.76 11.688 77.784 11.88 ;
    END
  END q[403]
  PIN q[404]
    DIRECTION OUTPUT ;
    USE SIGNAL ;
    PORT
      LAYER M5 ;
        RECT  77.952 11.688 77.976 11.88 ;
    END
  END q[404]
  PIN q[405]
    DIRECTION OUTPUT ;
    USE SIGNAL ;
    PORT
      LAYER M5 ;
        RECT  78.144 11.688 78.168 11.88 ;
    END
  END q[405]
  PIN q[406]
    DIRECTION OUTPUT ;
    USE SIGNAL ;
    PORT
      LAYER M5 ;
        RECT  78.336 11.688 78.36 11.88 ;
    END
  END q[406]
  PIN q[407]
    DIRECTION OUTPUT ;
    USE SIGNAL ;
    PORT
      LAYER M5 ;
        RECT  78.528 11.688 78.552 11.88 ;
    END
  END q[407]
  PIN q[408]
    DIRECTION OUTPUT ;
    USE SIGNAL ;
    PORT
      LAYER M5 ;
        RECT  78.72 11.688 78.744 11.88 ;
    END
  END q[408]
  PIN q[409]
    DIRECTION OUTPUT ;
    USE SIGNAL ;
    PORT
      LAYER M5 ;
        RECT  78.912 11.688 78.936 11.88 ;
    END
  END q[409]
  PIN q[40]
    DIRECTION OUTPUT ;
    USE SIGNAL ;
    PORT
      LAYER M5 ;
        RECT  8.064 11.688 8.088 11.88 ;
    END
  END q[40]
  PIN q[410]
    DIRECTION OUTPUT ;
    USE SIGNAL ;
    PORT
      LAYER M5 ;
        RECT  79.104 11.688 79.128 11.88 ;
    END
  END q[410]
  PIN q[411]
    DIRECTION OUTPUT ;
    USE SIGNAL ;
    PORT
      LAYER M5 ;
        RECT  79.296 11.688 79.32 11.88 ;
    END
  END q[411]
  PIN q[412]
    DIRECTION OUTPUT ;
    USE SIGNAL ;
    PORT
      LAYER M5 ;
        RECT  79.488 11.688 79.512 11.88 ;
    END
  END q[412]
  PIN q[413]
    DIRECTION OUTPUT ;
    USE SIGNAL ;
    PORT
      LAYER M5 ;
        RECT  79.68 11.688 79.704 11.88 ;
    END
  END q[413]
  PIN q[414]
    DIRECTION OUTPUT ;
    USE SIGNAL ;
    PORT
      LAYER M5 ;
        RECT  79.872 11.688 79.896 11.88 ;
    END
  END q[414]
  PIN q[415]
    DIRECTION OUTPUT ;
    USE SIGNAL ;
    PORT
      LAYER M5 ;
        RECT  80.064 11.688 80.088 11.88 ;
    END
  END q[415]
  PIN q[416]
    DIRECTION OUTPUT ;
    USE SIGNAL ;
    PORT
      LAYER M5 ;
        RECT  80.256 11.688 80.28 11.88 ;
    END
  END q[416]
  PIN q[417]
    DIRECTION OUTPUT ;
    USE SIGNAL ;
    PORT
      LAYER M5 ;
        RECT  80.448 11.688 80.472 11.88 ;
    END
  END q[417]
  PIN q[418]
    DIRECTION OUTPUT ;
    USE SIGNAL ;
    PORT
      LAYER M5 ;
        RECT  80.64 11.688 80.664 11.88 ;
    END
  END q[418]
  PIN q[419]
    DIRECTION OUTPUT ;
    USE SIGNAL ;
    PORT
      LAYER M5 ;
        RECT  80.832 11.688 80.856 11.88 ;
    END
  END q[419]
  PIN q[41]
    DIRECTION OUTPUT ;
    USE SIGNAL ;
    PORT
      LAYER M5 ;
        RECT  8.256 11.688 8.28 11.88 ;
    END
  END q[41]
  PIN q[420]
    DIRECTION OUTPUT ;
    USE SIGNAL ;
    PORT
      LAYER M5 ;
        RECT  81.024 11.688 81.048 11.88 ;
    END
  END q[420]
  PIN q[421]
    DIRECTION OUTPUT ;
    USE SIGNAL ;
    PORT
      LAYER M5 ;
        RECT  81.216 11.688 81.24 11.88 ;
    END
  END q[421]
  PIN q[422]
    DIRECTION OUTPUT ;
    USE SIGNAL ;
    PORT
      LAYER M5 ;
        RECT  81.408 11.688 81.432 11.88 ;
    END
  END q[422]
  PIN q[423]
    DIRECTION OUTPUT ;
    USE SIGNAL ;
    PORT
      LAYER M5 ;
        RECT  81.6 11.688 81.624 11.88 ;
    END
  END q[423]
  PIN q[424]
    DIRECTION OUTPUT ;
    USE SIGNAL ;
    PORT
      LAYER M5 ;
        RECT  81.792 11.688 81.816 11.88 ;
    END
  END q[424]
  PIN q[425]
    DIRECTION OUTPUT ;
    USE SIGNAL ;
    PORT
      LAYER M5 ;
        RECT  81.984 11.688 82.008 11.88 ;
    END
  END q[425]
  PIN q[426]
    DIRECTION OUTPUT ;
    USE SIGNAL ;
    PORT
      LAYER M5 ;
        RECT  82.176 11.688 82.2 11.88 ;
    END
  END q[426]
  PIN q[427]
    DIRECTION OUTPUT ;
    USE SIGNAL ;
    PORT
      LAYER M5 ;
        RECT  82.368 11.688 82.392 11.88 ;
    END
  END q[427]
  PIN q[428]
    DIRECTION OUTPUT ;
    USE SIGNAL ;
    PORT
      LAYER M5 ;
        RECT  82.56 11.688 82.584 11.88 ;
    END
  END q[428]
  PIN q[429]
    DIRECTION OUTPUT ;
    USE SIGNAL ;
    PORT
      LAYER M5 ;
        RECT  82.752 11.688 82.776 11.88 ;
    END
  END q[429]
  PIN q[42]
    DIRECTION OUTPUT ;
    USE SIGNAL ;
    PORT
      LAYER M5 ;
        RECT  8.448 11.688 8.472 11.88 ;
    END
  END q[42]
  PIN q[430]
    DIRECTION OUTPUT ;
    USE SIGNAL ;
    PORT
      LAYER M5 ;
        RECT  82.944 11.688 82.968 11.88 ;
    END
  END q[430]
  PIN q[431]
    DIRECTION OUTPUT ;
    USE SIGNAL ;
    PORT
      LAYER M5 ;
        RECT  83.136 11.688 83.16 11.88 ;
    END
  END q[431]
  PIN q[432]
    DIRECTION OUTPUT ;
    USE SIGNAL ;
    PORT
      LAYER M5 ;
        RECT  83.328 11.688 83.352 11.88 ;
    END
  END q[432]
  PIN q[433]
    DIRECTION OUTPUT ;
    USE SIGNAL ;
    PORT
      LAYER M5 ;
        RECT  83.52 11.688 83.544 11.88 ;
    END
  END q[433]
  PIN q[434]
    DIRECTION OUTPUT ;
    USE SIGNAL ;
    PORT
      LAYER M5 ;
        RECT  83.712 11.688 83.736 11.88 ;
    END
  END q[434]
  PIN q[435]
    DIRECTION OUTPUT ;
    USE SIGNAL ;
    PORT
      LAYER M5 ;
        RECT  83.904 11.688 83.928 11.88 ;
    END
  END q[435]
  PIN q[436]
    DIRECTION OUTPUT ;
    USE SIGNAL ;
    PORT
      LAYER M5 ;
        RECT  84.096 11.688 84.12 11.88 ;
    END
  END q[436]
  PIN q[437]
    DIRECTION OUTPUT ;
    USE SIGNAL ;
    PORT
      LAYER M5 ;
        RECT  84.288 11.688 84.312 11.88 ;
    END
  END q[437]
  PIN q[438]
    DIRECTION OUTPUT ;
    USE SIGNAL ;
    PORT
      LAYER M5 ;
        RECT  84.48 11.688 84.504 11.88 ;
    END
  END q[438]
  PIN q[439]
    DIRECTION OUTPUT ;
    USE SIGNAL ;
    PORT
      LAYER M5 ;
        RECT  84.672 11.688 84.696 11.88 ;
    END
  END q[439]
  PIN q[43]
    DIRECTION OUTPUT ;
    USE SIGNAL ;
    PORT
      LAYER M5 ;
        RECT  8.64 11.688 8.664 11.88 ;
    END
  END q[43]
  PIN q[440]
    DIRECTION OUTPUT ;
    USE SIGNAL ;
    PORT
      LAYER M5 ;
        RECT  84.864 11.688 84.888 11.88 ;
    END
  END q[440]
  PIN q[441]
    DIRECTION OUTPUT ;
    USE SIGNAL ;
    PORT
      LAYER M5 ;
        RECT  85.056 11.688 85.08 11.88 ;
    END
  END q[441]
  PIN q[442]
    DIRECTION OUTPUT ;
    USE SIGNAL ;
    PORT
      LAYER M5 ;
        RECT  85.248 11.688 85.272 11.88 ;
    END
  END q[442]
  PIN q[443]
    DIRECTION OUTPUT ;
    USE SIGNAL ;
    PORT
      LAYER M5 ;
        RECT  85.44 11.688 85.464 11.88 ;
    END
  END q[443]
  PIN q[444]
    DIRECTION OUTPUT ;
    USE SIGNAL ;
    PORT
      LAYER M5 ;
        RECT  85.632 11.688 85.656 11.88 ;
    END
  END q[444]
  PIN q[445]
    DIRECTION OUTPUT ;
    USE SIGNAL ;
    PORT
      LAYER M5 ;
        RECT  85.824 11.688 85.848 11.88 ;
    END
  END q[445]
  PIN q[446]
    DIRECTION OUTPUT ;
    USE SIGNAL ;
    PORT
      LAYER M5 ;
        RECT  86.016 11.688 86.04 11.88 ;
    END
  END q[446]
  PIN q[447]
    DIRECTION OUTPUT ;
    USE SIGNAL ;
    PORT
      LAYER M5 ;
        RECT  86.208 11.688 86.232 11.88 ;
    END
  END q[447]
  PIN q[448]
    DIRECTION OUTPUT ;
    USE SIGNAL ;
    PORT
      LAYER M5 ;
        RECT  86.4 11.688 86.424 11.88 ;
    END
  END q[448]
  PIN q[449]
    DIRECTION OUTPUT ;
    USE SIGNAL ;
    PORT
      LAYER M5 ;
        RECT  86.592 11.688 86.616 11.88 ;
    END
  END q[449]
  PIN q[44]
    DIRECTION OUTPUT ;
    USE SIGNAL ;
    PORT
      LAYER M5 ;
        RECT  8.832 11.688 8.856 11.88 ;
    END
  END q[44]
  PIN q[450]
    DIRECTION OUTPUT ;
    USE SIGNAL ;
    PORT
      LAYER M5 ;
        RECT  86.784 11.688 86.808 11.88 ;
    END
  END q[450]
  PIN q[451]
    DIRECTION OUTPUT ;
    USE SIGNAL ;
    PORT
      LAYER M5 ;
        RECT  86.976 11.688 87 11.88 ;
    END
  END q[451]
  PIN q[452]
    DIRECTION OUTPUT ;
    USE SIGNAL ;
    PORT
      LAYER M5 ;
        RECT  87.168 11.688 87.192 11.88 ;
    END
  END q[452]
  PIN q[453]
    DIRECTION OUTPUT ;
    USE SIGNAL ;
    PORT
      LAYER M5 ;
        RECT  87.36 11.688 87.384 11.88 ;
    END
  END q[453]
  PIN q[454]
    DIRECTION OUTPUT ;
    USE SIGNAL ;
    PORT
      LAYER M5 ;
        RECT  87.552 11.688 87.576 11.88 ;
    END
  END q[454]
  PIN q[455]
    DIRECTION OUTPUT ;
    USE SIGNAL ;
    PORT
      LAYER M5 ;
        RECT  87.744 11.688 87.768 11.88 ;
    END
  END q[455]
  PIN q[456]
    DIRECTION OUTPUT ;
    USE SIGNAL ;
    PORT
      LAYER M5 ;
        RECT  87.936 11.688 87.96 11.88 ;
    END
  END q[456]
  PIN q[457]
    DIRECTION OUTPUT ;
    USE SIGNAL ;
    PORT
      LAYER M5 ;
        RECT  88.128 11.688 88.152 11.88 ;
    END
  END q[457]
  PIN q[458]
    DIRECTION OUTPUT ;
    USE SIGNAL ;
    PORT
      LAYER M5 ;
        RECT  88.32 11.688 88.344 11.88 ;
    END
  END q[458]
  PIN q[459]
    DIRECTION OUTPUT ;
    USE SIGNAL ;
    PORT
      LAYER M5 ;
        RECT  88.512 11.688 88.536 11.88 ;
    END
  END q[459]
  PIN q[45]
    DIRECTION OUTPUT ;
    USE SIGNAL ;
    PORT
      LAYER M5 ;
        RECT  9.024 11.688 9.048 11.88 ;
    END
  END q[45]
  PIN q[460]
    DIRECTION OUTPUT ;
    USE SIGNAL ;
    PORT
      LAYER M5 ;
        RECT  88.704 11.688 88.728 11.88 ;
    END
  END q[460]
  PIN q[461]
    DIRECTION OUTPUT ;
    USE SIGNAL ;
    PORT
      LAYER M5 ;
        RECT  88.896 11.688 88.92 11.88 ;
    END
  END q[461]
  PIN q[462]
    DIRECTION OUTPUT ;
    USE SIGNAL ;
    PORT
      LAYER M5 ;
        RECT  89.088 11.688 89.112 11.88 ;
    END
  END q[462]
  PIN q[463]
    DIRECTION OUTPUT ;
    USE SIGNAL ;
    PORT
      LAYER M5 ;
        RECT  89.28 11.688 89.304 11.88 ;
    END
  END q[463]
  PIN q[464]
    DIRECTION OUTPUT ;
    USE SIGNAL ;
    PORT
      LAYER M5 ;
        RECT  89.472 11.688 89.496 11.88 ;
    END
  END q[464]
  PIN q[465]
    DIRECTION OUTPUT ;
    USE SIGNAL ;
    PORT
      LAYER M5 ;
        RECT  89.664 11.688 89.688 11.88 ;
    END
  END q[465]
  PIN q[466]
    DIRECTION OUTPUT ;
    USE SIGNAL ;
    PORT
      LAYER M5 ;
        RECT  89.856 11.688 89.88 11.88 ;
    END
  END q[466]
  PIN q[467]
    DIRECTION OUTPUT ;
    USE SIGNAL ;
    PORT
      LAYER M5 ;
        RECT  90.048 11.688 90.072 11.88 ;
    END
  END q[467]
  PIN q[468]
    DIRECTION OUTPUT ;
    USE SIGNAL ;
    PORT
      LAYER M5 ;
        RECT  90.24 11.688 90.264 11.88 ;
    END
  END q[468]
  PIN q[469]
    DIRECTION OUTPUT ;
    USE SIGNAL ;
    PORT
      LAYER M5 ;
        RECT  90.432 11.688 90.456 11.88 ;
    END
  END q[469]
  PIN q[46]
    DIRECTION OUTPUT ;
    USE SIGNAL ;
    PORT
      LAYER M5 ;
        RECT  9.216 11.688 9.24 11.88 ;
    END
  END q[46]
  PIN q[470]
    DIRECTION OUTPUT ;
    USE SIGNAL ;
    PORT
      LAYER M5 ;
        RECT  90.624 11.688 90.648 11.88 ;
    END
  END q[470]
  PIN q[471]
    DIRECTION OUTPUT ;
    USE SIGNAL ;
    PORT
      LAYER M5 ;
        RECT  90.816 11.688 90.84 11.88 ;
    END
  END q[471]
  PIN q[472]
    DIRECTION OUTPUT ;
    USE SIGNAL ;
    PORT
      LAYER M5 ;
        RECT  91.008 11.688 91.032 11.88 ;
    END
  END q[472]
  PIN q[473]
    DIRECTION OUTPUT ;
    USE SIGNAL ;
    PORT
      LAYER M5 ;
        RECT  91.2 11.688 91.224 11.88 ;
    END
  END q[473]
  PIN q[474]
    DIRECTION OUTPUT ;
    USE SIGNAL ;
    PORT
      LAYER M5 ;
        RECT  91.392 11.688 91.416 11.88 ;
    END
  END q[474]
  PIN q[475]
    DIRECTION OUTPUT ;
    USE SIGNAL ;
    PORT
      LAYER M5 ;
        RECT  91.584 11.688 91.608 11.88 ;
    END
  END q[475]
  PIN q[476]
    DIRECTION OUTPUT ;
    USE SIGNAL ;
    PORT
      LAYER M5 ;
        RECT  91.776 11.688 91.8 11.88 ;
    END
  END q[476]
  PIN q[477]
    DIRECTION OUTPUT ;
    USE SIGNAL ;
    PORT
      LAYER M5 ;
        RECT  91.968 11.688 91.992 11.88 ;
    END
  END q[477]
  PIN q[478]
    DIRECTION OUTPUT ;
    USE SIGNAL ;
    PORT
      LAYER M5 ;
        RECT  92.16 11.688 92.184 11.88 ;
    END
  END q[478]
  PIN q[479]
    DIRECTION OUTPUT ;
    USE SIGNAL ;
    PORT
      LAYER M5 ;
        RECT  92.352 11.688 92.376 11.88 ;
    END
  END q[479]
  PIN q[47]
    DIRECTION OUTPUT ;
    USE SIGNAL ;
    PORT
      LAYER M5 ;
        RECT  9.408 11.688 9.432 11.88 ;
    END
  END q[47]
  PIN q[480]
    DIRECTION OUTPUT ;
    USE SIGNAL ;
    PORT
      LAYER M5 ;
        RECT  92.544 11.688 92.568 11.88 ;
    END
  END q[480]
  PIN q[481]
    DIRECTION OUTPUT ;
    USE SIGNAL ;
    PORT
      LAYER M5 ;
        RECT  92.736 11.688 92.76 11.88 ;
    END
  END q[481]
  PIN q[482]
    DIRECTION OUTPUT ;
    USE SIGNAL ;
    PORT
      LAYER M5 ;
        RECT  92.928 11.688 92.952 11.88 ;
    END
  END q[482]
  PIN q[483]
    DIRECTION OUTPUT ;
    USE SIGNAL ;
    PORT
      LAYER M5 ;
        RECT  93.12 11.688 93.144 11.88 ;
    END
  END q[483]
  PIN q[484]
    DIRECTION OUTPUT ;
    USE SIGNAL ;
    PORT
      LAYER M5 ;
        RECT  93.312 11.688 93.336 11.88 ;
    END
  END q[484]
  PIN q[485]
    DIRECTION OUTPUT ;
    USE SIGNAL ;
    PORT
      LAYER M5 ;
        RECT  93.504 11.688 93.528 11.88 ;
    END
  END q[485]
  PIN q[486]
    DIRECTION OUTPUT ;
    USE SIGNAL ;
    PORT
      LAYER M5 ;
        RECT  93.696 11.688 93.72 11.88 ;
    END
  END q[486]
  PIN q[487]
    DIRECTION OUTPUT ;
    USE SIGNAL ;
    PORT
      LAYER M5 ;
        RECT  93.888 11.688 93.912 11.88 ;
    END
  END q[487]
  PIN q[488]
    DIRECTION OUTPUT ;
    USE SIGNAL ;
    PORT
      LAYER M5 ;
        RECT  94.08 11.688 94.104 11.88 ;
    END
  END q[488]
  PIN q[489]
    DIRECTION OUTPUT ;
    USE SIGNAL ;
    PORT
      LAYER M5 ;
        RECT  94.272 11.688 94.296 11.88 ;
    END
  END q[489]
  PIN q[48]
    DIRECTION OUTPUT ;
    USE SIGNAL ;
    PORT
      LAYER M5 ;
        RECT  9.6 11.688 9.624 11.88 ;
    END
  END q[48]
  PIN q[490]
    DIRECTION OUTPUT ;
    USE SIGNAL ;
    PORT
      LAYER M5 ;
        RECT  94.464 11.688 94.488 11.88 ;
    END
  END q[490]
  PIN q[491]
    DIRECTION OUTPUT ;
    USE SIGNAL ;
    PORT
      LAYER M5 ;
        RECT  94.656 11.688 94.68 11.88 ;
    END
  END q[491]
  PIN q[492]
    DIRECTION OUTPUT ;
    USE SIGNAL ;
    PORT
      LAYER M5 ;
        RECT  94.848 11.688 94.872 11.88 ;
    END
  END q[492]
  PIN q[493]
    DIRECTION OUTPUT ;
    USE SIGNAL ;
    PORT
      LAYER M5 ;
        RECT  95.04 11.688 95.064 11.88 ;
    END
  END q[493]
  PIN q[494]
    DIRECTION OUTPUT ;
    USE SIGNAL ;
    PORT
      LAYER M5 ;
        RECT  95.232 11.688 95.256 11.88 ;
    END
  END q[494]
  PIN q[495]
    DIRECTION OUTPUT ;
    USE SIGNAL ;
    PORT
      LAYER M5 ;
        RECT  95.424 11.688 95.448 11.88 ;
    END
  END q[495]
  PIN q[496]
    DIRECTION OUTPUT ;
    USE SIGNAL ;
    PORT
      LAYER M5 ;
        RECT  95.616 11.688 95.64 11.88 ;
    END
  END q[496]
  PIN q[497]
    DIRECTION OUTPUT ;
    USE SIGNAL ;
    PORT
      LAYER M5 ;
        RECT  95.808 11.688 95.832 11.88 ;
    END
  END q[497]
  PIN q[498]
    DIRECTION OUTPUT ;
    USE SIGNAL ;
    PORT
      LAYER M5 ;
        RECT  96 11.688 96.024 11.88 ;
    END
  END q[498]
  PIN q[499]
    DIRECTION OUTPUT ;
    USE SIGNAL ;
    PORT
      LAYER M5 ;
        RECT  96.192 11.688 96.216 11.88 ;
    END
  END q[499]
  PIN q[49]
    DIRECTION OUTPUT ;
    USE SIGNAL ;
    PORT
      LAYER M5 ;
        RECT  9.792 11.688 9.816 11.88 ;
    END
  END q[49]
  PIN q[4]
    DIRECTION OUTPUT ;
    USE SIGNAL ;
    PORT
      LAYER M5 ;
        RECT  1.152 11.688 1.176 11.88 ;
    END
  END q[4]
  PIN q[500]
    DIRECTION OUTPUT ;
    USE SIGNAL ;
    PORT
      LAYER M5 ;
        RECT  96.384 11.688 96.408 11.88 ;
    END
  END q[500]
  PIN q[501]
    DIRECTION OUTPUT ;
    USE SIGNAL ;
    PORT
      LAYER M5 ;
        RECT  96.576 11.688 96.6 11.88 ;
    END
  END q[501]
  PIN q[502]
    DIRECTION OUTPUT ;
    USE SIGNAL ;
    PORT
      LAYER M5 ;
        RECT  96.768 11.688 96.792 11.88 ;
    END
  END q[502]
  PIN q[503]
    DIRECTION OUTPUT ;
    USE SIGNAL ;
    PORT
      LAYER M5 ;
        RECT  96.96 11.688 96.984 11.88 ;
    END
  END q[503]
  PIN q[504]
    DIRECTION OUTPUT ;
    USE SIGNAL ;
    PORT
      LAYER M5 ;
        RECT  97.152 11.688 97.176 11.88 ;
    END
  END q[504]
  PIN q[505]
    DIRECTION OUTPUT ;
    USE SIGNAL ;
    PORT
      LAYER M5 ;
        RECT  97.344 11.688 97.368 11.88 ;
    END
  END q[505]
  PIN q[506]
    DIRECTION OUTPUT ;
    USE SIGNAL ;
    PORT
      LAYER M5 ;
        RECT  97.536 11.688 97.56 11.88 ;
    END
  END q[506]
  PIN q[507]
    DIRECTION OUTPUT ;
    USE SIGNAL ;
    PORT
      LAYER M5 ;
        RECT  97.728 11.688 97.752 11.88 ;
    END
  END q[507]
  PIN q[508]
    DIRECTION OUTPUT ;
    USE SIGNAL ;
    PORT
      LAYER M5 ;
        RECT  97.92 11.688 97.944 11.88 ;
    END
  END q[508]
  PIN q[509]
    DIRECTION OUTPUT ;
    USE SIGNAL ;
    PORT
      LAYER M5 ;
        RECT  98.112 11.688 98.136 11.88 ;
    END
  END q[509]
  PIN q[50]
    DIRECTION OUTPUT ;
    USE SIGNAL ;
    PORT
      LAYER M5 ;
        RECT  9.984 11.688 10.008 11.88 ;
    END
  END q[50]
  PIN q[510]
    DIRECTION OUTPUT ;
    USE SIGNAL ;
    PORT
      LAYER M5 ;
        RECT  98.304 11.688 98.328 11.88 ;
    END
  END q[510]
  PIN q[511]
    DIRECTION OUTPUT ;
    USE SIGNAL ;
    PORT
      LAYER M5 ;
        RECT  98.496 11.688 98.52 11.88 ;
    END
  END q[511]
  PIN q[512]
    DIRECTION OUTPUT ;
    USE SIGNAL ;
    PORT
      LAYER M5 ;
        RECT  98.688 11.688 98.712 11.88 ;
    END
  END q[512]
  PIN q[513]
    DIRECTION OUTPUT ;
    USE SIGNAL ;
    PORT
      LAYER M5 ;
        RECT  98.88 11.688 98.904 11.88 ;
    END
  END q[513]
  PIN q[514]
    DIRECTION OUTPUT ;
    USE SIGNAL ;
    PORT
      LAYER M5 ;
        RECT  99.072 11.688 99.096 11.88 ;
    END
  END q[514]
  PIN q[515]
    DIRECTION OUTPUT ;
    USE SIGNAL ;
    PORT
      LAYER M5 ;
        RECT  99.264 11.688 99.288 11.88 ;
    END
  END q[515]
  PIN q[516]
    DIRECTION OUTPUT ;
    USE SIGNAL ;
    PORT
      LAYER M5 ;
        RECT  99.456 11.688 99.48 11.88 ;
    END
  END q[516]
  PIN q[517]
    DIRECTION OUTPUT ;
    USE SIGNAL ;
    PORT
      LAYER M5 ;
        RECT  99.648 11.688 99.672 11.88 ;
    END
  END q[517]
  PIN q[518]
    DIRECTION OUTPUT ;
    USE SIGNAL ;
    PORT
      LAYER M5 ;
        RECT  99.84 11.688 99.864 11.88 ;
    END
  END q[518]
  PIN q[519]
    DIRECTION OUTPUT ;
    USE SIGNAL ;
    PORT
      LAYER M5 ;
        RECT  100.032 11.688 100.056 11.88 ;
    END
  END q[519]
  PIN q[51]
    DIRECTION OUTPUT ;
    USE SIGNAL ;
    PORT
      LAYER M5 ;
        RECT  10.176 11.688 10.2 11.88 ;
    END
  END q[51]
  PIN q[520]
    DIRECTION OUTPUT ;
    USE SIGNAL ;
    PORT
      LAYER M5 ;
        RECT  100.224 11.688 100.248 11.88 ;
    END
  END q[520]
  PIN q[521]
    DIRECTION OUTPUT ;
    USE SIGNAL ;
    PORT
      LAYER M5 ;
        RECT  100.416 11.688 100.44 11.88 ;
    END
  END q[521]
  PIN q[522]
    DIRECTION OUTPUT ;
    USE SIGNAL ;
    PORT
      LAYER M5 ;
        RECT  100.608 11.688 100.632 11.88 ;
    END
  END q[522]
  PIN q[523]
    DIRECTION OUTPUT ;
    USE SIGNAL ;
    PORT
      LAYER M5 ;
        RECT  100.8 11.688 100.824 11.88 ;
    END
  END q[523]
  PIN q[524]
    DIRECTION OUTPUT ;
    USE SIGNAL ;
    PORT
      LAYER M5 ;
        RECT  100.992 11.688 101.016 11.88 ;
    END
  END q[524]
  PIN q[525]
    DIRECTION OUTPUT ;
    USE SIGNAL ;
    PORT
      LAYER M5 ;
        RECT  101.184 11.688 101.208 11.88 ;
    END
  END q[525]
  PIN q[526]
    DIRECTION OUTPUT ;
    USE SIGNAL ;
    PORT
      LAYER M5 ;
        RECT  101.376 11.688 101.4 11.88 ;
    END
  END q[526]
  PIN q[527]
    DIRECTION OUTPUT ;
    USE SIGNAL ;
    PORT
      LAYER M5 ;
        RECT  101.568 11.688 101.592 11.88 ;
    END
  END q[527]
  PIN q[528]
    DIRECTION OUTPUT ;
    USE SIGNAL ;
    PORT
      LAYER M5 ;
        RECT  101.76 11.688 101.784 11.88 ;
    END
  END q[528]
  PIN q[529]
    DIRECTION OUTPUT ;
    USE SIGNAL ;
    PORT
      LAYER M5 ;
        RECT  101.952 11.688 101.976 11.88 ;
    END
  END q[529]
  PIN q[52]
    DIRECTION OUTPUT ;
    USE SIGNAL ;
    PORT
      LAYER M5 ;
        RECT  10.368 11.688 10.392 11.88 ;
    END
  END q[52]
  PIN q[530]
    DIRECTION OUTPUT ;
    USE SIGNAL ;
    PORT
      LAYER M5 ;
        RECT  102.144 11.688 102.168 11.88 ;
    END
  END q[530]
  PIN q[531]
    DIRECTION OUTPUT ;
    USE SIGNAL ;
    PORT
      LAYER M5 ;
        RECT  102.336 11.688 102.36 11.88 ;
    END
  END q[531]
  PIN q[532]
    DIRECTION OUTPUT ;
    USE SIGNAL ;
    PORT
      LAYER M5 ;
        RECT  102.528 11.688 102.552 11.88 ;
    END
  END q[532]
  PIN q[533]
    DIRECTION OUTPUT ;
    USE SIGNAL ;
    PORT
      LAYER M5 ;
        RECT  102.72 11.688 102.744 11.88 ;
    END
  END q[533]
  PIN q[534]
    DIRECTION OUTPUT ;
    USE SIGNAL ;
    PORT
      LAYER M5 ;
        RECT  102.912 11.688 102.936 11.88 ;
    END
  END q[534]
  PIN q[535]
    DIRECTION OUTPUT ;
    USE SIGNAL ;
    PORT
      LAYER M5 ;
        RECT  103.104 11.688 103.128 11.88 ;
    END
  END q[535]
  PIN q[536]
    DIRECTION OUTPUT ;
    USE SIGNAL ;
    PORT
      LAYER M5 ;
        RECT  103.296 11.688 103.32 11.88 ;
    END
  END q[536]
  PIN q[537]
    DIRECTION OUTPUT ;
    USE SIGNAL ;
    PORT
      LAYER M5 ;
        RECT  103.488 11.688 103.512 11.88 ;
    END
  END q[537]
  PIN q[538]
    DIRECTION OUTPUT ;
    USE SIGNAL ;
    PORT
      LAYER M5 ;
        RECT  103.68 11.688 103.704 11.88 ;
    END
  END q[538]
  PIN q[539]
    DIRECTION OUTPUT ;
    USE SIGNAL ;
    PORT
      LAYER M5 ;
        RECT  103.872 11.688 103.896 11.88 ;
    END
  END q[539]
  PIN q[53]
    DIRECTION OUTPUT ;
    USE SIGNAL ;
    PORT
      LAYER M5 ;
        RECT  10.56 11.688 10.584 11.88 ;
    END
  END q[53]
  PIN q[540]
    DIRECTION OUTPUT ;
    USE SIGNAL ;
    PORT
      LAYER M5 ;
        RECT  104.064 11.688 104.088 11.88 ;
    END
  END q[540]
  PIN q[541]
    DIRECTION OUTPUT ;
    USE SIGNAL ;
    PORT
      LAYER M5 ;
        RECT  104.256 11.688 104.28 11.88 ;
    END
  END q[541]
  PIN q[542]
    DIRECTION OUTPUT ;
    USE SIGNAL ;
    PORT
      LAYER M5 ;
        RECT  104.448 11.688 104.472 11.88 ;
    END
  END q[542]
  PIN q[543]
    DIRECTION OUTPUT ;
    USE SIGNAL ;
    PORT
      LAYER M5 ;
        RECT  104.64 11.688 104.664 11.88 ;
    END
  END q[543]
  PIN q[54]
    DIRECTION OUTPUT ;
    USE SIGNAL ;
    PORT
      LAYER M5 ;
        RECT  10.752 11.688 10.776 11.88 ;
    END
  END q[54]
  PIN q[55]
    DIRECTION OUTPUT ;
    USE SIGNAL ;
    PORT
      LAYER M5 ;
        RECT  10.944 11.688 10.968 11.88 ;
    END
  END q[55]
  PIN q[56]
    DIRECTION OUTPUT ;
    USE SIGNAL ;
    PORT
      LAYER M5 ;
        RECT  11.136 11.688 11.16 11.88 ;
    END
  END q[56]
  PIN q[57]
    DIRECTION OUTPUT ;
    USE SIGNAL ;
    PORT
      LAYER M5 ;
        RECT  11.328 11.688 11.352 11.88 ;
    END
  END q[57]
  PIN q[58]
    DIRECTION OUTPUT ;
    USE SIGNAL ;
    PORT
      LAYER M5 ;
        RECT  11.52 11.688 11.544 11.88 ;
    END
  END q[58]
  PIN q[59]
    DIRECTION OUTPUT ;
    USE SIGNAL ;
    PORT
      LAYER M5 ;
        RECT  11.712 11.688 11.736 11.88 ;
    END
  END q[59]
  PIN q[5]
    DIRECTION OUTPUT ;
    USE SIGNAL ;
    PORT
      LAYER M5 ;
        RECT  1.344 11.688 1.368 11.88 ;
    END
  END q[5]
  PIN q[60]
    DIRECTION OUTPUT ;
    USE SIGNAL ;
    PORT
      LAYER M5 ;
        RECT  11.904 11.688 11.928 11.88 ;
    END
  END q[60]
  PIN q[61]
    DIRECTION OUTPUT ;
    USE SIGNAL ;
    PORT
      LAYER M5 ;
        RECT  12.096 11.688 12.12 11.88 ;
    END
  END q[61]
  PIN q[62]
    DIRECTION OUTPUT ;
    USE SIGNAL ;
    PORT
      LAYER M5 ;
        RECT  12.288 11.688 12.312 11.88 ;
    END
  END q[62]
  PIN q[63]
    DIRECTION OUTPUT ;
    USE SIGNAL ;
    PORT
      LAYER M5 ;
        RECT  12.48 11.688 12.504 11.88 ;
    END
  END q[63]
  PIN q[64]
    DIRECTION OUTPUT ;
    USE SIGNAL ;
    PORT
      LAYER M5 ;
        RECT  12.672 11.688 12.696 11.88 ;
    END
  END q[64]
  PIN q[65]
    DIRECTION OUTPUT ;
    USE SIGNAL ;
    PORT
      LAYER M5 ;
        RECT  12.864 11.688 12.888 11.88 ;
    END
  END q[65]
  PIN q[66]
    DIRECTION OUTPUT ;
    USE SIGNAL ;
    PORT
      LAYER M5 ;
        RECT  13.056 11.688 13.08 11.88 ;
    END
  END q[66]
  PIN q[67]
    DIRECTION OUTPUT ;
    USE SIGNAL ;
    PORT
      LAYER M5 ;
        RECT  13.248 11.688 13.272 11.88 ;
    END
  END q[67]
  PIN q[68]
    DIRECTION OUTPUT ;
    USE SIGNAL ;
    PORT
      LAYER M5 ;
        RECT  13.44 11.688 13.464 11.88 ;
    END
  END q[68]
  PIN q[69]
    DIRECTION OUTPUT ;
    USE SIGNAL ;
    PORT
      LAYER M5 ;
        RECT  13.632 11.688 13.656 11.88 ;
    END
  END q[69]
  PIN q[6]
    DIRECTION OUTPUT ;
    USE SIGNAL ;
    PORT
      LAYER M5 ;
        RECT  1.536 11.688 1.56 11.88 ;
    END
  END q[6]
  PIN q[70]
    DIRECTION OUTPUT ;
    USE SIGNAL ;
    PORT
      LAYER M5 ;
        RECT  13.824 11.688 13.848 11.88 ;
    END
  END q[70]
  PIN q[71]
    DIRECTION OUTPUT ;
    USE SIGNAL ;
    PORT
      LAYER M5 ;
        RECT  14.016 11.688 14.04 11.88 ;
    END
  END q[71]
  PIN q[72]
    DIRECTION OUTPUT ;
    USE SIGNAL ;
    PORT
      LAYER M5 ;
        RECT  14.208 11.688 14.232 11.88 ;
    END
  END q[72]
  PIN q[73]
    DIRECTION OUTPUT ;
    USE SIGNAL ;
    PORT
      LAYER M5 ;
        RECT  14.4 11.688 14.424 11.88 ;
    END
  END q[73]
  PIN q[74]
    DIRECTION OUTPUT ;
    USE SIGNAL ;
    PORT
      LAYER M5 ;
        RECT  14.592 11.688 14.616 11.88 ;
    END
  END q[74]
  PIN q[75]
    DIRECTION OUTPUT ;
    USE SIGNAL ;
    PORT
      LAYER M5 ;
        RECT  14.784 11.688 14.808 11.88 ;
    END
  END q[75]
  PIN q[76]
    DIRECTION OUTPUT ;
    USE SIGNAL ;
    PORT
      LAYER M5 ;
        RECT  14.976 11.688 15 11.88 ;
    END
  END q[76]
  PIN q[77]
    DIRECTION OUTPUT ;
    USE SIGNAL ;
    PORT
      LAYER M5 ;
        RECT  15.168 11.688 15.192 11.88 ;
    END
  END q[77]
  PIN q[78]
    DIRECTION OUTPUT ;
    USE SIGNAL ;
    PORT
      LAYER M5 ;
        RECT  15.36 11.688 15.384 11.88 ;
    END
  END q[78]
  PIN q[79]
    DIRECTION OUTPUT ;
    USE SIGNAL ;
    PORT
      LAYER M5 ;
        RECT  15.552 11.688 15.576 11.88 ;
    END
  END q[79]
  PIN q[7]
    DIRECTION OUTPUT ;
    USE SIGNAL ;
    PORT
      LAYER M5 ;
        RECT  1.728 11.688 1.752 11.88 ;
    END
  END q[7]
  PIN q[80]
    DIRECTION OUTPUT ;
    USE SIGNAL ;
    PORT
      LAYER M5 ;
        RECT  15.744 11.688 15.768 11.88 ;
    END
  END q[80]
  PIN q[81]
    DIRECTION OUTPUT ;
    USE SIGNAL ;
    PORT
      LAYER M5 ;
        RECT  15.936 11.688 15.96 11.88 ;
    END
  END q[81]
  PIN q[82]
    DIRECTION OUTPUT ;
    USE SIGNAL ;
    PORT
      LAYER M5 ;
        RECT  16.128 11.688 16.152 11.88 ;
    END
  END q[82]
  PIN q[83]
    DIRECTION OUTPUT ;
    USE SIGNAL ;
    PORT
      LAYER M5 ;
        RECT  16.32 11.688 16.344 11.88 ;
    END
  END q[83]
  PIN q[84]
    DIRECTION OUTPUT ;
    USE SIGNAL ;
    PORT
      LAYER M5 ;
        RECT  16.512 11.688 16.536 11.88 ;
    END
  END q[84]
  PIN q[85]
    DIRECTION OUTPUT ;
    USE SIGNAL ;
    PORT
      LAYER M5 ;
        RECT  16.704 11.688 16.728 11.88 ;
    END
  END q[85]
  PIN q[86]
    DIRECTION OUTPUT ;
    USE SIGNAL ;
    PORT
      LAYER M5 ;
        RECT  16.896 11.688 16.92 11.88 ;
    END
  END q[86]
  PIN q[87]
    DIRECTION OUTPUT ;
    USE SIGNAL ;
    PORT
      LAYER M5 ;
        RECT  17.088 11.688 17.112 11.88 ;
    END
  END q[87]
  PIN q[88]
    DIRECTION OUTPUT ;
    USE SIGNAL ;
    PORT
      LAYER M5 ;
        RECT  17.28 11.688 17.304 11.88 ;
    END
  END q[88]
  PIN q[89]
    DIRECTION OUTPUT ;
    USE SIGNAL ;
    PORT
      LAYER M5 ;
        RECT  17.472 11.688 17.496 11.88 ;
    END
  END q[89]
  PIN q[8]
    DIRECTION OUTPUT ;
    USE SIGNAL ;
    PORT
      LAYER M5 ;
        RECT  1.92 11.688 1.944 11.88 ;
    END
  END q[8]
  PIN q[90]
    DIRECTION OUTPUT ;
    USE SIGNAL ;
    PORT
      LAYER M5 ;
        RECT  17.664 11.688 17.688 11.88 ;
    END
  END q[90]
  PIN q[91]
    DIRECTION OUTPUT ;
    USE SIGNAL ;
    PORT
      LAYER M5 ;
        RECT  17.856 11.688 17.88 11.88 ;
    END
  END q[91]
  PIN q[92]
    DIRECTION OUTPUT ;
    USE SIGNAL ;
    PORT
      LAYER M5 ;
        RECT  18.048 11.688 18.072 11.88 ;
    END
  END q[92]
  PIN q[93]
    DIRECTION OUTPUT ;
    USE SIGNAL ;
    PORT
      LAYER M5 ;
        RECT  18.24 11.688 18.264 11.88 ;
    END
  END q[93]
  PIN q[94]
    DIRECTION OUTPUT ;
    USE SIGNAL ;
    PORT
      LAYER M5 ;
        RECT  18.432 11.688 18.456 11.88 ;
    END
  END q[94]
  PIN q[95]
    DIRECTION OUTPUT ;
    USE SIGNAL ;
    PORT
      LAYER M5 ;
        RECT  18.624 11.688 18.648 11.88 ;
    END
  END q[95]
  PIN q[96]
    DIRECTION OUTPUT ;
    USE SIGNAL ;
    PORT
      LAYER M5 ;
        RECT  18.816 11.688 18.84 11.88 ;
    END
  END q[96]
  PIN q[97]
    DIRECTION OUTPUT ;
    USE SIGNAL ;
    PORT
      LAYER M5 ;
        RECT  19.008 11.688 19.032 11.88 ;
    END
  END q[97]
  PIN q[98]
    DIRECTION OUTPUT ;
    USE SIGNAL ;
    PORT
      LAYER M5 ;
        RECT  19.2 11.688 19.224 11.88 ;
    END
  END q[98]
  PIN q[99]
    DIRECTION OUTPUT ;
    USE SIGNAL ;
    PORT
      LAYER M5 ;
        RECT  19.392 11.688 19.416 11.88 ;
    END
  END q[99]
  PIN q[9]
    DIRECTION OUTPUT ;
    USE SIGNAL ;
    PORT
      LAYER M5 ;
        RECT  2.112 11.688 2.136 11.88 ;
    END
  END q[9]
  PIN VDD
    DIRECTION INOUT ;
    USE POWER ;
    PORT
      LAYER M6 ;
        RECT  105.808 6.972 105.84 7.26 ;
        RECT  0 6.972 0.032 7.26 ;
        RECT  0 6.972 105.84 7.26 ;
        RECT  105.808 1.572 105.84 1.86 ;
        RECT  0 1.572 0.032 1.86 ;
        RECT  0 1.572 105.84 1.86 ;
      LAYER M2 ;
        RECT  105.822 11.061 105.84 11.079 ;
        RECT  0 11.061 0.018 11.079 ;
        RECT  105.822 10.521 105.84 10.539 ;
        RECT  0 10.521 0.018 10.539 ;
        RECT  105.822 9.981 105.84 9.999 ;
        RECT  0 9.981 0.018 9.999 ;
        RECT  105.822 9.441 105.84 9.459 ;
        RECT  0 9.441 0.018 9.459 ;
        RECT  105.822 8.901 105.84 8.919 ;
        RECT  0 8.901 0.018 8.919 ;
        RECT  105.822 8.361 105.84 8.379 ;
        RECT  0 8.361 0.018 8.379 ;
        RECT  105.822 7.821 105.84 7.839 ;
        RECT  0 7.821 0.018 7.839 ;
        RECT  105.822 7.281 105.84 7.299 ;
        RECT  0 7.281 0.018 7.299 ;
        RECT  105.822 6.741 105.84 6.759 ;
        RECT  0 6.741 0.018 6.759 ;
        RECT  105.822 6.201 105.84 6.219 ;
        RECT  0 6.201 0.018 6.219 ;
        RECT  105.822 5.661 105.84 5.679 ;
        RECT  0 5.661 0.018 5.679 ;
        RECT  105.822 5.121 105.84 5.139 ;
        RECT  0 5.121 0.018 5.139 ;
        RECT  105.822 4.581 105.84 4.599 ;
        RECT  0 4.581 0.018 4.599 ;
        RECT  105.822 4.041 105.84 4.059 ;
        RECT  0 4.041 0.018 4.059 ;
        RECT  105.822 3.501 105.84 3.519 ;
        RECT  0 3.501 0.018 3.519 ;
        RECT  105.822 2.961 105.84 2.979 ;
        RECT  0 2.961 0.018 2.979 ;
        RECT  105.822 2.421 105.84 2.439 ;
        RECT  0 2.421 0.018 2.439 ;
        RECT  105.822 1.881 105.84 1.899 ;
        RECT  0 1.881 0.018 1.899 ;
        RECT  105.822 1.341 105.84 1.359 ;
        RECT  0 1.341 0.018 1.359 ;
        RECT  105.822 0.801 105.84 0.819 ;
        RECT  0 0.801 0.018 0.819 ;
      LAYER M1 ;
        RECT  105.822 11.061 105.84 11.079 ;
        RECT  0 11.061 0.018 11.079 ;
        RECT  105.822 10.521 105.84 10.539 ;
        RECT  0 10.521 0.018 10.539 ;
        RECT  105.822 9.981 105.84 9.999 ;
        RECT  0 9.981 0.018 9.999 ;
        RECT  105.822 9.441 105.84 9.459 ;
        RECT  0 9.441 0.018 9.459 ;
        RECT  105.822 8.901 105.84 8.919 ;
        RECT  0 8.901 0.018 8.919 ;
        RECT  105.822 8.361 105.84 8.379 ;
        RECT  0 8.361 0.018 8.379 ;
        RECT  105.822 7.821 105.84 7.839 ;
        RECT  0 7.821 0.018 7.839 ;
        RECT  105.822 7.281 105.84 7.299 ;
        RECT  0 7.281 0.018 7.299 ;
        RECT  105.822 6.741 105.84 6.759 ;
        RECT  0 6.741 0.018 6.759 ;
        RECT  105.822 6.201 105.84 6.219 ;
        RECT  0 6.201 0.018 6.219 ;
        RECT  105.822 5.661 105.84 5.679 ;
        RECT  0 5.661 0.018 5.679 ;
        RECT  105.822 5.121 105.84 5.139 ;
        RECT  0 5.121 0.018 5.139 ;
        RECT  105.822 4.581 105.84 4.599 ;
        RECT  0 4.581 0.018 4.599 ;
        RECT  105.822 4.041 105.84 4.059 ;
        RECT  0 4.041 0.018 4.059 ;
        RECT  105.822 3.501 105.84 3.519 ;
        RECT  0 3.501 0.018 3.519 ;
        RECT  105.822 2.961 105.84 2.979 ;
        RECT  0 2.961 0.018 2.979 ;
        RECT  105.822 2.421 105.84 2.439 ;
        RECT  0 2.421 0.018 2.439 ;
        RECT  105.822 1.881 105.84 1.899 ;
        RECT  0 1.881 0.018 1.899 ;
        RECT  105.822 1.341 105.84 1.359 ;
        RECT  0 1.341 0.018 1.359 ;
        RECT  105.822 0.801 105.84 0.819 ;
        RECT  0 0.801 0.018 0.819 ;
    END
  END VDD
  PIN VSS
    DIRECTION INOUT ;
    USE GROUND ;
    PORT
      LAYER M6 ;
        RECT  105.808 6.396 105.84 6.684 ;
        RECT  0 6.396 0.032 6.684 ;
        RECT  0 6.396 105.84 6.684 ;
        RECT  105.808 0.996 105.84 1.284 ;
        RECT  0 0.996 0.032 1.284 ;
        RECT  0 0.996 105.84 1.284 ;
      LAYER M2 ;
        RECT  105.822 11.331 105.84 11.349 ;
        RECT  0 11.331 0.018 11.349 ;
        RECT  105.822 10.791 105.84 10.809 ;
        RECT  0 10.791 0.018 10.809 ;
        RECT  105.822 10.251 105.84 10.269 ;
        RECT  0 10.251 0.018 10.269 ;
        RECT  105.822 9.711 105.84 9.729 ;
        RECT  0 9.711 0.018 9.729 ;
        RECT  105.822 9.171 105.84 9.189 ;
        RECT  0 9.171 0.018 9.189 ;
        RECT  105.822 8.631 105.84 8.649 ;
        RECT  0 8.631 0.018 8.649 ;
        RECT  105.822 8.091 105.84 8.109 ;
        RECT  0 8.091 0.018 8.109 ;
        RECT  105.822 7.551 105.84 7.569 ;
        RECT  0 7.551 0.018 7.569 ;
        RECT  105.822 7.011 105.84 7.029 ;
        RECT  0 7.011 0.018 7.029 ;
        RECT  105.822 6.471 105.84 6.489 ;
        RECT  0 6.471 0.018 6.489 ;
        RECT  105.822 5.931 105.84 5.949 ;
        RECT  0 5.931 0.018 5.949 ;
        RECT  105.822 5.391 105.84 5.409 ;
        RECT  0 5.391 0.018 5.409 ;
        RECT  105.822 4.851 105.84 4.869 ;
        RECT  0 4.851 0.018 4.869 ;
        RECT  105.822 4.311 105.84 4.329 ;
        RECT  0 4.311 0.018 4.329 ;
        RECT  105.822 3.771 105.84 3.789 ;
        RECT  0 3.771 0.018 3.789 ;
        RECT  105.822 3.231 105.84 3.249 ;
        RECT  0 3.231 0.018 3.249 ;
        RECT  105.822 2.691 105.84 2.709 ;
        RECT  0 2.691 0.018 2.709 ;
        RECT  105.822 2.151 105.84 2.169 ;
        RECT  0 2.151 0.018 2.169 ;
        RECT  105.822 1.611 105.84 1.629 ;
        RECT  0 1.611 0.018 1.629 ;
        RECT  105.822 1.071 105.84 1.089 ;
        RECT  0 1.071 0.018 1.089 ;
        RECT  105.822 0.531 105.84 0.549 ;
        RECT  0 0.531 0.018 0.549 ;
      LAYER M1 ;
        RECT  105.822 11.331 105.84 11.349 ;
        RECT  0 11.331 0.018 11.349 ;
        RECT  105.822 10.791 105.84 10.809 ;
        RECT  0 10.791 0.018 10.809 ;
        RECT  105.822 10.251 105.84 10.269 ;
        RECT  0 10.251 0.018 10.269 ;
        RECT  105.822 9.711 105.84 9.729 ;
        RECT  0 9.711 0.018 9.729 ;
        RECT  105.822 9.171 105.84 9.189 ;
        RECT  0 9.171 0.018 9.189 ;
        RECT  105.822 8.631 105.84 8.649 ;
        RECT  0 8.631 0.018 8.649 ;
        RECT  105.822 8.091 105.84 8.109 ;
        RECT  0 8.091 0.018 8.109 ;
        RECT  105.822 7.551 105.84 7.569 ;
        RECT  0 7.551 0.018 7.569 ;
        RECT  105.822 7.011 105.84 7.029 ;
        RECT  0 7.011 0.018 7.029 ;
        RECT  105.822 6.471 105.84 6.489 ;
        RECT  0 6.471 0.018 6.489 ;
        RECT  105.822 5.931 105.84 5.949 ;
        RECT  0 5.931 0.018 5.949 ;
        RECT  105.822 5.391 105.84 5.409 ;
        RECT  0 5.391 0.018 5.409 ;
        RECT  105.822 4.851 105.84 4.869 ;
        RECT  0 4.851 0.018 4.869 ;
        RECT  105.822 4.311 105.84 4.329 ;
        RECT  0 4.311 0.018 4.329 ;
        RECT  105.822 3.771 105.84 3.789 ;
        RECT  0 3.771 0.018 3.789 ;
        RECT  105.822 3.231 105.84 3.249 ;
        RECT  0 3.231 0.018 3.249 ;
        RECT  105.822 2.691 105.84 2.709 ;
        RECT  0 2.691 0.018 2.709 ;
        RECT  105.822 2.151 105.84 2.169 ;
        RECT  0 2.151 0.018 2.169 ;
        RECT  105.822 1.611 105.84 1.629 ;
        RECT  0 1.611 0.018 1.629 ;
        RECT  105.822 1.071 105.84 1.089 ;
        RECT  0 1.071 0.018 1.089 ;
        RECT  105.822 0.531 105.84 0.549 ;
        RECT  0 0.531 0.018 0.549 ;
    END
  END VSS
  OBS
    LAYER RVTN ;
     RECT  0 0.54 105.84 0.675 ;
     RECT  0 0.945 105.84 1.215 ;
     RECT  0 1.485 105.84 1.755 ;
     RECT  0 2.025 105.84 2.295 ;
     RECT  0 2.565 105.84 2.835 ;
     RECT  0 3.105 105.84 3.375 ;
     RECT  0 3.645 105.84 3.915 ;
     RECT  0 4.185 105.84 4.455 ;
     RECT  0 4.725 105.84 4.995 ;
     RECT  0 5.265 105.84 5.535 ;
     RECT  0 5.805 105.84 6.075 ;
     RECT  0 6.345 105.84 6.615 ;
     RECT  0 6.885 105.84 7.155 ;
     RECT  0 7.425 105.84 7.695 ;
     RECT  0 7.965 105.84 8.235 ;
     RECT  0 8.505 105.84 8.775 ;
     RECT  0 9.045 105.84 9.315 ;
     RECT  0 9.585 105.84 9.855 ;
     RECT  0 10.125 105.84 10.395 ;
     RECT  0 10.665 105.84 10.935 ;
     RECT  0 11.205 105.84 11.34 ;
    LAYER RVTP ;
     RECT  0 0.675 105.84 0.945 ;
     RECT  0 1.215 105.84 1.485 ;
     RECT  0 1.755 105.84 2.025 ;
     RECT  0 2.295 105.84 2.565 ;
     RECT  0 2.835 105.84 3.105 ;
     RECT  0 3.375 105.84 3.645 ;
     RECT  0 3.915 105.84 4.185 ;
     RECT  0 4.455 105.84 4.725 ;
     RECT  0 4.995 105.84 5.265 ;
     RECT  0 5.535 105.84 5.805 ;
     RECT  0 6.075 105.84 6.345 ;
     RECT  0 6.615 105.84 6.885 ;
     RECT  0 7.155 105.84 7.425 ;
     RECT  0 7.695 105.84 7.965 ;
     RECT  0 8.235 105.84 8.505 ;
     RECT  0 8.775 105.84 9.045 ;
     RECT  0 9.315 105.84 9.585 ;
     RECT  0 9.855 105.84 10.125 ;
     RECT  0 10.395 105.84 10.665 ;
     RECT  0 10.935 105.84 11.205 ;
    LAYER M1 ;
     RECT  0 0.531 105.84 11.349 ;
    LAYER M2 ;
     RECT  0 0.531 105.84 11.349 ;
    LAYER M3 ;
     RECT  43.164 0.187 43.182 0.379 ;
     RECT  86.616 0.283 86.634 0.379 ;
     RECT  5.616 0.331 5.634 0.427 ;
     RECT  5.544 0.427 5.634 0.523 ;
     RECT  11.016 0.379 11.034 0.523 ;
     RECT  16.416 0.379 16.434 0.523 ;
     RECT  21.636 0.379 21.654 0.523 ;
     RECT  27.216 0.379 27.234 0.523 ;
     RECT  38.196 0.379 38.214 0.523 ;
     RECT  43.164 0.379 43.398 0.523 ;
     RECT  54.108 0.379 54.126 0.523 ;
     RECT  59.796 0.379 59.814 0.523 ;
     RECT  65.016 0.379 65.034 0.523 ;
     RECT  70.416 0.379 70.434 0.523 ;
     RECT  75.78 0.379 75.798 0.523 ;
     RECT  86.58 0.379 86.634 0.523 ;
     RECT  91.656 0.379 91.674 0.523 ;
     RECT  92.592 0.187 92.61 0.523 ;
     RECT  96.732 0.187 96.75 0.523 ;
     RECT  97.596 0.379 97.614 0.523 ;
     RECT  0.255 0.523 0.345 0.571 ;
     RECT  4.428 0.523 4.446 0.571 ;
     RECT  5.544 0.523 5.745 0.571 ;
     RECT  7.632 0.187 7.65 0.571 ;
     RECT  11.016 0.523 11.145 0.571 ;
     RECT  11.952 0.187 11.97 0.571 ;
     RECT  16.416 0.523 16.545 0.571 ;
     RECT  21.636 0.523 21.945 0.571 ;
     RECT  27.216 0.523 27.345 0.571 ;
     RECT  32.655 0.523 32.745 0.571 ;
     RECT  38.055 0.523 38.214 0.571 ;
     RECT  43.164 0.523 43.545 0.571 ;
     RECT  48.78 0.379 49.014 0.571 ;
     RECT  54.108 0.523 54.345 0.571 ;
     RECT  55.512 0.187 55.53 0.571 ;
     RECT  59.655 0.523 59.814 0.571 ;
     RECT  63.252 0.475 63.27 0.571 ;
     RECT  65.016 0.523 65.145 0.571 ;
     RECT  70.416 0.523 70.545 0.571 ;
     RECT  73.368 0.187 73.386 0.571 ;
     RECT  75.78 0.523 75.945 0.571 ;
     RECT  81.216 0.379 81.414 0.571 ;
     RECT  86.58 0.523 86.745 0.571 ;
     RECT  90.468 0.187 90.486 0.571 ;
     RECT  91.656 0.523 92.61 0.571 ;
     RECT  94.644 0.187 94.662 0.571 ;
     RECT  96.732 0.523 97.614 0.571 ;
     RECT  102.855 0.523 102.945 0.571 ;
     RECT  2.016 0.571 5.886 0.607 ;
     RECT  6.624 0.571 7.65 0.607 ;
     RECT  8.388 0.571 24.678 0.607 ;
     RECT  25.452 0.571 67.23 0.607 ;
     RECT  78.336 0.571 83.898 0.607 ;
     RECT  84.636 0.571 94.662 0.607 ;
     RECT  95.4 0.571 100.854 0.607 ;
     RECT  0.255 0.571 1.278 0.619 ;
     RECT  2.016 0.607 67.23 0.619 ;
     RECT  67.968 0.571 77.598 0.619 ;
     RECT  101.664 0.571 104.634 0.635 ;
     RECT  0.255 0.619 77.598 0.751 ;
     RECT  78.336 0.607 100.854 0.751 ;
     RECT  101.664 0.635 104.49 0.751 ;
     RECT  0.255 0.751 104.49 1.445 ;
     RECT  8.604 1.445 104.49 1.561 ;
     RECT  8.604 1.561 105.066 2.101 ;
     RECT  8.604 2.101 105.174 2.291 ;
     RECT  0.255 1.445 7.758 2.641 ;
     RECT  0.255 2.641 7.794 2.767 ;
     RECT  0.252 2.767 7.794 2.861 ;
     RECT  0.255 2.861 7.794 3.181 ;
     RECT  8.604 2.291 104.634 3.181 ;
     RECT  0.255 3.181 104.634 3.847 ;
     RECT  0.255 3.847 104.85 5.789 ;
     RECT  0.255 5.789 77.706 6.269 ;
     RECT  0.255 6.269 53.082 7.231 ;
     RECT  53.928 6.269 77.706 7.231 ;
     RECT  78.444 5.789 104.85 7.231 ;
     RECT  0.255 7.231 104.85 7.619 ;
     RECT  0.255 7.619 77.706 7.799 ;
     RECT  78.444 7.619 104.85 7.961 ;
     RECT  32.076 7.799 77.706 8.303 ;
     RECT  78.444 7.961 104.742 8.477 ;
     RECT  32.076 8.303 53.01 8.573 ;
     RECT  0.255 7.799 31.338 8.581 ;
     RECT  32.076 8.573 33.606 8.581 ;
     RECT  53.928 8.303 77.706 8.671 ;
     RECT  78.444 8.477 96.426 8.671 ;
     RECT  53.928 8.671 96.426 9.067 ;
     RECT  0.255 8.581 33.606 9.149 ;
     RECT  34.524 8.573 53.01 9.149 ;
     RECT  40.968 9.149 53.01 9.245 ;
     RECT  97.164 8.477 104.742 9.245 ;
     RECT  34.524 9.149 40.194 9.355 ;
     RECT  34.272 9.355 40.194 9.392 ;
     RECT  103.932 9.245 104.742 9.545 ;
     RECT  53.748 9.067 96.426 9.547 ;
     RECT  97.164 9.245 103.194 9.547 ;
     RECT  0.255 9.149 33.462 9.677 ;
     RECT  53.748 9.547 103.194 9.677 ;
     RECT  52.308 9.245 53.01 9.691 ;
     RECT  53.748 9.677 76.554 9.691 ;
     RECT  8.748 9.677 33.462 9.725 ;
     RECT  40.968 9.245 51.21 9.725 ;
     RECT  9 9.725 33.462 9.779 ;
     RECT  77.652 9.677 103.194 9.779 ;
     RECT  0.255 9.677 7.182 9.838 ;
     RECT  77.652 9.779 79.254 9.851 ;
     RECT  9 9.779 31.266 9.959 ;
     RECT  34.596 9.392 40.194 9.959 ;
     RECT  41.184 9.725 51.21 9.965 ;
     RECT  52.308 9.691 76.554 10.027 ;
     RECT  35.424 9.959 40.194 10.049 ;
     RECT  52.02 10.027 76.554 10.049 ;
     RECT  52.02 10.049 52.038 10.085 ;
     RECT  52.848 10.049 76.554 10.085 ;
     RECT  10.944 9.959 29.178 10.121 ;
     RECT  41.292 9.965 51.21 10.193 ;
     RECT  44.64 10.193 51.21 10.201 ;
     RECT  3.636 9.838 7.182 10.253 ;
     RECT  15.516 10.121 29.178 10.253 ;
     RECT  29.952 9.959 31.266 10.253 ;
     RECT  41.292 10.193 43.794 10.253 ;
     RECT  53.964 10.085 68.634 10.253 ;
     RECT  69.912 10.085 76.554 10.253 ;
     RECT  80.064 9.779 103.194 10.253 ;
     RECT  35.424 10.049 40.158 10.301 ;
     RECT  41.292 10.253 43.737 10.301 ;
     RECT  54.18 10.253 63.09 10.319 ;
     RECT  64.548 10.253 68.634 10.319 ;
     RECT  35.424 10.301 37.134 10.349 ;
     RECT  72.504 10.253 76.554 10.349 ;
     RECT  19.8 10.253 29.178 10.391 ;
     RECT  77.652 9.851 79.218 10.391 ;
     RECT  88.056 10.253 99.09 10.391 ;
     RECT  35.424 10.349 35.802 10.397 ;
     RECT  5.328 10.253 7.182 10.471 ;
     RECT  7.956 9.677 7.974 10.471 ;
     RECT  77.652 10.391 78.822 10.471 ;
     RECT  16.455 10.253 18.882 10.499 ;
     RECT  30.168 10.253 31.266 10.561 ;
     RECT  32.004 9.779 33.462 10.561 ;
     RECT  16.455 10.499 18.63 10.589 ;
     RECT  36.576 10.349 37.134 10.589 ;
     RECT  95.868 10.391 99.09 10.589 ;
     RECT  44.64 10.201 51.894 10.625 ;
     RECT  5.328 10.471 7.974 10.661 ;
     RECT  72.504 10.349 76.374 10.661 ;
     RECT  80.064 10.253 87.282 10.661 ;
     RECT  80.064 10.661 80.154 10.741 ;
     RECT  100.188 10.253 103.194 10.741 ;
     RECT  72.504 10.661 76.302 10.769 ;
     RECT  44.748 10.625 51.894 10.781 ;
     RECT  10.944 10.121 14.742 10.829 ;
     RECT  19.8 10.391 29.106 10.829 ;
     RECT  30.168 10.561 33.462 10.829 ;
     RECT  61.884 10.319 63.09 10.829 ;
     RECT  72.504 10.769 74.574 10.829 ;
     RECT  75.312 10.769 76.302 10.829 ;
     RECT  88.056 10.391 92.538 10.829 ;
     RECT  95.94 10.589 99.09 10.829 ;
     RECT  9 9.959 10.206 10.877 ;
     RECT  10.944 10.829 12.51 10.877 ;
     RECT  13.356 10.829 14.742 10.877 ;
     RECT  16.455 10.589 18.522 10.877 ;
     RECT  19.8 10.829 22.137 10.877 ;
     RECT  22.968 10.829 29.106 10.877 ;
     RECT  35.784 10.397 35.802 10.877 ;
     RECT  45.18 10.781 51.894 10.877 ;
     RECT  52.848 10.085 53.01 10.877 ;
     RECT  54.18 10.319 61.146 10.877 ;
     RECT  64.548 10.319 67.842 10.877 ;
     RECT  68.616 10.319 68.634 10.877 ;
     RECT  69.912 10.253 71.586 10.877 ;
     RECT  72.504 10.829 73.998 10.877 ;
     RECT  81.036 10.661 87.282 10.877 ;
     RECT  88.596 10.829 92.538 10.877 ;
     RECT  93.456 10.391 94.482 10.877 ;
     RECT  95.94 10.829 98.982 10.877 ;
     RECT  100.188 10.741 103.266 10.877 ;
     RECT  104.04 9.545 104.742 10.877 ;
     RECT  75.312 10.829 76.266 10.895 ;
     RECT  95.94 10.877 98.622 10.895 ;
     RECT  50.076 10.877 51.318 10.925 ;
     RECT  104.256 10.877 104.274 10.925 ;
     RECT  37.98 10.301 40.158 10.931 ;
     RECT  57.924 10.877 61.146 11.003 ;
     RECT  10.944 10.877 11.97 11.011 ;
     RECT  22.968 10.877 25.938 11.069 ;
     RECT  27.072 10.877 28.422 11.069 ;
     RECT  36.576 10.589 37.062 11.069 ;
     RECT  39.528 10.931 40.158 11.069 ;
     RECT  41.76 10.301 43.737 11.069 ;
     RECT  50.796 10.925 51.318 11.069 ;
     RECT  57.924 11.003 57.942 11.069 ;
     RECT  72.54 10.877 73.386 11.069 ;
     RECT  75.42 10.895 76.266 11.069 ;
     RECT  93.456 10.877 94.302 11.069 ;
     RECT  96.048 10.895 98.622 11.069 ;
     RECT  16.455 10.877 16.737 11.087 ;
     RECT  21.204 10.877 22.137 11.087 ;
     RECT  42.948 11.069 43.737 11.087 ;
     RECT  3.636 10.253 4.482 11.165 ;
     RECT  5.328 10.661 7.83 11.165 ;
     RECT  10.26 11.011 11.97 11.165 ;
     RECT  20.052 10.877 20.214 11.165 ;
     RECT  21.204 11.087 21.945 11.165 ;
     RECT  22.968 11.069 25.758 11.165 ;
     RECT  27.072 11.069 28.35 11.165 ;
     RECT  30.528 10.829 33.462 11.165 ;
     RECT  34.596 9.959 34.614 11.165 ;
     RECT  39.6 11.069 40.158 11.165 ;
     RECT  41.76 11.069 42.21 11.165 ;
     RECT  42.948 11.087 43.545 11.165 ;
     RECT  46.512 10.877 49.266 11.165 ;
     RECT  50.796 11.069 50.922 11.165 ;
     RECT  52.848 10.877 52.974 11.165 ;
     RECT  54.18 10.877 56.934 11.165 ;
     RECT  62.208 10.829 63.09 11.165 ;
     RECT  69.912 10.877 71.514 11.165 ;
     RECT  72.54 11.069 72.99 11.165 ;
     RECT  77.616 10.471 78.822 11.165 ;
     RECT  81.036 10.877 82.026 11.165 ;
     RECT  83.556 10.877 87.282 11.165 ;
     RECT  88.596 10.877 90.45 11.165 ;
     RECT  91.296 10.877 92.538 11.165 ;
     RECT  93.456 11.069 93.582 11.165 ;
     RECT  100.26 10.877 103.266 11.165 ;
     RECT  79.596 10.741 80.154 11.201 ;
     RECT  96.588 11.069 98.622 11.201 ;
     RECT  0.255 9.838 2.538 11.213 ;
     RECT  5.328 11.165 6.318 11.213 ;
     RECT  5.328 11.213 5.814 11.237 ;
     RECT  70.02 11.165 71.514 11.237 ;
     RECT  10.368 11.165 11.97 11.273 ;
     RECT  16.455 11.087 16.614 11.273 ;
     RECT  36.576 11.069 36.702 11.273 ;
     RECT  41.904 11.165 42.21 11.273 ;
     RECT  72.684 11.165 72.99 11.273 ;
     RECT  83.7 11.165 87.282 11.273 ;
     RECT  1.116 11.213 2.538 11.281 ;
     RECT  5.328 11.237 5.745 11.281 ;
     RECT  13.536 10.877 14.742 11.281 ;
     RECT  15.516 10.253 15.534 11.281 ;
     RECT  16.455 11.273 16.545 11.281 ;
     RECT  30.672 11.165 33.462 11.281 ;
     RECT  39.744 11.165 40.158 11.281 ;
     RECT  64.548 10.877 67.014 11.281 ;
     RECT  77.76 11.165 78.822 11.281 ;
     RECT  91.404 11.165 92.538 11.281 ;
     RECT  100.368 11.165 103.266 11.281 ;
     RECT  0.255 11.213 0.345 11.357 ;
     RECT  1.116 11.281 2.646 11.357 ;
     RECT  3.78 11.165 3.798 11.357 ;
     RECT  4.572 11.281 5.745 11.357 ;
     RECT  7.128 11.165 7.83 11.357 ;
     RECT  10.368 11.273 11.898 11.357 ;
     RECT  13.536 11.281 16.545 11.357 ;
     RECT  17.496 10.877 18.522 11.357 ;
     RECT  20.196 11.165 20.214 11.357 ;
     RECT  21.312 11.165 21.945 11.357 ;
     RECT  23.112 11.165 25.758 11.357 ;
     RECT  27.216 11.165 28.35 11.357 ;
     RECT  30.672 11.281 33.498 11.357 ;
     RECT  34.704 11.281 34.722 11.357 ;
     RECT  36.432 11.281 36.45 11.357 ;
     RECT  37.98 10.931 38.79 11.357 ;
     RECT  39.744 11.281 40.302 11.357 ;
     RECT  41.904 11.273 42.174 11.357 ;
     RECT  43.092 11.165 43.545 11.357 ;
     RECT  45.18 10.877 45.738 11.357 ;
     RECT  46.656 11.165 47.466 11.357 ;
     RECT  48.204 11.165 49.266 11.357 ;
     RECT  50.904 11.165 50.922 11.357 ;
     RECT  52.956 11.165 52.974 11.357 ;
     RECT  54.216 11.165 56.934 11.357 ;
     RECT  58.68 11.003 61.146 11.357 ;
     RECT  62.316 11.165 63.09 11.357 ;
     RECT  64.332 11.281 67.014 11.357 ;
     RECT  67.824 10.877 67.842 11.357 ;
     RECT  70.02 11.237 70.902 11.357 ;
     RECT  72.684 11.273 72.954 11.357 ;
     RECT  75.708 11.069 76.266 11.357 ;
     RECT  77.76 11.281 79.506 11.357 ;
     RECT  81.144 11.165 82.026 11.357 ;
     RECT  83.7 11.273 85.482 11.357 ;
     RECT  86.655 11.273 86.886 11.357 ;
     RECT  88.704 11.165 89.118 11.357 ;
     RECT  89.856 11.165 90.45 11.357 ;
     RECT  91.404 11.281 92.682 11.357 ;
     RECT  93.564 11.165 93.582 11.357 ;
     RECT  96.588 11.201 96.606 11.357 ;
     RECT  97.455 11.201 98.19 11.357 ;
     RECT  100.368 11.281 103.374 11.357 ;
     RECT  2.088 11.357 2.106 11.405 ;
     RECT  23.112 11.357 23.13 11.405 ;
     RECT  24.84 11.357 24.858 11.405 ;
     RECT  32.616 11.357 33.498 11.405 ;
     RECT  42.156 11.357 42.174 11.405 ;
     RECT  48.204 11.357 49.194 11.405 ;
     RECT  55.728 11.357 55.746 11.405 ;
     RECT  56.916 11.357 56.934 11.405 ;
     RECT  59.112 11.357 59.13 11.405 ;
     RECT  62.568 11.357 62.586 11.405 ;
     RECT  66.132 11.357 66.15 11.405 ;
     RECT  70.308 11.357 70.326 11.405 ;
     RECT  72.936 11.357 72.954 11.405 ;
     RECT  91.944 11.357 91.962 11.405 ;
     RECT  102.06 11.357 102.078 11.405 ;
     RECT  11.016 11.357 11.43 11.453 ;
     RECT  21.816 11.357 21.834 11.453 ;
     RECT  27.216 11.357 27.81 11.453 ;
     RECT  32.616 11.405 32.814 11.453 ;
     RECT  48.816 11.405 49.194 11.453 ;
     RECT  54.216 11.357 54.738 11.453 ;
     RECT  11.412 11.453 11.43 11.501 ;
     RECT  27.792 11.453 27.81 11.501 ;
     RECT  32.796 11.453 32.814 11.501 ;
     RECT  37.98 11.357 38.394 11.501 ;
     RECT  43.416 11.357 43.434 11.501 ;
     RECT  49.176 11.453 49.194 11.501 ;
     RECT  54.612 11.453 54.738 11.501 ;
     RECT  59.868 11.357 59.886 11.501 ;
     RECT  76.248 11.357 76.266 11.501 ;
     RECT  81.216 11.357 81.234 11.501 ;
     RECT  86.868 11.357 86.886 11.501 ;
     RECT  54.612 11.501 54.63 11.549 ;
     RECT  15.912 11.357 15.93 11.789 ;
     RECT  40.356 11.659 40.374 11.789 ;
    LAYER M4 ;
     RECT  0.037 4.944 0.133 4.968 ;
     RECT  0.037 6.144 0.133 6.168 ;
     RECT  0.133 2.304 0.241 2.328 ;
     RECT  0.133 0.192 0.248 0.216 ;
     RECT  0.241 2.304 0.248 2.856 ;
     RECT  0.133 4.944 0.248 6.168 ;
     RECT  0.133 11.472 0.248 11.496 ;
     RECT  0.248 0.192 0.419 11.496 ;
     RECT  0.419 0.576 0.544 11.352 ;
     RECT  0.544 8.976 0.749 11.352 ;
     RECT  0.749 8.976 1.073 10.248 ;
     RECT  0.544 3.936 1.181 5.064 ;
     RECT  0.544 7.92 1.525 7.944 ;
     RECT  1.073 8.976 1.525 9.816 ;
     RECT  1.525 7.92 1.82 9.816 ;
     RECT  1.82 7.248 1.907 9.816 ;
     RECT  0.749 11.328 1.909 11.352 ;
     RECT  0.544 2.832 1.957 2.856 ;
     RECT  1.957 1.68 2.012 2.856 ;
     RECT  1.181 3.936 2.012 3.96 ;
     RECT  1.909 11.328 2.117 11.4 ;
     RECT  0.544 0.576 2.221 0.696 ;
     RECT  2.012 1.68 2.221 3.96 ;
     RECT  1.181 5.04 2.221 5.064 ;
     RECT  2.221 0.576 2.245 5.064 ;
     RECT  0.544 6.048 2.245 6.072 ;
     RECT  2.245 0.576 2.261 6.072 ;
     RECT  1.907 7.92 2.531 9.816 ;
     RECT  2.261 0.576 2.585 3.288 ;
     RECT  2.531 9.072 2.585 9.816 ;
     RECT  2.585 2.832 2.621 3.288 ;
     RECT  2.531 7.92 2.905 7.944 ;
     RECT  2.585 0.576 2.915 1.704 ;
     RECT  2.915 0.576 3.299 0.696 ;
     RECT  2.261 4.512 3.305 6.072 ;
     RECT  2.585 9.12 3.413 9.816 ;
     RECT  3.413 9.6 3.449 9.816 ;
     RECT  2.621 3.216 3.485 3.288 ;
     RECT  3.449 9.648 3.637 9.816 ;
     RECT  2.915 1.68 3.805 1.704 ;
     RECT  2.905 7.392 3.829 7.944 ;
     RECT  3.805 1.68 3.841 1.752 ;
     RECT  3.485 3.216 3.841 3.24 ;
     RECT  3.637 9.648 4.021 10.248 ;
     RECT  2.117 11.328 4.021 11.352 ;
     RECT  3.841 1.68 4.067 3.24 ;
     RECT  3.829 7.392 4.309 7.992 ;
     RECT  3.299 0.576 4.417 0.648 ;
     RECT  3.305 5.472 4.549 6.072 ;
     RECT  4.309 7.392 4.549 8.184 ;
     RECT  4.549 5.472 4.595 8.184 ;
     RECT  4.595 7.968 4.637 8.184 ;
     RECT  4.417 0.528 4.921 0.648 ;
     RECT  4.067 1.68 4.921 1.704 ;
     RECT  4.067 2.736 5.209 3.24 ;
     RECT  4.921 0.528 5.245 1.704 ;
     RECT  5.209 2.736 5.245 3.336 ;
     RECT  5.245 0.528 5.461 3.336 ;
     RECT  4.021 9.648 5.461 11.352 ;
     RECT  5.461 0.384 5.602 3.336 ;
     RECT  5.602 0.336 5.648 3.336 ;
     RECT  4.595 5.472 5.648 6.84 ;
     RECT  4.637 8.16 5.648 8.184 ;
     RECT  5.461 9.6 5.648 11.496 ;
     RECT  5.648 0.336 5.795 11.496 ;
     RECT  5.795 0.432 5.944 11.496 ;
     RECT  5.944 0.432 5.987 0.648 ;
     RECT  5.944 9.648 6.083 11.496 ;
     RECT  6.083 9.648 6.257 11.208 ;
     RECT  5.944 1.728 6.373 1.752 ;
     RECT  6.257 9.888 6.653 11.208 ;
     RECT  6.653 9.888 6.761 10.248 ;
     RECT  5.944 8.064 6.977 8.52 ;
     RECT  5.987 0.576 7.081 0.648 ;
     RECT  5.944 5.04 7.153 6.072 ;
     RECT  6.761 9.888 7.285 10.152 ;
     RECT  7.081 0.576 7.331 0.696 ;
     RECT  5.944 2.736 7.429 3.336 ;
     RECT  7.153 4.56 7.429 6.072 ;
     RECT  7.429 2.736 7.441 6.072 ;
     RECT  7.441 2.736 7.513 6.84 ;
     RECT  7.513 2.304 7.517 6.84 ;
     RECT  7.517 5.376 7.525 6.84 ;
     RECT  7.331 0.576 7.621 0.648 ;
     RECT  7.093 11.328 7.841 11.352 ;
     RECT  7.285 9.12 8.053 10.152 ;
     RECT  7.621 0.192 8.291 0.648 ;
     RECT  8.053 9.072 8.417 10.152 ;
     RECT  7.517 2.304 8.677 3.72 ;
     RECT  8.677 1.68 8.764 3.72 ;
     RECT  8.291 0.576 8.773 0.648 ;
     RECT  7.525 5.376 8.777 6.072 ;
     RECT  8.417 9.648 8.972 10.152 ;
     RECT  8.777 5.472 9.061 6.072 ;
     RECT  8.773 0.576 9.251 1.176 ;
     RECT  8.972 9.648 9.397 10.872 ;
     RECT  9.397 9.504 9.484 10.872 ;
     RECT  8.764 2.304 9.569 3.72 ;
     RECT  9.484 9.648 10.037 10.872 ;
     RECT  6.977 8.064 10.429 8.088 ;
     RECT  10.429 7.728 10.549 8.088 ;
     RECT  9.569 2.304 10.673 2.76 ;
     RECT  10.673 2.304 10.7 3.432 ;
     RECT  10.7 2.304 10.717 3.768 ;
     RECT  10.549 7.728 10.741 8.568 ;
     RECT  10.037 9.648 10.741 10.152 ;
     RECT  9.061 5.472 10.789 6.264 ;
     RECT  10.165 11.328 10.933 11.352 ;
     RECT  9.251 0.576 11.005 0.648 ;
     RECT  11.005 0.384 11.048 0.648 ;
     RECT  10.717 2.304 11.048 3.864 ;
     RECT  10.789 5.472 11.048 6.6 ;
     RECT  10.741 7.728 11.048 10.152 ;
     RECT  10.933 11.328 11.048 11.448 ;
     RECT  11.048 0.384 11.125 11.448 ;
     RECT  11.125 0.384 11.344 11.496 ;
     RECT  11.344 7.728 11.441 9.144 ;
     RECT  11.344 10.128 11.441 11.496 ;
     RECT  11.344 2.544 11.651 6.6 ;
     RECT  11.344 0.384 11.747 0.696 ;
     RECT  11.441 10.128 11.909 11.352 ;
     RECT  11.747 0.384 11.941 0.648 ;
     RECT  11.441 7.872 11.981 9.144 ;
     RECT  11.651 2.544 12.125 4.92 ;
     RECT  11.941 0.192 12.323 0.648 ;
     RECT  12.125 2.544 12.325 2.568 ;
     RECT  12.325 1.68 12.371 2.568 ;
     RECT  12.371 1.68 12.413 2.28 ;
     RECT  11.651 6.048 12.524 6.6 ;
     RECT  11.981 7.872 12.524 8.472 ;
     RECT  12.524 6.048 12.611 8.472 ;
     RECT  12.125 3.744 12.665 4.92 ;
     RECT  11.909 10.128 12.853 10.872 ;
     RECT  12.853 9.648 12.953 10.872 ;
     RECT  12.611 7.872 13.045 8.472 ;
     RECT  12.953 9.648 13.045 9.816 ;
     RECT  13.045 7.872 13.132 9.816 ;
     RECT  12.953 10.848 13.429 10.872 ;
     RECT  12.413 2.256 14.051 2.28 ;
     RECT  12.323 0.576 14.101 0.648 ;
     RECT  13.429 10.848 14.389 11.352 ;
     RECT  14.101 0.576 14.435 0.696 ;
     RECT  13.132 7.872 14.485 8.472 ;
     RECT  12.665 3.744 14.497 3.768 ;
     RECT  14.485 7.776 14.572 8.472 ;
     RECT  12.665 4.896 14.605 4.92 ;
     RECT  12.611 6.048 14.605 6.6 ;
     RECT  14.572 7.872 14.741 8.472 ;
     RECT  13.132 9.648 14.741 9.816 ;
     RECT  14.389 10.8 14.753 11.352 ;
     RECT  14.741 7.872 14.861 9.816 ;
     RECT  14.605 4.896 15.365 6.6 ;
     RECT  14.861 7.968 15.401 9.816 ;
     RECT  14.821 1.728 15.469 1.752 ;
     RECT  14.497 3.6 15.469 3.768 ;
     RECT  15.401 9.6 15.541 9.816 ;
     RECT  14.753 11.328 15.857 11.352 ;
     RECT  15.469 1.68 15.877 1.752 ;
     RECT  15.857 11.328 15.941 11.784 ;
     RECT  15.941 11.328 15.971 11.688 ;
     RECT  14.435 0.576 16.405 0.648 ;
     RECT  16.405 0.384 16.448 0.648 ;
     RECT  15.877 1.68 16.448 2.232 ;
     RECT  15.469 3.6 16.448 3.96 ;
     RECT  15.365 5.088 16.448 6.6 ;
     RECT  15.401 7.968 16.448 8.472 ;
     RECT  15.541 9.6 16.448 10.248 ;
     RECT  15.971 11.328 16.448 11.496 ;
     RECT  16.448 0.384 16.547 11.496 ;
     RECT  16.547 0.528 16.552 11.352 ;
     RECT  16.552 0.576 16.744 11.352 ;
     RECT  16.744 3.216 16.883 3.96 ;
     RECT  16.744 7.968 16.913 11.352 ;
     RECT  16.913 10.8 17.021 11.352 ;
     RECT  16.744 0.576 17.123 0.648 ;
     RECT  17.021 10.848 17.273 11.352 ;
     RECT  16.744 1.68 17.315 1.752 ;
     RECT  16.883 3.936 17.809 3.96 ;
     RECT  17.809 3.936 17.849 4.104 ;
     RECT  16.913 7.968 17.996 9.816 ;
     RECT  17.996 7.968 18.083 10.296 ;
     RECT  17.123 0.576 18.097 0.6 ;
     RECT  18.083 7.968 18.179 10.248 ;
     RECT  17.315 1.68 18.385 1.704 ;
     RECT  18.385 1.68 18.425 2.328 ;
     RECT  17.273 11.328 18.533 11.352 ;
     RECT  18.425 2.304 18.613 2.328 ;
     RECT  18.097 0.576 18.745 0.648 ;
     RECT  16.744 5.76 18.817 6.6 ;
     RECT  18.179 8.208 18.965 10.248 ;
     RECT  17.849 4.08 19.045 4.104 ;
     RECT  18.817 5.184 19.045 6.6 ;
     RECT  19.045 4.08 19.091 6.6 ;
     RECT  18.613 2.304 19.181 2.856 ;
     RECT  18.745 0.576 19.427 1.224 ;
     RECT  18.965 8.448 19.541 10.248 ;
     RECT  19.181 2.304 19.681 2.328 ;
     RECT  19.681 2.256 20.077 2.328 ;
     RECT  20.077 2.208 20.117 2.328 ;
     RECT  19.765 10.848 20.149 10.872 ;
     RECT  19.541 8.448 20.513 9.672 ;
     RECT  19.427 0.576 20.579 1.176 ;
     RECT  19.091 5.952 20.581 6.6 ;
     RECT  20.149 10.848 20.62 11.352 ;
     RECT  20.581 5.952 20.627 7.08 ;
     RECT  19.091 4.08 20.725 4.776 ;
     RECT  20.627 5.952 21.109 6.072 ;
     RECT  20.627 7.056 21.301 7.08 ;
     RECT  20.62 11.328 21.301 11.352 ;
     RECT  20.579 0.576 21.625 0.648 ;
     RECT  21.301 11.328 21.637 11.448 ;
     RECT  21.637 11.184 21.733 11.448 ;
     RECT  21.625 0.384 21.848 0.648 ;
     RECT  20.117 2.208 21.848 2.232 ;
     RECT  20.725 3.936 21.848 4.776 ;
     RECT  21.109 5.808 21.848 6.072 ;
     RECT  21.301 7.056 21.848 7.176 ;
     RECT  20.513 8.448 21.848 9.624 ;
     RECT  21.733 11.184 21.848 11.496 ;
     RECT  21.848 0.384 21.923 11.496 ;
     RECT  21.923 0.528 21.952 11.352 ;
     RECT  21.952 0.576 22.144 11.352 ;
     RECT  22.144 9.504 22.457 11.352 ;
     RECT  22.144 1.728 22.499 2.52 ;
     RECT  22.499 2.304 22.529 2.52 ;
     RECT  22.457 10.8 22.781 11.352 ;
     RECT  22.781 10.848 23.029 11.352 ;
     RECT  23.029 10.848 23.141 11.4 ;
     RECT  22.144 4.704 23.212 4.728 ;
     RECT  22.144 5.712 23.212 6.072 ;
     RECT  23.212 4.704 23.213 6.072 ;
     RECT  23.141 10.848 23.267 11.352 ;
     RECT  22.144 8.496 23.413 8.52 ;
     RECT  22.457 9.504 23.413 9.672 ;
     RECT  22.529 2.496 23.569 2.52 ;
     RECT  23.569 2.256 23.609 2.52 ;
     RECT  22.144 0.576 23.785 0.648 ;
     RECT  23.413 8.496 23.933 9.672 ;
     RECT  23.933 9.648 23.989 9.672 ;
     RECT  23.989 9.648 24.293 10.296 ;
     RECT  23.785 0.576 24.361 1.176 ;
     RECT  23.267 11.328 24.364 11.352 ;
     RECT  23.213 4.752 24.365 6.072 ;
     RECT  24.364 11.328 24.565 11.4 ;
     RECT  23.933 8.496 24.689 8.52 ;
     RECT  22.144 3.552 24.797 3.576 ;
     RECT  24.361 0.576 24.803 1.224 ;
     RECT  24.293 9.648 24.803 9.72 ;
     RECT  24.565 10.8 24.869 11.4 ;
     RECT  24.869 10.8 24.905 11.352 ;
     RECT  23.609 2.256 25.081 2.28 ;
     RECT  24.905 10.848 25.229 11.352 ;
     RECT  24.803 9.648 25.333 9.672 ;
     RECT  25.081 2.208 25.379 2.28 ;
     RECT  25.229 11.04 25.769 11.352 ;
     RECT  24.365 5.04 26.005 6.072 ;
     RECT  22.144 7.152 26.005 7.176 ;
     RECT  26.005 5.04 26.092 7.176 ;
     RECT  25.333 9.12 26.201 9.672 ;
     RECT  25.769 11.04 26.293 11.064 ;
     RECT  26.293 10.848 26.485 11.064 ;
     RECT  26.485 10.8 26.869 11.064 ;
     RECT  25.379 2.256 26.881 2.28 ;
     RECT  25.261 3.936 26.881 3.96 ;
     RECT  24.803 0.576 27.169 0.648 ;
     RECT  27.169 0.576 27.205 0.696 ;
     RECT  26.869 10.8 27.244 11.448 ;
     RECT  27.205 0.384 27.248 0.696 ;
     RECT  26.881 2.256 27.248 3.96 ;
     RECT  26.092 5.04 27.248 6.072 ;
     RECT  26.092 7.152 27.248 7.176 ;
     RECT  26.201 9.264 27.248 9.672 ;
     RECT  27.244 10.8 27.248 11.496 ;
     RECT  27.248 0.384 27.299 11.496 ;
     RECT  27.299 0.528 27.352 11.496 ;
     RECT  27.352 0.576 27.544 11.496 ;
     RECT  27.544 8.496 27.757 11.496 ;
     RECT  27.757 9.12 27.821 11.496 ;
     RECT  27.821 9.12 27.857 11.352 ;
     RECT  27.544 0.576 27.875 0.888 ;
     RECT  27.857 9.12 27.875 9.672 ;
     RECT  27.544 2.208 28.253 3.048 ;
     RECT  27.857 10.848 28.361 11.352 ;
     RECT  28.361 10.848 28.433 11.064 ;
     RECT  27.544 5.184 28.537 6.072 ;
     RECT  28.537 5.088 28.94 6.072 ;
     RECT  27.544 7.152 28.94 7.176 ;
     RECT  28.94 5.088 29.027 7.176 ;
     RECT  28.253 2.208 29.077 2.28 ;
     RECT  28.433 10.848 29.117 10.872 ;
     RECT  29.027 5.088 29.365 6.072 ;
     RECT  27.875 0.576 29.545 0.648 ;
     RECT  29.077 1.728 29.545 2.28 ;
     RECT  27.875 9.552 29.557 9.672 ;
     RECT  29.557 9.12 29.749 9.672 ;
     RECT  29.545 0.576 29.795 2.28 ;
     RECT  29.749 9.12 29.981 10.824 ;
     RECT  29.795 1.728 29.987 2.28 ;
     RECT  29.365 3.552 30.085 6.072 ;
     RECT  29.027 7.152 30.085 7.176 ;
     RECT  30.085 3.552 30.169 7.176 ;
     RECT  29.981 10.8 30.325 10.824 ;
     RECT  29.987 2.256 30.413 2.28 ;
     RECT  30.169 5.712 30.521 7.176 ;
     RECT  30.169 3.552 30.689 4.68 ;
     RECT  29.795 0.576 30.755 0.696 ;
     RECT  30.521 5.712 30.773 6.888 ;
     RECT  29.981 9.12 30.869 9.816 ;
     RECT  30.869 9.072 30.953 9.816 ;
     RECT  30.689 2.448 31.141 4.68 ;
     RECT  30.773 5.712 31.141 6.072 ;
     RECT  31.141 2.448 31.187 6.072 ;
     RECT  30.325 10.8 31.277 11.352 ;
     RECT  31.187 2.448 31.381 3.576 ;
     RECT  31.381 2.256 31.385 3.576 ;
     RECT  31.385 2.256 31.489 3.432 ;
     RECT  30.953 9.36 32.245 9.816 ;
     RECT  31.277 11.328 32.437 11.352 ;
     RECT  30.755 0.576 32.533 0.648 ;
     RECT  32.437 11.328 32.629 11.448 ;
     RECT  32.533 0.192 32.648 0.648 ;
     RECT  31.489 1.728 32.648 3.432 ;
     RECT  31.187 4.656 32.648 6.072 ;
     RECT  31.885 7.104 32.648 7.128 ;
     RECT  32.245 9.36 32.648 10.248 ;
     RECT  32.629 11.328 32.648 11.496 ;
     RECT  32.648 0.192 32.675 11.496 ;
     RECT  32.675 0.528 32.752 11.496 ;
     RECT  32.752 0.576 32.825 11.496 ;
     RECT  32.825 0.576 32.944 11.4 ;
     RECT  32.944 3.168 33.155 6.072 ;
     RECT  32.944 0.576 33.251 1.752 ;
     RECT  33.251 1.68 33.443 1.752 ;
     RECT  32.944 10.848 33.484 11.4 ;
     RECT  33.484 11.328 33.509 11.4 ;
     RECT  32.944 7.104 33.545 7.128 ;
     RECT  33.155 5.808 34.009 6.072 ;
     RECT  33.251 0.576 34.019 0.696 ;
     RECT  33.155 3.168 34.165 4.728 ;
     RECT  34.009 5.808 34.165 6.696 ;
     RECT  34.165 3.168 34.301 6.696 ;
     RECT  33.443 1.728 34.477 1.752 ;
     RECT  32.944 8.544 34.697 9.816 ;
     RECT  33.509 11.328 34.733 11.352 ;
     RECT  34.301 5.808 35.057 6.696 ;
     RECT  34.477 1.728 35.117 1.8 ;
     RECT  34.697 9.072 35.317 9.816 ;
     RECT  34.301 3.408 35.363 4.728 ;
     RECT  35.317 9.072 35.363 10.392 ;
     RECT  35.363 10.176 35.701 10.392 ;
     RECT  35.117 1.728 35.917 1.848 ;
     RECT  35.363 9.072 35.921 9.144 ;
     RECT  35.917 1.728 36.029 2.28 ;
     RECT  36.029 2.256 36.131 2.28 ;
     RECT  36.085 8.544 36.209 8.568 ;
     RECT  35.701 10.176 36.277 10.872 ;
     RECT  34.019 0.576 36.457 0.648 ;
     RECT  36.277 10.176 36.461 11.352 ;
     RECT  35.057 5.808 36.529 6.264 ;
     RECT  36.529 5.712 36.569 6.264 ;
     RECT  36.461 10.176 36.661 11.064 ;
     RECT  36.457 0.576 36.707 1.176 ;
     RECT  36.661 9.648 37.045 11.064 ;
     RECT  37.045 9.072 37.073 11.064 ;
     RECT  36.385 2.352 37.196 2.376 ;
     RECT  37.073 9.072 37.237 10.296 ;
     RECT  37.196 2.256 37.753 2.376 ;
     RECT  36.707 0.576 37.909 0.648 ;
     RECT  36.569 5.712 38.005 6.072 ;
     RECT  37.909 0.192 38.048 0.648 ;
     RECT  37.753 1.728 38.048 2.376 ;
     RECT  35.363 4.128 38.048 4.728 ;
     RECT  38.005 5.712 38.048 7.368 ;
     RECT  37.237 8.544 38.048 10.296 ;
     RECT  37.964 11.472 38.048 11.496 ;
     RECT  38.048 0.192 38.051 11.496 ;
     RECT  38.051 0.384 38.269 11.496 ;
     RECT  38.269 0.576 38.344 11.496 ;
     RECT  38.344 9.12 38.405 11.496 ;
     RECT  38.344 4.128 38.801 4.728 ;
     RECT  38.344 0.576 39.097 2.856 ;
     RECT  38.405 9.12 39.665 11.352 ;
     RECT  39.097 0.576 39.779 2.088 ;
     RECT  39.665 9.12 39.916 9.96 ;
     RECT  38.801 4.128 40.268 4.68 ;
     RECT  38.344 5.808 40.268 7.368 ;
     RECT  39.665 11.328 40.309 11.352 ;
     RECT  40.309 11.328 40.313 11.688 ;
     RECT  40.313 11.664 40.345 11.688 ;
     RECT  40.268 4.128 40.355 7.368 ;
     RECT  40.355 4.128 40.357 4.152 ;
     RECT  40.345 11.664 40.396 11.784 ;
     RECT  40.396 11.76 40.429 11.784 ;
     RECT  40.355 5.136 40.451 7.368 ;
     RECT  40.357 3.408 40.601 4.152 ;
     RECT  39.779 0.576 40.741 0.696 ;
     RECT  39.779 2.064 40.741 2.088 ;
     RECT  39.916 9.072 41.029 9.96 ;
     RECT  41.029 8.976 41.113 9.96 ;
     RECT  40.451 5.376 41.213 7.368 ;
     RECT  41.113 9.12 41.269 9.96 ;
     RECT  41.269 9.12 41.356 10.296 ;
     RECT  41.356 9.12 41.548 9.864 ;
     RECT  40.601 3.456 41.713 3.48 ;
     RECT  41.713 3.36 41.753 3.48 ;
     RECT  41.653 11.328 41.845 11.352 ;
     RECT  41.213 5.376 42.037 6.264 ;
     RECT  41.548 9.36 42.113 9.864 ;
     RECT  41.845 11.328 42.185 11.4 ;
     RECT  42.113 9.744 42.275 9.864 ;
     RECT  42.185 11.328 42.613 11.352 ;
     RECT  42.613 11.04 42.805 11.352 ;
     RECT  41.753 3.36 43.117 3.384 ;
     RECT  40.741 0.576 43.153 2.088 ;
     RECT  42.275 9.744 43.189 9.768 ;
     RECT  42.805 10.848 43.381 11.352 ;
     RECT  43.153 0.192 43.448 2.088 ;
     RECT  43.117 3.312 43.448 3.384 ;
     RECT  42.037 4.848 43.448 6.264 ;
     RECT  41.213 7.344 43.448 7.368 ;
     RECT  43.189 9.12 43.448 9.768 ;
     RECT  43.381 10.848 43.448 11.496 ;
     RECT  43.448 0.192 43.619 11.496 ;
     RECT  43.619 0.576 43.744 11.496 ;
     RECT  43.744 4.368 43.859 6.072 ;
     RECT  43.744 9.072 43.859 11.496 ;
     RECT  43.859 9.072 43.907 11.208 ;
     RECT  43.744 0.576 44.003 1.176 ;
     RECT  43.744 2.208 44.237 3.336 ;
     RECT  43.907 9.072 44.273 9.72 ;
     RECT  44.237 2.208 44.705 2.856 ;
     RECT  43.907 10.752 44.812 10.776 ;
     RECT  43.744 7.344 44.845 7.368 ;
     RECT  44.273 9.072 44.845 9.144 ;
     RECT  44.845 7.344 45.011 9.144 ;
     RECT  45.011 9.12 45.241 9.144 ;
     RECT  44.705 2.208 45.781 2.616 ;
     RECT  45.241 9.12 46.181 9.672 ;
     RECT  46.181 9.504 46.453 9.672 ;
     RECT  44.917 10.8 46.453 11.352 ;
     RECT  46.453 9.504 46.577 11.352 ;
     RECT  45.011 7.68 46.861 7.704 ;
     RECT  46.861 7.68 46.901 7.992 ;
     RECT  45.781 2.208 47.005 2.904 ;
     RECT  46.577 10.848 47.116 11.352 ;
     RECT  47.005 1.728 47.185 2.904 ;
     RECT  47.185 1.728 47.225 3.336 ;
     RECT  47.225 1.728 47.267 2.232 ;
     RECT  47.225 3.312 47.413 3.336 ;
     RECT  43.859 4.944 47.413 6.072 ;
     RECT  46.577 9.504 47.605 9.528 ;
     RECT  47.605 9.504 47.693 10.248 ;
     RECT  47.413 3.312 47.725 6.072 ;
     RECT  47.693 9.504 47.797 9.672 ;
     RECT  47.725 3.312 47.809 6.84 ;
     RECT  47.797 9.12 47.884 9.672 ;
     RECT  47.116 11.328 48.181 11.352 ;
     RECT  48.181 11.328 48.565 11.4 ;
     RECT  48.565 11.328 48.709 11.448 ;
     RECT  44.003 0.576 48.725 0.648 ;
     RECT  48.725 0.384 48.848 0.648 ;
     RECT  47.267 2.208 48.848 2.232 ;
     RECT  47.809 3.312 48.848 6.072 ;
     RECT  46.901 7.968 48.848 7.992 ;
     RECT  47.884 9.504 48.848 9.672 ;
     RECT  48.709 11.328 48.848 11.592 ;
     RECT  48.848 0.384 48.995 11.592 ;
     RECT  48.995 0.384 49.025 11.496 ;
     RECT  49.025 0.576 49.144 11.496 ;
     RECT  49.144 9.6 49.205 11.496 ;
     RECT  49.205 9.6 49.277 11.352 ;
     RECT  49.144 5.28 49.529 6.072 ;
     RECT  49.144 7.728 49.709 7.896 ;
     RECT  49.144 0.576 49.763 1.176 ;
     RECT  49.144 2.208 50.173 2.232 ;
     RECT  50.173 1.728 50.339 2.232 ;
     RECT  49.709 7.872 50.341 7.896 ;
     RECT  49.277 9.6 50.341 10.92 ;
     RECT  50.341 7.872 50.387 10.92 ;
     RECT  50.387 7.872 50.429 8.856 ;
     RECT  49.144 3.312 50.569 3.336 ;
     RECT  50.137 4.512 50.569 4.536 ;
     RECT  50.387 10.032 50.677 10.92 ;
     RECT  50.339 2.208 50.725 2.232 ;
     RECT  50.569 3.312 50.725 4.536 ;
     RECT  50.725 2.208 50.812 4.536 ;
     RECT  50.677 10.032 50.933 11.352 ;
     RECT  50.812 3.312 51.253 4.536 ;
     RECT  49.529 5.808 51.253 6.072 ;
     RECT  50.429 7.872 51.263 7.896 ;
     RECT  51.263 7.824 51.264 7.896 ;
     RECT  49.763 0.576 51.299 0.648 ;
     RECT  51.253 3.312 51.301 6.072 ;
     RECT  51.301 3.312 51.34 6.264 ;
     RECT  51.34 5.616 51.541 6.264 ;
     RECT  51.264 7.824 51.541 7.848 ;
     RECT  50.933 10.032 51.637 11.064 ;
     RECT  51.637 9.12 51.869 11.064 ;
     RECT  51.541 5.616 51.875 7.848 ;
     RECT  51.869 9.216 51.875 11.064 ;
     RECT  51.875 9.648 51.905 11.064 ;
     RECT  51.34 3.312 51.941 4.248 ;
     RECT  51.299 0.576 52.405 0.6 ;
     RECT  50.812 2.208 52.405 2.232 ;
     RECT  51.941 3.984 52.405 4.248 ;
     RECT  51.875 5.616 52.481 6.072 ;
     RECT  52.405 0.576 52.553 2.232 ;
     RECT  51.905 9.648 52.661 10.248 ;
     RECT  52.405 3.984 52.789 4.296 ;
     RECT  52.661 9.696 52.94 10.248 ;
     RECT  52.213 11.328 52.94 11.352 ;
     RECT  52.94 9.696 53.027 11.352 ;
     RECT  52.481 5.664 53.053 6.072 ;
     RECT  51.875 7.824 53.053 7.848 ;
     RECT  53.053 7.44 53.057 7.848 ;
     RECT  52.789 3.984 53.377 4.632 ;
     RECT  53.377 3.312 53.557 4.632 ;
     RECT  53.053 5.664 53.557 6.408 ;
     RECT  53.027 9.696 53.701 10.248 ;
     RECT  53.701 9.072 53.749 10.248 ;
     RECT  52.553 0.576 53.845 0.648 ;
     RECT  53.845 0.576 54.097 1.176 ;
     RECT  53.941 11.424 54.133 11.448 ;
     RECT  54.097 0.384 54.248 1.176 ;
     RECT  52.837 2.256 54.248 2.28 ;
     RECT  53.557 3.312 54.248 6.408 ;
     RECT  53.057 7.44 54.248 7.464 ;
     RECT  53.749 8.976 54.248 10.248 ;
     RECT  54.133 11.424 54.248 11.496 ;
     RECT  54.248 0.384 54.325 11.496 ;
     RECT  54.325 0.384 54.371 11.544 ;
     RECT  54.371 0.576 54.544 11.544 ;
     RECT  54.544 10.848 54.641 11.544 ;
     RECT  54.641 10.848 54.749 11.496 ;
     RECT  54.544 0.576 54.755 1.752 ;
     RECT  54.544 7.968 54.965 8.568 ;
     RECT  54.544 4.512 55.073 4.968 ;
     RECT  54.755 0.576 55.457 0.6 ;
     RECT  55.457 0.192 55.541 0.6 ;
     RECT  54.755 1.728 55.715 1.752 ;
     RECT  54.544 6.048 55.861 6.072 ;
     RECT  54.749 10.848 55.861 11.4 ;
     RECT  55.541 0.576 55.897 0.6 ;
     RECT  55.897 0.576 56.077 0.648 ;
     RECT  55.861 10.8 56.125 11.4 ;
     RECT  55.073 4.656 56.257 4.68 ;
     RECT  56.077 0.576 56.675 0.696 ;
     RECT  54.544 2.784 56.725 2.808 ;
     RECT  56.725 2.256 56.765 2.808 ;
     RECT  56.257 4.368 56.821 4.68 ;
     RECT  56.125 11.328 56.945 11.4 ;
     RECT  56.821 4.368 57.013 4.872 ;
     RECT  55.861 6.048 57.125 6.84 ;
     RECT  57.205 10.848 57.365 11.064 ;
     RECT  57.013 3.408 57.548 4.872 ;
     RECT  57.125 6.048 57.548 6.072 ;
     RECT  54.965 7.968 57.589 7.992 ;
     RECT  57.548 3.408 57.635 6.072 ;
     RECT  57.635 3.408 57.665 4.68 ;
     RECT  56.675 0.576 57.827 0.648 ;
     RECT  57.589 7.968 57.881 8.568 ;
     RECT  54.544 9.792 57.973 9.816 ;
     RECT  56.765 2.256 58.124 2.28 ;
     RECT  57.973 9.648 58.133 9.816 ;
     RECT  58.124 2.208 58.211 2.28 ;
     RECT  57.365 10.8 58.249 11.064 ;
     RECT  57.881 7.968 58.529 7.992 ;
     RECT  58.249 10.848 58.549 11.064 ;
     RECT  58.133 9.696 58.637 9.816 ;
     RECT  58.549 10.848 58.708 11.352 ;
     RECT  57.665 4.368 58.993 4.68 ;
     RECT  57.827 0.576 59.004 0.6 ;
     RECT  58.211 2.256 59.125 2.28 ;
     RECT  58.993 3.984 59.125 4.68 ;
     RECT  57.635 5.952 59.125 6.072 ;
     RECT  59.125 2.256 59.317 2.856 ;
     RECT  58.637 9.792 59.317 9.816 ;
     RECT  59.004 0.576 59.648 0.648 ;
     RECT  59.317 1.728 59.648 2.856 ;
     RECT  59.125 3.984 59.648 6.072 ;
     RECT  59.173 7.728 59.648 7.752 ;
     RECT  59.317 9.792 59.648 9.864 ;
     RECT  58.708 10.848 59.648 11.4 ;
     RECT  59.648 0.528 59.701 11.4 ;
     RECT  59.701 0.384 59.825 11.496 ;
     RECT  59.825 0.576 59.897 11.496 ;
     RECT  59.897 0.576 59.944 11.352 ;
     RECT  59.944 7.2 60.083 7.896 ;
     RECT  59.944 0.576 60.131 1.8 ;
     RECT  59.944 9.072 60.329 9.816 ;
     RECT  60.329 9.552 60.401 9.816 ;
     RECT  59.944 10.8 60.545 11.352 ;
     RECT  60.131 1.68 60.707 1.8 ;
     RECT  59.944 2.832 60.965 2.856 ;
     RECT  59.944 4.368 60.965 6.072 ;
     RECT  60.965 2.832 61.013 6.072 ;
     RECT  61.013 2.832 61.049 4.68 ;
     RECT  60.083 7.872 61.148 7.896 ;
     RECT  60.545 10.848 61.157 11.352 ;
     RECT  60.131 0.576 61.189 0.648 ;
     RECT  61.049 2.832 61.189 2.856 ;
     RECT  61.148 7.872 61.235 8.52 ;
     RECT  60.401 9.552 61.429 9.672 ;
     RECT  61.189 2.256 61.475 2.856 ;
     RECT  61.013 5.76 61.532 6.072 ;
     RECT  61.532 5.76 61.619 6.552 ;
     RECT  61.429 9.456 61.621 9.672 ;
     RECT  61.189 0.576 61.667 1.176 ;
     RECT  61.621 9.456 62.092 10.824 ;
     RECT  62.092 9.456 62.093 9.672 ;
     RECT  62.092 10.8 62.147 10.824 ;
     RECT  62.093 9.456 62.173 9.576 ;
     RECT  62.197 10.848 62.389 11.352 ;
     RECT  61.475 2.832 62.521 2.856 ;
     RECT  62.521 2.784 62.522 2.856 ;
     RECT  62.389 10.848 62.597 11.4 ;
     RECT  61.235 7.872 62.741 7.896 ;
     RECT  62.522 2.784 62.773 2.808 ;
     RECT  62.773 2.256 63.011 2.808 ;
     RECT  62.597 10.848 63.052 11.352 ;
     RECT  63.052 11.328 63.101 11.352 ;
     RECT  61.619 6.048 63.157 6.264 ;
     RECT  61.667 0.576 63.203 0.648 ;
     RECT  63.203 0.576 63.241 0.6 ;
     RECT  61.049 4.368 63.277 4.68 ;
     RECT  62.233 9.264 63.349 9.288 ;
     RECT  63.011 2.784 63.461 2.808 ;
     RECT  63.349 9.072 63.461 9.288 ;
     RECT  63.461 9.264 63.541 9.288 ;
     RECT  63.241 0.48 63.587 0.6 ;
     RECT  63.277 4.08 63.733 4.68 ;
     RECT  63.157 5.664 63.733 6.264 ;
     RECT  63.637 2.832 63.829 2.856 ;
     RECT  63.733 4.08 63.829 6.264 ;
     RECT  63.829 2.832 64.067 6.264 ;
     RECT  63.587 0.576 64.177 0.6 ;
     RECT  64.177 0.576 64.285 0.648 ;
     RECT  64.285 0.576 64.717 1.176 ;
     RECT  64.717 0.576 65.005 1.752 ;
     RECT  65.005 0.384 65.048 1.752 ;
     RECT  64.067 2.832 65.048 6.072 ;
     RECT  63.097 7.92 65.048 7.944 ;
     RECT  63.541 9.264 65.048 10.248 ;
     RECT  64.309 11.328 65.048 11.352 ;
     RECT  65.048 0.384 65.077 11.352 ;
     RECT  65.077 0.384 65.123 11.496 ;
     RECT  65.123 0.528 65.152 11.496 ;
     RECT  65.152 0.576 65.344 11.496 ;
     RECT  65.344 11.184 65.365 11.496 ;
     RECT  65.344 2.832 65.459 2.856 ;
     RECT  65.344 3.888 65.459 4.68 ;
     RECT  65.344 7.92 65.459 10.056 ;
     RECT  65.365 11.184 65.507 11.592 ;
     RECT  65.459 9.648 65.593 10.056 ;
     RECT  65.344 5.856 66.053 6.888 ;
     RECT  65.507 11.184 66.161 11.4 ;
     RECT  65.344 0.576 66.275 1.176 ;
     RECT  65.459 7.92 66.275 8.568 ;
     RECT  65.593 10.032 66.421 10.056 ;
     RECT  66.161 11.184 66.421 11.352 ;
     RECT  66.421 10.032 66.613 11.352 ;
     RECT  65.459 3.888 66.661 4.488 ;
     RECT  66.613 9.12 66.701 11.352 ;
     RECT  66.661 2.544 66.985 2.568 ;
     RECT  66.985 1.728 67.235 2.568 ;
     RECT  66.053 5.856 67.244 6.264 ;
     RECT  67.244 5.856 67.285 6.504 ;
     RECT  67.285 5.712 67.331 6.504 ;
     RECT  66.701 9.648 67.765 11.352 ;
     RECT  67.235 2.208 67.813 2.568 ;
     RECT  66.661 3.84 67.813 4.488 ;
     RECT  67.765 9.12 67.853 11.352 ;
     RECT  67.853 9.12 67.957 10.872 ;
     RECT  67.957 9.072 68.105 10.872 ;
     RECT  66.275 0.576 68.173 0.648 ;
     RECT  67.813 2.208 68.195 4.488 ;
     RECT  68.195 2.544 68.249 4.488 ;
     RECT  67.331 5.712 68.389 6.264 ;
     RECT  68.249 2.544 68.429 3.96 ;
     RECT  68.105 9.648 68.645 10.872 ;
     RECT  68.389 5.088 69.005 6.264 ;
     RECT  68.645 9.648 69.109 10.056 ;
     RECT  69.109 9.552 69.433 10.056 ;
     RECT  68.429 2.544 69.937 3.432 ;
     RECT  69.877 11.328 70.048 11.352 ;
     RECT  69.433 9.12 70.165 10.056 ;
     RECT  70.048 11.328 70.165 11.4 ;
     RECT  69.005 5.424 70.261 6.264 ;
     RECT  70.165 9.12 70.309 11.496 ;
     RECT  68.173 0.576 70.405 1.176 ;
     RECT  70.405 0.384 70.448 1.176 ;
     RECT  69.937 2.544 70.448 3.72 ;
     RECT  70.261 4.944 70.448 6.264 ;
     RECT  66.275 7.92 70.448 7.944 ;
     RECT  70.309 9.024 70.448 11.496 ;
     RECT  70.448 0.384 70.499 11.496 ;
     RECT  70.499 0.528 70.552 11.352 ;
     RECT  70.552 0.576 70.744 11.352 ;
     RECT  70.744 10.224 70.924 11.352 ;
     RECT  70.744 1.728 71.267 6.072 ;
     RECT  71.267 1.728 71.345 4.536 ;
     RECT  71.267 6 71.381 6.072 ;
     RECT  71.345 1.728 71.651 2.328 ;
     RECT  70.744 7.2 71.708 7.224 ;
     RECT  70.744 9.12 71.749 9.192 ;
     RECT  70.924 10.224 71.749 10.872 ;
     RECT  70.744 0.576 71.773 0.648 ;
     RECT  71.708 7.2 71.795 7.944 ;
     RECT  71.773 0.576 72.227 0.696 ;
     RECT  71.749 9.12 72.469 10.872 ;
     RECT  72.469 8.928 72.515 10.872 ;
     RECT  72.515 10.848 72.533 10.872 ;
     RECT  71.795 7.2 72.713 7.224 ;
     RECT  72.565 11.04 72.757 11.352 ;
     RECT  71.345 3.696 72.785 4.536 ;
     RECT  72.515 8.928 72.949 9.672 ;
     RECT  72.757 11.04 72.965 11.4 ;
     RECT  71.651 2.304 73.213 2.328 ;
     RECT  72.785 3.696 73.213 3.72 ;
     RECT  73.213 2.304 73.253 3.72 ;
     RECT  72.227 0.576 73.357 0.648 ;
     RECT  72.965 11.04 73.397 11.064 ;
     RECT  71.381 6 73.429 6.024 ;
     RECT  73.357 0.192 73.465 0.648 ;
     RECT  73.465 0.192 73.571 1.176 ;
     RECT  72.949 8.544 73.717 9.672 ;
     RECT  73.525 10.848 73.717 10.872 ;
     RECT  73.571 0.576 73.82 1.176 ;
     RECT  73.253 2.784 73.825 3.72 ;
     RECT  73.717 8.544 73.901 10.872 ;
     RECT  73.825 2.784 73.929 3.864 ;
     RECT  73.901 10.8 74.009 10.872 ;
     RECT  73.429 6 74.293 6.84 ;
     RECT  73.82 0.576 74.339 1.752 ;
     RECT  73.901 8.544 74.396 9.72 ;
     RECT  74.396 8.448 74.483 9.72 ;
     RECT  74.339 1.728 74.531 1.752 ;
     RECT  74.009 10.8 75.061 10.824 ;
     RECT  73.929 2.784 75.337 2.808 ;
     RECT  74.293 5.472 75.452 6.84 ;
     RECT  75.061 10.8 75.637 11.064 ;
     RECT  74.339 0.576 75.769 0.696 ;
     RECT  75.637 10.8 75.829 11.352 ;
     RECT  75.769 0.384 75.848 0.696 ;
     RECT  75.337 2.256 75.848 2.808 ;
     RECT  73.929 3.84 75.848 3.864 ;
     RECT  75.452 4.848 75.848 6.84 ;
     RECT  74.483 9.648 75.848 9.72 ;
     RECT  75.829 10.8 75.848 11.496 ;
     RECT  75.848 0.384 75.875 11.496 ;
     RECT  75.875 0.528 75.952 11.496 ;
     RECT  75.952 0.576 76.144 11.496 ;
     RECT  76.144 9.072 76.277 11.496 ;
     RECT  76.277 9.072 76.355 11.304 ;
     RECT  76.355 9.072 76.357 10.824 ;
     RECT  76.144 3.84 76.421 3.864 ;
     RECT  76.357 9.072 76.643 10.344 ;
     RECT  76.144 2.256 76.835 2.712 ;
     RECT  76.643 9.072 77.132 9.768 ;
     RECT  76.144 5.76 77.141 6.888 ;
     RECT  76.144 0.576 77.245 0.696 ;
     RECT  77.132 8.544 77.452 9.768 ;
     RECT  76.835 2.688 77.573 2.712 ;
     RECT  77.452 9.072 77.717 9.768 ;
     RECT  77.245 0.576 77.795 1.224 ;
     RECT  77.717 9.648 78.005 9.768 ;
     RECT  77.461 3.84 78.037 3.864 ;
     RECT  77.141 5.76 78.037 6.024 ;
     RECT  78.037 3.84 78.083 6.024 ;
     RECT  77.795 0.576 78.179 1.176 ;
     RECT  77.708 11.328 78.284 11.352 ;
     RECT  78.083 3.84 78.293 4.824 ;
     RECT  78.284 11.04 78.371 11.352 ;
     RECT  78.037 2.496 78.757 2.52 ;
     RECT  78.293 3.84 78.757 3.864 ;
     RECT  78.757 2.496 78.841 3.864 ;
     RECT  78.841 2.496 78.901 2.52 ;
     RECT  78.005 9.696 78.901 9.768 ;
     RECT  78.901 9.696 79.093 10.296 ;
     RECT  78.901 2.256 79.139 2.52 ;
     RECT  78.083 6 79.153 6.024 ;
     RECT  79.093 9.12 79.229 10.296 ;
     RECT  79.229 9.12 79.409 9.768 ;
     RECT  78.371 11.328 79.477 11.352 ;
     RECT  78.179 0.576 79.513 0.6 ;
     RECT  79.477 10.752 79.517 11.352 ;
     RECT  79.517 10.752 79.625 10.776 ;
     RECT  79.513 0.576 79.765 0.648 ;
     RECT  78.841 3.84 79.765 3.864 ;
     RECT  79.153 6 80.233 6.888 ;
     RECT  80.233 6 80.273 7.368 ;
     RECT  79.765 3.84 80.377 4.632 ;
     RECT  79.409 9.12 80.437 9.72 ;
     RECT  80.437 9.12 80.629 10.296 ;
     RECT  79.765 0.576 80.78 1.176 ;
     RECT  79.139 2.496 80.78 2.52 ;
     RECT  80.377 3.696 80.953 4.632 ;
     RECT  81.013 11.328 81.109 11.352 ;
     RECT  80.78 0.576 81.205 2.52 ;
     RECT  81.205 0.384 81.248 2.52 ;
     RECT  80.953 3.696 81.248 4.728 ;
     RECT  80.273 6 81.248 6.024 ;
     RECT  80.273 7.344 81.248 7.368 ;
     RECT  80.629 9.072 81.248 10.296 ;
     RECT  81.109 11.328 81.248 11.544 ;
     RECT  81.248 0.384 81.443 11.544 ;
     RECT  81.443 0.384 81.469 11.352 ;
     RECT  81.469 0.576 81.544 11.352 ;
     RECT  81.544 0.576 81.635 0.648 ;
     RECT  81.544 4.704 81.683 7.656 ;
     RECT  81.544 2.256 81.929 3.72 ;
     RECT  81.544 10.8 82.037 11.352 ;
     RECT  82.037 10.848 82.06 11.352 ;
     RECT  81.929 2.256 82.649 3.624 ;
     RECT  82.649 2.256 82.685 2.52 ;
     RECT  81.683 7.632 82.717 7.656 ;
     RECT  82.717 7.632 82.757 7.992 ;
     RECT  82.649 3.6 82.933 3.624 ;
     RECT  81.683 4.704 82.933 6.024 ;
     RECT  82.685 2.256 82.969 2.328 ;
     RECT  81.544 9.648 83.125 9.816 ;
     RECT  83.125 9.12 83.149 9.816 ;
     RECT  82.06 10.848 83.149 10.872 ;
     RECT  82.933 3.6 83.153 6.024 ;
     RECT  83.149 9.12 83.225 10.872 ;
     RECT  81.635 0.576 83.362 0.6 ;
     RECT  82.969 1.728 83.468 2.328 ;
     RECT  83.468 1.68 83.555 2.328 ;
     RECT  83.225 9.504 83.66 10.872 ;
     RECT  83.555 2.304 83.833 2.328 ;
     RECT  83.153 3.6 83.833 3.624 ;
     RECT  83.153 4.992 83.891 6.024 ;
     RECT  83.833 2.304 83.917 3.624 ;
     RECT  83.362 0.576 84.157 0.648 ;
     RECT  83.66 9.504 84.197 11.352 ;
     RECT  83.917 3.408 84.413 3.624 ;
     RECT  84.157 0.576 84.841 0.696 ;
     RECT  84.413 3.6 84.901 3.624 ;
     RECT  83.891 4.992 84.901 5.208 ;
     RECT  84.901 3.6 84.947 5.208 ;
     RECT  84.841 0.576 85.091 1.176 ;
     RECT  83.917 2.304 85.129 2.328 ;
     RECT  84.197 9.504 85.237 9.672 ;
     RECT  82.757 7.968 85.453 7.992 ;
     RECT  84.197 10.8 85.516 11.352 ;
     RECT  84.947 4.08 85.621 5.208 ;
     RECT  85.453 7.968 85.669 8.184 ;
     RECT  85.621 4.08 85.777 5.976 ;
     RECT  85.669 7.44 85.777 8.184 ;
     RECT  85.237 9.264 85.813 9.672 ;
     RECT  85.516 10.8 85.813 10.872 ;
     RECT  85.777 4.08 86.005 8.184 ;
     RECT  85.813 9.264 86.005 10.872 ;
     RECT  85.129 2.256 86.137 2.328 ;
     RECT  86.005 4.08 86.485 10.872 ;
     RECT  85.091 0.576 86.54 0.648 ;
     RECT  86.54 0.384 86.605 0.648 ;
     RECT  86.605 0.288 86.648 0.648 ;
     RECT  86.137 1.728 86.648 2.328 ;
     RECT  86.485 4.08 86.648 11.496 ;
     RECT  86.648 0.288 86.819 11.496 ;
     RECT  86.819 0.576 86.897 11.496 ;
     RECT  86.897 0.576 86.944 11.208 ;
     RECT  86.944 8.16 87.107 11.208 ;
     RECT  86.944 0.576 87.203 0.648 ;
     RECT  86.944 1.728 87.731 5.208 ;
     RECT  87.731 1.728 87.772 3.672 ;
     RECT  86.944 6.672 87.977 6.696 ;
     RECT  87.107 8.16 88.085 10.824 ;
     RECT  88.085 8.16 88.355 10.248 ;
     RECT  87.731 4.992 88.373 5.208 ;
     RECT  88.373 5.184 88.621 5.208 ;
     RECT  87.203 0.576 88.693 0.6 ;
     RECT  87.772 1.728 88.693 2.472 ;
     RECT  88.693 1.68 88.739 2.472 ;
     RECT  88.355 9.6 88.841 10.248 ;
     RECT  88.355 8.16 88.949 8.184 ;
     RECT  87.772 3.648 88.981 3.672 ;
     RECT  88.981 3.456 89.021 3.672 ;
     RECT  88.841 9.648 89.077 10.248 ;
     RECT  89.077 9.648 89.228 10.296 ;
     RECT  88.652 11.328 89.228 11.352 ;
     RECT  88.693 0.576 89.233 0.648 ;
     RECT  88.739 1.68 89.233 1.704 ;
     RECT  89.228 9.648 89.381 11.352 ;
     RECT  88.621 5.184 89.941 5.448 ;
     RECT  89.941 5.184 90.028 5.976 ;
     RECT  89.233 0.576 90.083 1.704 ;
     RECT  89.381 9.648 90.101 9.72 ;
     RECT  90.028 5.184 90.173 5.448 ;
     RECT  90.083 0.576 90.457 0.696 ;
     RECT  90.173 5.184 90.457 5.208 ;
     RECT  90.457 0.192 90.467 0.696 ;
     RECT  90.101 9.696 90.805 9.72 ;
     RECT  89.381 10.848 90.805 11.352 ;
     RECT  90.467 0.192 90.851 0.648 ;
     RECT  89.701 7.488 91.189 7.512 ;
     RECT  90.457 5.136 91.393 5.208 ;
     RECT  90.851 0.384 91.429 0.648 ;
     RECT  90.083 1.68 91.429 1.704 ;
     RECT  91.393 5.04 91.429 5.208 ;
     RECT  89.021 3.456 91.681 3.48 ;
     RECT  90.805 9.696 91.765 11.352 ;
     RECT  91.765 9.696 91.861 11.4 ;
     RECT  91.429 0.384 91.909 1.704 ;
     RECT  91.189 7.488 91.909 7.992 ;
     RECT  91.861 9.696 91.909 11.496 ;
     RECT  91.909 7.392 91.933 7.992 ;
     RECT  91.909 0.288 92.048 1.704 ;
     RECT  91.681 3.36 92.048 3.48 ;
     RECT  91.429 5.04 92.048 5.496 ;
     RECT  91.933 6.816 92.048 7.992 ;
     RECT  91.909 9.696 92.048 11.592 ;
     RECT  92.048 0.288 92.195 11.592 ;
     RECT  92.195 0.288 92.341 11.352 ;
     RECT  92.341 0.192 92.344 11.352 ;
     RECT  92.344 11.184 92.483 11.352 ;
     RECT  92.344 0.192 92.579 1.704 ;
     RECT  92.344 5.04 92.585 5.496 ;
     RECT  92.344 9.072 92.621 9.816 ;
     RECT  92.621 9.408 92.909 9.816 ;
     RECT  92.579 0.192 92.963 0.696 ;
     RECT  92.344 3.36 93.557 3.432 ;
     RECT  92.483 11.328 93.593 11.352 ;
     RECT  93.557 3.408 93.629 3.432 ;
     RECT  92.579 1.68 93.805 1.704 ;
     RECT  92.909 9.552 93.877 9.816 ;
     RECT  93.805 1.68 93.923 1.752 ;
     RECT  93.685 10.848 94.348 11.064 ;
     RECT  92.963 0.576 94.381 0.696 ;
     RECT  93.923 1.68 94.381 1.704 ;
     RECT  94.348 10.848 94.493 10.872 ;
     RECT  94.381 0.576 94.633 1.704 ;
     RECT  93.877 9.12 94.637 9.816 ;
     RECT  94.633 0.192 94.691 1.704 ;
     RECT  94.597 3.408 94.885 3.432 ;
     RECT  94.885 2.88 94.925 3.432 ;
     RECT  92.585 5.472 95.137 5.496 ;
     RECT  95.137 5.472 95.177 5.688 ;
     RECT  94.637 9.648 95.221 9.816 ;
     RECT  94.691 0.192 95.267 0.648 ;
     RECT  95.029 3.936 95.321 3.96 ;
     RECT  95.221 9.648 95.429 10.248 ;
     RECT  92.344 6.816 95.468 6.84 ;
     RECT  94.645 8.544 95.509 8.568 ;
     RECT  95.468 6.816 95.537 7.416 ;
     RECT  95.537 7.392 95.555 7.416 ;
     RECT  94.691 1.68 95.857 1.704 ;
     RECT  94.925 2.88 95.857 2.904 ;
     RECT  95.509 8.448 96.181 8.568 ;
     RECT  95.429 9.648 96.181 9.672 ;
     RECT  95.177 5.664 96.253 5.688 ;
     RECT  95.857 1.68 96.323 2.904 ;
     RECT  96.181 8.448 96.329 9.672 ;
     RECT  95.797 10.8 96.565 11.064 ;
     RECT  96.323 2.88 96.577 2.904 ;
     RECT  95.267 0.576 96.721 0.648 ;
     RECT  96.721 0.192 96.995 0.648 ;
     RECT  96.577 2.88 97.148 3.432 ;
     RECT  96.995 0.384 97.448 0.648 ;
     RECT  96.323 1.68 97.448 1.704 ;
     RECT  97.148 2.88 97.448 4.104 ;
     RECT  96.253 5.184 97.448 5.688 ;
     RECT  96.329 8.448 97.448 8.472 ;
     RECT  96.329 9.552 97.448 9.672 ;
     RECT  96.565 10.8 97.448 11.352 ;
     RECT  97.448 0.384 97.525 11.352 ;
     RECT  97.525 0.384 97.625 11.496 ;
     RECT  97.625 0.576 97.744 11.496 ;
     RECT  97.744 10.8 97.859 11.496 ;
     RECT  97.744 8.448 97.913 9.576 ;
     RECT  97.859 10.8 97.921 11.352 ;
     RECT  97.744 1.68 97.955 1.752 ;
     RECT  97.744 4.512 98.099 5.976 ;
     RECT  97.921 10.848 98.201 11.352 ;
     RECT  98.099 4.512 98.237 5.496 ;
     RECT  98.201 10.848 98.561 11.064 ;
     RECT  97.913 8.448 98.783 9.528 ;
     RECT  98.783 7.968 98.849 9.528 ;
     RECT  98.809 6.816 98.893 6.84 ;
     RECT  97.744 0.576 98.953 0.648 ;
     RECT  97.955 1.68 98.953 1.704 ;
     RECT  98.561 10.848 99.061 10.872 ;
     RECT  98.849 9.072 99.325 9.528 ;
     RECT  98.953 0.576 99.341 1.704 ;
     RECT  99.325 9.504 99.445 9.528 ;
     RECT  99.061 10.8 99.445 10.872 ;
     RECT  99.445 9.504 99.605 10.872 ;
     RECT  98.237 5.472 99.637 5.496 ;
     RECT  99.605 9.648 99.677 10.872 ;
     RECT  99.341 0.576 99.683 2.28 ;
     RECT  99.683 0.576 99.875 1.704 ;
     RECT  99.677 10.848 100.021 10.872 ;
     RECT  99.637 5.472 100.181 5.688 ;
     RECT  98.849 7.968 100.429 7.992 ;
     RECT  100.429 7.968 100.469 8.328 ;
     RECT  97.744 3.408 100.937 3.432 ;
     RECT  99.875 1.68 101.005 1.704 ;
     RECT  99.677 9.648 101.173 9.72 ;
     RECT  100.469 8.304 101.228 8.328 ;
     RECT  101.173 9.6 101.228 9.72 ;
     RECT  99.875 0.576 101.329 0.648 ;
     RECT  101.005 1.68 101.329 2.28 ;
     RECT  101.228 8.304 101.411 9.72 ;
     RECT  100.021 10.848 101.749 11.352 ;
     RECT  101.329 0.576 101.941 2.28 ;
     RECT  101.689 3.312 101.941 3.336 ;
     RECT  101.411 9.36 102.325 9.72 ;
     RECT  101.749 10.848 102.325 11.4 ;
     RECT  101.411 8.304 102.589 8.328 ;
     RECT  101.941 0.576 102.661 3.336 ;
     RECT  102.325 9.36 102.661 11.4 ;
     RECT  102.589 7.344 102.668 8.328 ;
     RECT  102.661 9.36 102.668 11.496 ;
     RECT  102.661 0.288 102.848 3.336 ;
     RECT  100.181 5.472 102.848 5.496 ;
     RECT  102.668 7.344 102.848 11.496 ;
     RECT  102.848 0.288 102.947 11.496 ;
     RECT  102.947 0.528 102.952 11.352 ;
     RECT  102.952 0.576 103.144 11.352 ;
     RECT  103.144 2.784 103.238 3.336 ;
     RECT  103.238 2.832 103.321 3.336 ;
     RECT  103.144 0.576 103.331 0.696 ;
     RECT  103.144 10.848 103.385 11.352 ;
     RECT  103.144 5.472 103.565 5.496 ;
     RECT  103.144 1.68 103.715 1.752 ;
     RECT  103.144 8.544 103.715 9.24 ;
     RECT  103.715 8.544 103.745 9.144 ;
     RECT  103.321 2.88 103.781 3.336 ;
     RECT  103.781 2.88 103.907 2.904 ;
     RECT  103.715 1.68 104.177 1.704 ;
     RECT  103.385 10.848 104.285 10.92 ;
     RECT  103.331 0.576 104.291 0.648 ;
     RECT  104.245 8.496 104.332 8.52 ;
     RECT  104.285 10.848 104.437 10.872 ;
     RECT  104.437 10.8 104.63 10.872 ;
     RECT  104.291 0.576 104.689 0.6 ;
     RECT  104.63 10.848 104.753 10.872 ;
    LAYER M5 ;
     RECT  0.384 0.144 104.664 0.181 ;
     RECT  0.144 0.181 104.664 0.611 ;
     RECT  0.144 0.611 8.088 0.659 ;
     RECT  9.216 0.611 63.192 0.659 ;
     RECT  64.32 0.611 72.6 0.659 ;
     RECT  73.92 0.611 104.28 0.659 ;
     RECT  0.144 0.659 0.6 0.707 ;
     RECT  1.92 0.659 4.056 0.707 ;
     RECT  5.184 0.659 7.32 0.707 ;
     RECT  11.04 0.659 11.736 0.707 ;
     RECT  14.016 0.659 17.304 0.707 ;
     RECT  27.24 0.659 38.352 0.707 ;
     RECT  39.36 0.659 41.688 0.707 ;
     RECT  54.144 0.659 56.664 0.707 ;
     RECT  69.696 0.659 72.216 0.707 ;
     RECT  84.48 0.659 86.952 0.707 ;
     RECT  89.664 0.659 90.456 0.707 ;
     RECT  91.776 0.659 94.68 0.707 ;
     RECT  91.776 0.707 92.568 0.899 ;
     RECT  41.088 0.707 41.688 1.139 ;
     RECT  2.304 0.707 4.056 1.187 ;
     RECT  5.184 0.707 6.36 1.187 ;
     RECT  9.216 0.659 9.24 1.187 ;
     RECT  19.2 0.659 20.568 1.187 ;
     RECT  24 0.659 25.368 1.187 ;
     RECT  34.752 0.707 38.352 1.187 ;
     RECT  39.36 0.707 39.768 1.187 ;
     RECT  41.664 1.139 41.688 1.187 ;
     RECT  42.816 0.659 44.376 1.187 ;
     RECT  48.84 0.659 50.328 1.187 ;
     RECT  54.144 0.707 55.704 1.187 ;
     RECT  59.52 0.659 61.656 1.187 ;
     RECT  64.512 0.659 68.568 1.187 ;
     RECT  69.696 0.707 71.64 1.187 ;
     RECT  73.92 0.659 83.16 1.187 ;
     RECT  85.056 0.707 86.952 1.187 ;
     RECT  89.664 0.707 90.072 1.187 ;
     RECT  91.776 0.899 92.472 1.187 ;
     RECT  93.888 0.707 94.68 1.187 ;
     RECT  99.264 0.659 99.864 1.187 ;
     RECT  19.392 1.187 19.8 1.235 ;
     RECT  24.768 1.187 25.368 1.235 ;
     RECT  39.744 1.187 39.768 1.235 ;
     RECT  73.92 1.187 77.784 1.235 ;
     RECT  99.264 1.187 99.672 1.283 ;
     RECT  73.92 1.235 76.824 1.669 ;
     RECT  80.832 1.187 83.16 1.669 ;
     RECT  88.128 0.659 88.536 1.669 ;
     RECT  31.488 0.707 33.432 1.715 ;
     RECT  3.84 1.187 4.056 1.763 ;
     RECT  5.472 1.187 6.36 1.763 ;
     RECT  15.168 0.707 17.304 1.763 ;
     RECT  21.84 0.659 22.488 1.763 ;
     RECT  27.24 0.707 29.976 1.763 ;
     RECT  31.488 1.715 32.952 1.763 ;
     RECT  46.656 0.659 47.256 1.763 ;
     RECT  50.304 1.187 50.328 1.763 ;
     RECT  55.68 1.187 55.704 1.763 ;
     RECT  64.896 1.187 65.352 1.763 ;
     RECT  67.2 1.187 68.184 1.763 ;
     RECT  70.44 1.187 71.64 1.763 ;
     RECT  73.872 1.669 76.824 1.763 ;
     RECT  88.128 1.669 88.728 1.763 ;
     RECT  93.888 1.187 93.912 1.763 ;
     RECT  97.44 0.659 97.944 1.763 ;
     RECT  34.752 1.187 36.12 1.811 ;
     RECT  35.136 1.811 36.12 1.859 ;
     RECT  42.96 1.187 44.376 2.099 ;
     RECT  25.344 1.235 25.368 2.243 ;
     RECT  27.24 1.763 28.44 2.243 ;
     RECT  51.84 0.659 53.016 2.243 ;
     RECT  58.176 0.659 58.2 2.243 ;
     RECT  67.824 1.763 68.184 2.243 ;
     RECT  96.192 0.659 96.216 2.243 ;
     RECT  52.992 2.243 53.016 2.245 ;
     RECT  54.24 1.187 54.552 2.245 ;
     RECT  59.52 1.187 61.464 2.245 ;
     RECT  99.648 1.283 99.672 2.245 ;
     RECT  4.032 1.763 4.056 2.291 ;
     RECT  5.472 1.763 5.952 2.291 ;
     RECT  14.016 0.707 14.04 2.291 ;
     RECT  19.776 1.235 19.8 2.291 ;
     RECT  31.488 1.763 31.512 2.291 ;
     RECT  35.328 1.859 36.12 2.291 ;
     RECT  37.248 1.187 38.352 2.291 ;
     RECT  43.44 2.099 44.376 2.291 ;
     RECT  46.656 1.763 46.68 2.291 ;
     RECT  52.992 2.245 54.552 2.291 ;
     RECT  59.136 2.245 61.464 2.291 ;
     RECT  62.976 0.659 63 2.291 ;
     RECT  75.456 1.763 76.824 2.291 ;
     RECT  79.104 1.187 79.128 2.291 ;
     RECT  80.832 1.669 83.544 2.291 ;
     RECT  85.248 1.187 86.952 2.291 ;
     RECT  88.512 1.763 88.728 2.291 ;
     RECT  99.36 2.245 99.672 2.291 ;
     RECT  101.184 0.659 103.896 2.291 ;
     RECT  0.144 0.707 0.552 2.339 ;
     RECT  8.688 1.669 8.712 2.339 ;
     RECT  83.52 2.291 83.544 2.339 ;
     RECT  32.496 1.763 32.952 2.483 ;
     RECT  88.704 2.291 88.728 2.483 ;
     RECT  80.832 2.291 81.552 2.531 ;
     RECT  12.336 1.669 12.36 2.579 ;
     RECT  11.04 0.707 11.352 2.725 ;
     RECT  38.04 2.291 38.352 2.821 ;
     RECT  65.04 1.763 65.352 2.821 ;
     RECT  70.44 1.763 70.752 2.821 ;
     RECT  1.968 1.669 1.992 2.867 ;
     RECT  59.136 2.291 61.032 2.867 ;
     RECT  96.288 2.245 96.312 2.915 ;
     RECT  101.952 2.291 103.896 2.915 ;
     RECT  70.44 2.821 71.208 2.963 ;
     RECT  27.24 2.243 27.96 3.059 ;
     RECT  85.824 2.291 86.952 3.157 ;
     RECT  15.888 1.763 16.752 3.205 ;
     RECT  2.064 3.205 2.088 3.253 ;
     RECT  43.44 2.291 43.752 3.301 ;
     RECT  50.736 2.677 50.76 3.347 ;
     RECT  101.952 2.915 103.272 3.347 ;
     RECT  65.04 2.821 65.448 3.397 ;
     RECT  83.856 2.821 83.88 3.397 ;
     RECT  92.04 1.187 92.352 3.397 ;
     RECT  97.44 1.763 97.752 3.397 ;
     RECT  10.704 2.725 11.352 3.443 ;
     RECT  35.328 2.291 35.352 3.443 ;
     RECT  61.008 2.867 61.032 3.443 ;
     RECT  78.768 2.485 78.792 3.443 ;
     RECT  99.36 2.291 99.384 3.443 ;
     RECT  83.856 3.397 84.312 3.589 ;
     RECT  85.824 3.157 87.72 3.589 ;
     RECT  73.872 1.763 73.896 3.731 ;
     RECT  10.752 3.443 11.352 3.733 ;
     RECT  64.128 3.397 65.448 3.733 ;
     RECT  67.824 2.243 67.848 3.875 ;
     RECT  27.24 3.059 27.552 3.925 ;
     RECT  48.84 1.187 49.152 3.925 ;
     RECT  2.064 3.253 2.712 3.971 ;
     RECT  15.888 3.205 16.872 3.971 ;
     RECT  51.84 2.243 51.864 3.973 ;
     RECT  7.44 3.301 7.464 4.019 ;
     RECT  83.856 3.589 87.72 4.115 ;
     RECT  97.2 3.397 97.752 4.115 ;
     RECT  34.176 3.157 34.2 4.163 ;
     RECT  38.04 2.821 39.048 4.163 ;
     RECT  85.632 4.115 87.72 4.259 ;
     RECT  0.24 2.339 0.552 4.261 ;
     RECT  51.84 3.973 52.824 4.261 ;
     RECT  53.856 2.291 54.552 4.261 ;
     RECT  57.024 3.397 57.048 4.357 ;
     RECT  43.44 3.301 43.848 4.403 ;
     RECT  10.752 3.733 11.976 4.501 ;
     RECT  18.624 2.821 18.648 4.501 ;
     RECT  30.72 2.677 30.744 4.501 ;
     RECT  70.44 2.963 70.752 4.501 ;
     RECT  81.24 2.531 81.552 4.501 ;
     RECT  83.856 4.115 84.312 4.501 ;
     RECT  97.44 4.115 97.752 4.501 ;
     RECT  79.776 3.829 79.8 4.643 ;
     RECT  30.72 4.501 31.176 4.691 ;
     RECT  32.64 2.483 32.952 4.693 ;
     RECT  33.984 4.501 34.008 4.693 ;
     RECT  80.832 4.501 81.552 4.693 ;
     RECT  40.368 3.397 40.392 4.837 ;
     RECT  57.024 4.357 57.624 4.837 ;
     RECT  75.84 2.291 76.152 4.837 ;
     RECT  0.24 4.261 0.984 4.933 ;
     RECT  70.44 4.501 71.256 4.933 ;
     RECT  2.688 3.971 2.712 5.029 ;
     RECT  91.728 3.397 92.352 5.029 ;
     RECT  26.304 3.925 27.552 5.075 ;
     RECT  29.376 4.501 29.4 5.077 ;
     RECT  31.152 4.691 31.176 5.077 ;
     RECT  32.64 4.693 34.008 5.077 ;
     RECT  51.84 4.261 54.552 5.077 ;
     RECT  59.64 2.867 59.952 5.077 ;
     RECT  68.352 3.925 68.376 5.077 ;
     RECT  40.32 4.837 40.392 5.125 ;
     RECT  40.32 5.125 40.44 5.171 ;
     RECT  80.832 4.693 81.768 5.171 ;
     RECT  91.44 5.029 92.352 5.173 ;
     RECT  18.624 4.501 19.08 5.219 ;
     RECT  70.272 4.933 71.256 5.219 ;
     RECT  9.216 2.677 9.24 5.365 ;
     RECT  40.368 5.171 40.44 5.365 ;
     RECT  10.752 4.501 12.504 5.459 ;
     RECT  31.152 5.077 34.008 5.459 ;
     RECT  56.832 4.837 57.624 5.459 ;
     RECT  75.504 4.837 76.152 5.461 ;
     RECT  2.256 5.029 2.712 5.507 ;
     RECT  74.64 5.461 76.152 5.507 ;
     RECT  63.84 3.733 65.448 5.605 ;
     RECT  33.984 5.459 34.008 5.653 ;
     RECT  63.744 5.605 65.448 5.653 ;
     RECT  82.944 4.501 84.312 5.653 ;
     RECT  97.44 4.501 98.088 5.653 ;
     RECT  31.152 5.459 32.952 5.747 ;
     RECT  59.136 5.077 60.696 5.749 ;
     RECT  75.84 5.507 76.152 5.749 ;
     RECT  78.048 4.789 78.072 5.749 ;
     RECT  23.952 4.741 23.976 5.795 ;
     RECT  75.84 5.749 78.072 5.795 ;
     RECT  20.736 3.925 20.76 5.797 ;
     RECT  21.84 1.763 22.152 5.797 ;
     RECT  63.168 5.653 65.448 5.845 ;
     RECT  18.624 5.219 18.648 5.941 ;
     RECT  20.736 5.797 22.152 5.987 ;
     RECT  82.56 5.653 84.312 5.987 ;
     RECT  85.632 4.259 87.192 5.987 ;
     RECT  89.952 5.413 89.976 5.987 ;
     RECT  96.768 5.653 98.088 5.987 ;
     RECT  83.856 5.987 84.312 6.035 ;
     RECT  0.048 4.933 0.984 6.179 ;
     RECT  26.688 5.075 27.552 6.229 ;
     RECT  67.296 5.701 67.32 6.515 ;
     RECT  59.136 5.749 61.608 6.563 ;
     RECT  20.736 5.987 20.76 6.565 ;
     RECT  29.04 5.077 30.12 6.661 ;
     RECT  80.832 5.171 81.552 6.661 ;
     RECT  82.56 5.987 82.584 6.661 ;
     RECT  4.224 2.725 4.248 6.805 ;
     RECT  8.448 5.365 9.24 6.805 ;
     RECT  47.424 4.261 47.448 6.805 ;
     RECT  48.72 3.925 49.152 6.805 ;
     RECT  56.832 5.459 57.048 6.805 ;
     RECT  99.648 5.653 99.672 6.805 ;
     RECT  74.64 5.507 74.664 6.851 ;
     RECT  28.992 6.661 30.12 6.899 ;
     RECT  63.168 5.845 66.024 6.899 ;
     RECT  75.84 5.795 77.112 6.899 ;
     RECT  20.592 6.565 20.76 7.091 ;
     RECT  26.016 6.229 27.552 7.187 ;
     RECT  28.992 6.899 29.4 7.187 ;
     RECT  12.48 5.459 12.504 7.189 ;
     RECT  0.144 6.179 0.984 7.237 ;
     RECT  2.688 5.507 2.712 7.237 ;
     RECT  95.04 3.925 95.064 7.381 ;
     RECT  85.824 5.987 87.192 7.475 ;
     RECT  80.832 6.661 82.584 7.667 ;
     RECT  4.224 6.805 4.584 7.957 ;
     RECT  47.424 6.805 49.152 8.003 ;
     RECT  56.448 6.805 57.048 8.003 ;
     RECT  98.832 6.805 99.672 8.003 ;
     RECT  7.488 6.805 9.24 8.053 ;
     RECT  7.488 8.053 9.432 8.099 ;
     RECT  3.84 7.957 4.584 8.195 ;
     RECT  15.888 3.971 16.752 8.197 ;
     RECT  18.144 5.941 18.648 8.197 ;
     RECT  14.496 7.765 14.52 8.483 ;
     RECT  5.64 2.291 5.952 8.485 ;
     RECT  15.888 8.197 18.648 8.485 ;
     RECT  26.688 7.187 27.552 8.485 ;
     RECT  59.136 6.563 60.696 8.485 ;
     RECT  96.768 5.987 97.752 8.485 ;
     RECT  10.752 5.459 11.352 8.533 ;
     RECT  20.736 7.091 20.76 8.533 ;
     RECT  21.84 5.987 22.152 8.533 ;
     RECT  31.68 5.747 32.952 8.533 ;
     RECT  33.984 5.653 34.2 8.533 ;
     RECT  38.04 4.163 38.352 8.533 ;
     RECT  51.264 5.077 54.552 8.533 ;
     RECT  56.832 8.003 57.048 8.533 ;
     RECT  63.168 6.899 65.448 8.533 ;
     RECT  74.448 8.437 74.472 8.533 ;
     RECT  95.04 7.381 95.544 8.533 ;
     RECT  51.264 8.533 54.744 8.821 ;
     RECT  71.76 7.909 71.784 8.917 ;
     RECT  72.96 8.533 72.984 8.917 ;
     RECT  40.368 5.365 40.92 8.965 ;
     RECT  8.448 8.099 9.432 9.061 ;
     RECT  31.68 8.533 34.584 9.061 ;
     RECT  36.096 8.533 36.12 9.061 ;
     RECT  37.248 8.533 38.352 9.061 ;
     RECT  40.368 8.965 41.064 9.061 ;
     RECT  43.44 4.403 43.752 9.061 ;
     RECT  44.976 7.333 45 9.061 ;
     RECT  68.352 5.077 68.76 9.061 ;
     RECT  71.76 8.917 72.984 9.061 ;
     RECT  74.304 8.533 74.472 9.061 ;
     RECT  75.84 6.899 76.152 9.061 ;
     RECT  77.184 8.533 77.4 9.061 ;
     RECT  80.832 7.667 81.552 9.061 ;
     RECT  86.64 7.475 87.192 9.061 ;
     RECT  91.2 5.173 92.352 9.061 ;
     RECT  96.768 8.485 97.944 9.061 ;
     RECT  99.648 8.003 99.672 9.061 ;
     RECT  101.952 3.347 103.152 9.061 ;
     RECT  0.144 7.237 2.712 9.109 ;
     RECT  3.84 8.195 4.248 9.109 ;
     RECT  5.64 8.485 6.936 9.109 ;
     RECT  8.064 9.061 9.432 9.109 ;
     RECT  10.56 8.533 11.352 9.109 ;
     RECT  12.48 7.189 12.6 9.109 ;
     RECT  14.784 8.485 18.648 9.109 ;
     RECT  26.688 8.485 27.72 9.109 ;
     RECT  29.376 7.187 29.4 9.109 ;
     RECT  30.912 9.061 38.352 9.109 ;
     RECT  39.936 9.061 41.064 9.109 ;
     RECT  42.048 4.837 42.072 9.109 ;
     RECT  43.44 9.061 45 9.109 ;
     RECT  47.424 8.003 47.448 9.109 ;
     RECT  48.72 8.003 49.152 9.109 ;
     RECT  63.168 8.533 66.264 9.109 ;
     RECT  67.968 9.061 68.76 9.109 ;
     RECT  70.272 5.219 70.752 9.109 ;
     RECT  80.64 9.061 81.552 9.109 ;
     RECT  82.56 7.667 82.584 9.109 ;
     RECT  86.208 9.061 87.192 9.109 ;
     RECT  94.656 8.533 95.544 9.109 ;
     RECT  96.768 9.061 99.672 9.109 ;
     RECT  101.28 9.061 103.152 9.109 ;
     RECT  104.256 8.485 104.28 9.109 ;
     RECT  23.424 9.109 23.448 9.157 ;
     RECT  67.776 9.109 70.752 9.157 ;
     RECT  71.76 9.061 74.472 9.157 ;
     RECT  91.2 9.061 92.472 9.397 ;
     RECT  59.136 8.485 61.224 9.445 ;
     RECT  20.736 8.533 22.152 9.493 ;
     RECT  23.424 9.157 23.832 9.493 ;
     RECT  59.136 9.445 61.464 9.541 ;
     RECT  91.2 9.397 92.76 9.541 ;
     RECT  93.888 9.109 99.672 9.541 ;
     RECT  5.64 9.109 9.432 9.589 ;
     RECT  14.784 9.109 19.224 9.589 ;
     RECT  47.424 9.109 49.152 9.589 ;
     RECT  50.352 8.821 54.744 9.589 ;
     RECT  86.016 9.109 88.344 9.589 ;
     RECT  101.28 9.109 104.28 9.589 ;
     RECT  5.472 9.589 9.432 9.637 ;
     RECT  10.56 9.109 13.08 9.637 ;
     RECT  14.784 9.589 19.608 9.637 ;
     RECT  20.736 9.493 23.832 9.637 ;
     RECT  25.344 9.109 27.864 9.637 ;
     RECT  29.376 9.109 42.072 9.637 ;
     RECT  56.832 8.533 57.624 9.637 ;
     RECT  63.168 9.109 66.648 9.637 ;
     RECT  67.776 9.157 74.472 9.637 ;
     RECT  75.84 9.061 77.592 9.637 ;
     RECT  79.104 9.109 81.552 9.637 ;
     RECT  82.56 9.109 83.16 9.637 ;
     RECT  84.288 6.035 84.312 9.637 ;
     RECT  91.2 9.541 99.672 9.637 ;
     RECT  101.184 9.589 104.28 9.637 ;
     RECT  5.472 9.637 23.832 9.685 ;
     RECT  25.344 9.637 42.072 9.685 ;
     RECT  56.832 9.637 58.008 9.685 ;
     RECT  59.136 9.541 62.136 9.685 ;
     RECT  63.168 9.637 74.472 9.685 ;
     RECT  75.84 9.637 77.976 9.685 ;
     RECT  79.104 9.637 83.16 9.685 ;
     RECT  91.2 9.637 104.28 9.685 ;
     RECT  5.472 9.685 42.072 9.829 ;
     RECT  43.2 9.109 46.104 9.829 ;
     RECT  0.144 9.109 4.248 10.213 ;
     RECT  5.472 9.829 46.104 10.213 ;
     RECT  47.424 9.589 54.744 10.213 ;
     RECT  84.288 9.637 84.888 10.213 ;
     RECT  86.016 9.589 88.536 10.213 ;
     RECT  84.288 10.213 88.536 10.261 ;
     RECT  89.856 9.685 104.28 10.261 ;
     RECT  56.832 9.685 62.136 10.789 ;
     RECT  63.168 9.685 83.16 10.789 ;
     RECT  84.288 10.261 104.28 10.789 ;
     RECT  0.144 10.213 54.744 10.837 ;
     RECT  55.872 10.789 62.136 10.837 ;
     RECT  63.168 10.789 104.472 10.837 ;
     RECT  0.144 10.837 104.664 11.507 ;
     RECT  0.384 11.507 104.664 11.728 ;
     RECT  15.888 11.728 15.912 11.795 ;
     RECT  40.368 11.728 40.392 11.795 ;
    LAYER M6 ;
     RECT  0 0.996 105.84 1.86 ;
     RECT  0 6.396 105.84 7.26 ;
  END
END ot_attn_bank_sn544
END LIBRARY
